VERSION 5.8 ;
BUSBITCHARS "[]" ;
DIVIDERCHAR "/" ;
UNITS
    DATABASE MICRONS 1000 ;
END UNITS

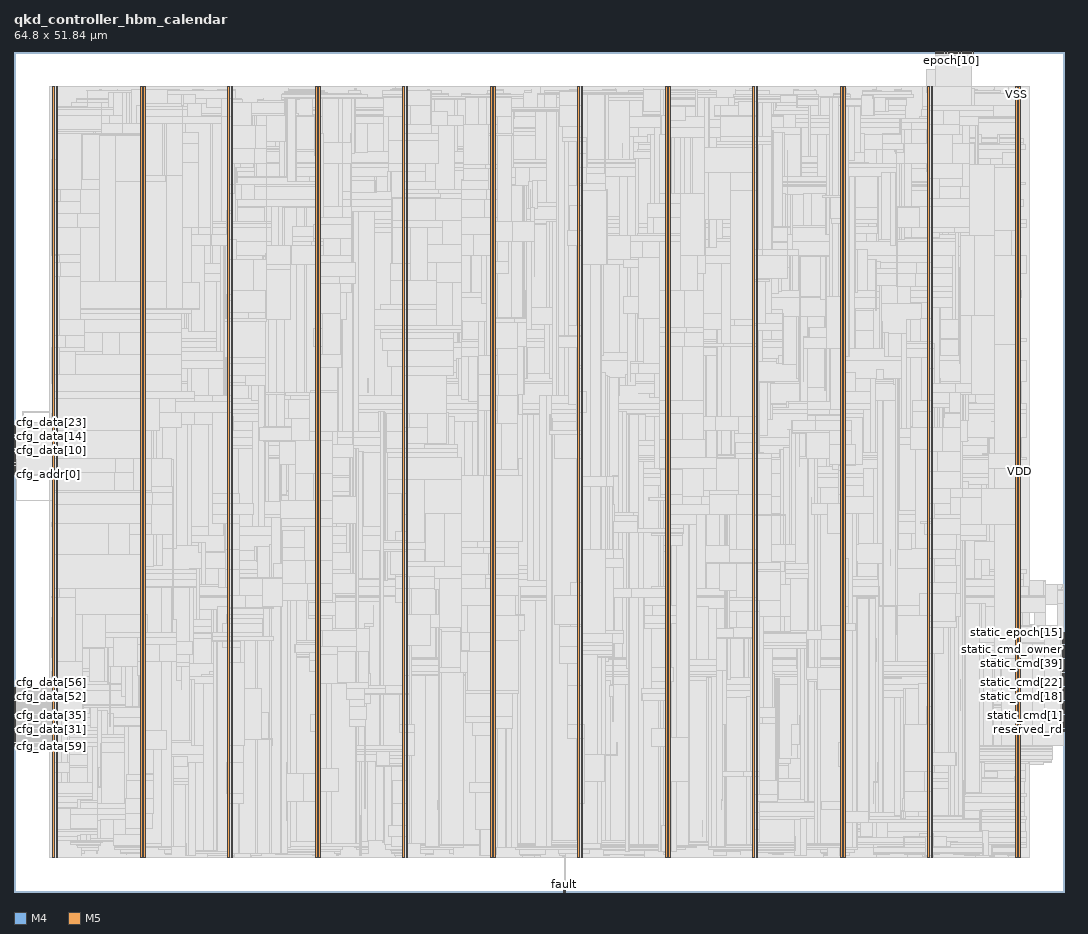
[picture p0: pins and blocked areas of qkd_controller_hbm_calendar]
MACRO qkd_controller_hbm_calendar
  FOREIGN qkd_controller_hbm_calendar 0 0 ;
  CLASS BLOCK ;
  SIZE 64.8 BY 51.84 ;
  PIN cfg_addr[0]
    DIRECTION INPUT ;
    USE SIGNAL ;
    PORT
      LAYER M4 ;
        RECT  0 25.776 0.084 25.8 ;
    END
  END cfg_addr[0]
  PIN cfg_addr[1]
    DIRECTION INPUT ;
    USE SIGNAL ;
    PORT
      LAYER M4 ;
        RECT  0 25.872 0.084 25.896 ;
    END
  END cfg_addr[1]
  PIN cfg_addr[2]
    DIRECTION INPUT ;
    USE SIGNAL ;
    PORT
      LAYER M4 ;
        RECT  0 25.968 0.084 25.992 ;
    END
  END cfg_addr[2]
  PIN cfg_addr[3]
    DIRECTION INPUT ;
    USE SIGNAL ;
    PORT
      LAYER M4 ;
        RECT  0 26.064 0.084 26.088 ;
    END
  END cfg_addr[3]
  PIN cfg_addr[4]
    DIRECTION INPUT ;
    USE SIGNAL ;
    PORT
      LAYER M4 ;
        RECT  0 26.16 0.084 26.184 ;
    END
  END cfg_addr[4]
  PIN cfg_data[0]
    DIRECTION INPUT ;
    USE SIGNAL ;
    PORT
      LAYER M4 ;
        RECT  0 26.256 0.084 26.28 ;
    END
  END cfg_data[0]
  PIN cfg_data[10]
    DIRECTION INPUT ;
    USE SIGNAL ;
    PORT
      LAYER M4 ;
        RECT  0 27.216 0.084 27.24 ;
    END
  END cfg_data[10]
  PIN cfg_data[11]
    DIRECTION INPUT ;
    USE SIGNAL ;
    PORT
      LAYER M4 ;
        RECT  0 27.312 0.084 27.336 ;
    END
  END cfg_data[11]
  PIN cfg_data[12]
    DIRECTION INPUT ;
    USE SIGNAL ;
    PORT
      LAYER M4 ;
        RECT  0 27.408 0.084 27.432 ;
    END
  END cfg_data[12]
  PIN cfg_data[13]
    DIRECTION INPUT ;
    USE SIGNAL ;
    PORT
      LAYER M4 ;
        RECT  0 27.504 0.084 27.528 ;
    END
  END cfg_data[13]
  PIN cfg_data[14]
    DIRECTION INPUT ;
    USE SIGNAL ;
    PORT
      LAYER M4 ;
        RECT  0 27.6 0.084 27.624 ;
    END
  END cfg_data[14]
  PIN cfg_data[15]
    DIRECTION INPUT ;
    USE SIGNAL ;
    PORT
      LAYER M4 ;
        RECT  0 27.696 0.084 27.72 ;
    END
  END cfg_data[15]
  PIN cfg_data[16]
    DIRECTION INPUT ;
    USE SIGNAL ;
    PORT
      LAYER M4 ;
        RECT  0 27.792 0.084 27.816 ;
    END
  END cfg_data[16]
  PIN cfg_data[17]
    DIRECTION INPUT ;
    USE SIGNAL ;
    PORT
      LAYER M4 ;
        RECT  0 27.888 0.084 27.912 ;
    END
  END cfg_data[17]
  PIN cfg_data[18]
    DIRECTION INPUT ;
    USE SIGNAL ;
    PORT
      LAYER M4 ;
        RECT  0 27.984 0.084 28.008 ;
    END
  END cfg_data[18]
  PIN cfg_data[19]
    DIRECTION INPUT ;
    USE SIGNAL ;
    PORT
      LAYER M4 ;
        RECT  0 28.08 0.084 28.104 ;
    END
  END cfg_data[19]
  PIN cfg_data[1]
    DIRECTION INPUT ;
    USE SIGNAL ;
    PORT
      LAYER M4 ;
        RECT  0 26.352 0.084 26.376 ;
    END
  END cfg_data[1]
  PIN cfg_data[20]
    DIRECTION INPUT ;
    USE SIGNAL ;
    PORT
      LAYER M4 ;
        RECT  0 28.176 0.084 28.2 ;
    END
  END cfg_data[20]
  PIN cfg_data[21]
    DIRECTION INPUT ;
    USE SIGNAL ;
    PORT
      LAYER M4 ;
        RECT  0 28.272 0.084 28.296 ;
    END
  END cfg_data[21]
  PIN cfg_data[22]
    DIRECTION INPUT ;
    USE SIGNAL ;
    PORT
      LAYER M4 ;
        RECT  0 28.368 0.084 28.392 ;
    END
  END cfg_data[22]
  PIN cfg_data[23]
    DIRECTION INPUT ;
    USE SIGNAL ;
    PORT
      LAYER M4 ;
        RECT  0 28.464 0.084 28.488 ;
    END
  END cfg_data[23]
  PIN cfg_data[24]
    DIRECTION INPUT ;
    USE SIGNAL ;
    PORT
      LAYER M4 ;
        RECT  0 28.56 0.084 28.584 ;
    END
  END cfg_data[24]
  PIN cfg_data[25]
    DIRECTION INPUT ;
    USE SIGNAL ;
    PORT
      LAYER M4 ;
        RECT  0 28.656 0.084 28.68 ;
    END
  END cfg_data[25]
  PIN cfg_data[26]
    DIRECTION INPUT ;
    USE SIGNAL ;
    PORT
      LAYER M4 ;
        RECT  0 28.752 0.084 28.776 ;
    END
  END cfg_data[26]
  PIN cfg_data[27]
    DIRECTION INPUT ;
    USE SIGNAL ;
    PORT
      LAYER M4 ;
        RECT  0 9.648 0.084 9.672 ;
    END
  END cfg_data[27]
  PIN cfg_data[28]
    DIRECTION INPUT ;
    USE SIGNAL ;
    PORT
      LAYER M4 ;
        RECT  0 9.744 0.084 9.768 ;
    END
  END cfg_data[28]
  PIN cfg_data[29]
    DIRECTION INPUT ;
    USE SIGNAL ;
    PORT
      LAYER M4 ;
        RECT  0 9.84 0.084 9.864 ;
    END
  END cfg_data[29]
  PIN cfg_data[2]
    DIRECTION INPUT ;
    USE SIGNAL ;
    PORT
      LAYER M4 ;
        RECT  0 26.448 0.084 26.472 ;
    END
  END cfg_data[2]
  PIN cfg_data[30]
    DIRECTION INPUT ;
    USE SIGNAL ;
    PORT
      LAYER M4 ;
        RECT  0 9.936 0.084 9.96 ;
    END
  END cfg_data[30]
  PIN cfg_data[31]
    DIRECTION INPUT ;
    USE SIGNAL ;
    PORT
      LAYER M4 ;
        RECT  0 10.032 0.084 10.056 ;
    END
  END cfg_data[31]
  PIN cfg_data[32]
    DIRECTION INPUT ;
    USE SIGNAL ;
    PORT
      LAYER M4 ;
        RECT  0 10.128 0.084 10.152 ;
    END
  END cfg_data[32]
  PIN cfg_data[33]
    DIRECTION INPUT ;
    USE SIGNAL ;
    PORT
      LAYER M4 ;
        RECT  0 10.224 0.084 10.248 ;
    END
  END cfg_data[33]
  PIN cfg_data[34]
    DIRECTION INPUT ;
    USE SIGNAL ;
    PORT
      LAYER M4 ;
        RECT  0 10.32 0.084 10.344 ;
    END
  END cfg_data[34]
  PIN cfg_data[35]
    DIRECTION INPUT ;
    USE SIGNAL ;
    PORT
      LAYER M4 ;
        RECT  0 10.416 0.084 10.44 ;
    END
  END cfg_data[35]
  PIN cfg_data[36]
    DIRECTION INPUT ;
    USE SIGNAL ;
    PORT
      LAYER M4 ;
        RECT  0 10.512 0.084 10.536 ;
    END
  END cfg_data[36]
  PIN cfg_data[37]
    DIRECTION INPUT ;
    USE SIGNAL ;
    PORT
      LAYER M4 ;
        RECT  0 10.608 0.084 10.632 ;
    END
  END cfg_data[37]
  PIN cfg_data[38]
    DIRECTION INPUT ;
    USE SIGNAL ;
    PORT
      LAYER M4 ;
        RECT  0 10.704 0.084 10.728 ;
    END
  END cfg_data[38]
  PIN cfg_data[39]
    DIRECTION INPUT ;
    USE SIGNAL ;
    PORT
      LAYER M4 ;
        RECT  0 10.8 0.084 10.824 ;
    END
  END cfg_data[39]
  PIN cfg_data[3]
    DIRECTION INPUT ;
    USE SIGNAL ;
    PORT
      LAYER M4 ;
        RECT  0 26.544 0.084 26.568 ;
    END
  END cfg_data[3]
  PIN cfg_data[40]
    DIRECTION INPUT ;
    USE SIGNAL ;
    PORT
      LAYER M4 ;
        RECT  0 10.896 0.084 10.92 ;
    END
  END cfg_data[40]
  PIN cfg_data[41]
    DIRECTION INPUT ;
    USE SIGNAL ;
    PORT
      LAYER M4 ;
        RECT  0 10.992 0.084 11.016 ;
    END
  END cfg_data[41]
  PIN cfg_data[42]
    DIRECTION INPUT ;
    USE SIGNAL ;
    PORT
      LAYER M4 ;
        RECT  0 11.088 0.084 11.112 ;
    END
  END cfg_data[42]
  PIN cfg_data[43]
    DIRECTION INPUT ;
    USE SIGNAL ;
    PORT
      LAYER M4 ;
        RECT  0 11.184 0.084 11.208 ;
    END
  END cfg_data[43]
  PIN cfg_data[44]
    DIRECTION INPUT ;
    USE SIGNAL ;
    PORT
      LAYER M4 ;
        RECT  0 11.28 0.084 11.304 ;
    END
  END cfg_data[44]
  PIN cfg_data[45]
    DIRECTION INPUT ;
    USE SIGNAL ;
    PORT
      LAYER M4 ;
        RECT  0 11.376 0.084 11.4 ;
    END
  END cfg_data[45]
  PIN cfg_data[46]
    DIRECTION INPUT ;
    USE SIGNAL ;
    PORT
      LAYER M4 ;
        RECT  0 11.472 0.084 11.496 ;
    END
  END cfg_data[46]
  PIN cfg_data[47]
    DIRECTION INPUT ;
    USE SIGNAL ;
    PORT
      LAYER M4 ;
        RECT  0 11.568 0.084 11.592 ;
    END
  END cfg_data[47]
  PIN cfg_data[48]
    DIRECTION INPUT ;
    USE SIGNAL ;
    PORT
      LAYER M4 ;
        RECT  0 11.664 0.084 11.688 ;
    END
  END cfg_data[48]
  PIN cfg_data[49]
    DIRECTION INPUT ;
    USE SIGNAL ;
    PORT
      LAYER M4 ;
        RECT  0 11.76 0.084 11.784 ;
    END
  END cfg_data[49]
  PIN cfg_data[4]
    DIRECTION INPUT ;
    USE SIGNAL ;
    PORT
      LAYER M4 ;
        RECT  0 26.64 0.084 26.664 ;
    END
  END cfg_data[4]
  PIN cfg_data[50]
    DIRECTION INPUT ;
    USE SIGNAL ;
    PORT
      LAYER M4 ;
        RECT  0 11.856 0.084 11.88 ;
    END
  END cfg_data[50]
  PIN cfg_data[51]
    DIRECTION INPUT ;
    USE SIGNAL ;
    PORT
      LAYER M4 ;
        RECT  0 11.952 0.084 11.976 ;
    END
  END cfg_data[51]
  PIN cfg_data[52]
    DIRECTION INPUT ;
    USE SIGNAL ;
    PORT
      LAYER M4 ;
        RECT  0 12.048 0.084 12.072 ;
    END
  END cfg_data[52]
  PIN cfg_data[53]
    DIRECTION INPUT ;
    USE SIGNAL ;
    PORT
      LAYER M4 ;
        RECT  0 12.144 0.084 12.168 ;
    END
  END cfg_data[53]
  PIN cfg_data[54]
    DIRECTION INPUT ;
    USE SIGNAL ;
    PORT
      LAYER M4 ;
        RECT  0 12.24 0.084 12.264 ;
    END
  END cfg_data[54]
  PIN cfg_data[55]
    DIRECTION INPUT ;
    USE SIGNAL ;
    PORT
      LAYER M4 ;
        RECT  0 12.336 0.084 12.36 ;
    END
  END cfg_data[55]
  PIN cfg_data[56]
    DIRECTION INPUT ;
    USE SIGNAL ;
    PORT
      LAYER M4 ;
        RECT  0 12.432 0.084 12.456 ;
    END
  END cfg_data[56]
  PIN cfg_data[57]
    DIRECTION INPUT ;
    USE SIGNAL ;
    PORT
      LAYER M4 ;
        RECT  0 12.528 0.084 12.552 ;
    END
  END cfg_data[57]
  PIN cfg_data[58]
    DIRECTION INPUT ;
    USE SIGNAL ;
    PORT
      LAYER M4 ;
        RECT  0 12.624 0.084 12.648 ;
    END
  END cfg_data[58]
  PIN cfg_data[59]
    DIRECTION INPUT ;
    USE SIGNAL ;
    PORT
      LAYER M4 ;
        RECT  0 8.976 0.084 9 ;
    END
  END cfg_data[59]
  PIN cfg_data[5]
    DIRECTION INPUT ;
    USE SIGNAL ;
    PORT
      LAYER M4 ;
        RECT  0 26.736 0.084 26.76 ;
    END
  END cfg_data[5]
  PIN cfg_data[60]
    DIRECTION INPUT ;
    USE SIGNAL ;
    PORT
      LAYER M4 ;
        RECT  0 9.072 0.084 9.096 ;
    END
  END cfg_data[60]
  PIN cfg_data[61]
    DIRECTION INPUT ;
    USE SIGNAL ;
    PORT
      LAYER M4 ;
        RECT  0 9.168 0.084 9.192 ;
    END
  END cfg_data[61]
  PIN cfg_data[62]
    DIRECTION INPUT ;
    USE SIGNAL ;
    PORT
      LAYER M4 ;
        RECT  0 9.264 0.084 9.288 ;
    END
  END cfg_data[62]
  PIN cfg_data[63]
    DIRECTION INPUT ;
    USE SIGNAL ;
    PORT
      LAYER M4 ;
        RECT  0 9.36 0.084 9.384 ;
    END
  END cfg_data[63]
  PIN cfg_data[6]
    DIRECTION INPUT ;
    USE SIGNAL ;
    PORT
      LAYER M4 ;
        RECT  0 26.832 0.084 26.856 ;
    END
  END cfg_data[6]
  PIN cfg_data[7]
    DIRECTION INPUT ;
    USE SIGNAL ;
    PORT
      LAYER M4 ;
        RECT  0 26.928 0.084 26.952 ;
    END
  END cfg_data[7]
  PIN cfg_data[8]
    DIRECTION INPUT ;
    USE SIGNAL ;
    PORT
      LAYER M4 ;
        RECT  0 27.024 0.084 27.048 ;
    END
  END cfg_data[8]
  PIN cfg_data[9]
    DIRECTION INPUT ;
    USE SIGNAL ;
    PORT
      LAYER M4 ;
        RECT  0 27.12 0.084 27.144 ;
    END
  END cfg_data[9]
  PIN cfg_we
    DIRECTION INPUT ;
    USE SIGNAL ;
    PORT
      LAYER M4 ;
        RECT  0 9.456 0.084 9.48 ;
    END
  END cfg_we
  PIN epoch[0]
    DIRECTION INPUT ;
    USE SIGNAL ;
    PORT
      LAYER M5 ;
        RECT  56.88 51.756 56.904 51.84 ;
    END
  END epoch[0]
  PIN epoch[10]
    DIRECTION INPUT ;
    USE SIGNAL ;
    PORT
      LAYER M5 ;
        RECT  57.84 51.756 57.864 51.84 ;
    END
  END epoch[10]
  PIN epoch[11]
    DIRECTION INPUT ;
    USE SIGNAL ;
    PORT
      LAYER M5 ;
        RECT  57.936 51.756 57.96 51.84 ;
    END
  END epoch[11]
  PIN epoch[12]
    DIRECTION INPUT ;
    USE SIGNAL ;
    PORT
      LAYER M5 ;
        RECT  58.032 51.756 58.056 51.84 ;
    END
  END epoch[12]
  PIN epoch[13]
    DIRECTION INPUT ;
    USE SIGNAL ;
    PORT
      LAYER M5 ;
        RECT  58.128 51.756 58.152 51.84 ;
    END
  END epoch[13]
  PIN epoch[14]
    DIRECTION INPUT ;
    USE SIGNAL ;
    PORT
      LAYER M5 ;
        RECT  58.224 51.756 58.248 51.84 ;
    END
  END epoch[14]
  PIN epoch[15]
    DIRECTION INPUT ;
    USE SIGNAL ;
    PORT
      LAYER M5 ;
        RECT  58.32 51.756 58.344 51.84 ;
    END
  END epoch[15]
  PIN epoch[1]
    DIRECTION INPUT ;
    USE SIGNAL ;
    PORT
      LAYER M5 ;
        RECT  56.976 51.756 57 51.84 ;
    END
  END epoch[1]
  PIN epoch[2]
    DIRECTION INPUT ;
    USE SIGNAL ;
    PORT
      LAYER M5 ;
        RECT  57.072 51.756 57.096 51.84 ;
    END
  END epoch[2]
  PIN epoch[3]
    DIRECTION INPUT ;
    USE SIGNAL ;
    PORT
      LAYER M5 ;
        RECT  57.168 51.756 57.192 51.84 ;
    END
  END epoch[3]
  PIN epoch[4]
    DIRECTION INPUT ;
    USE SIGNAL ;
    PORT
      LAYER M5 ;
        RECT  57.264 51.756 57.288 51.84 ;
    END
  END epoch[4]
  PIN epoch[5]
    DIRECTION INPUT ;
    USE SIGNAL ;
    PORT
      LAYER M5 ;
        RECT  57.36 51.756 57.384 51.84 ;
    END
  END epoch[5]
  PIN epoch[6]
    DIRECTION INPUT ;
    USE SIGNAL ;
    PORT
      LAYER M5 ;
        RECT  57.456 51.756 57.48 51.84 ;
    END
  END epoch[6]
  PIN epoch[7]
    DIRECTION INPUT ;
    USE SIGNAL ;
    PORT
      LAYER M5 ;
        RECT  57.552 51.756 57.576 51.84 ;
    END
  END epoch[7]
  PIN epoch[8]
    DIRECTION INPUT ;
    USE SIGNAL ;
    PORT
      LAYER M5 ;
        RECT  57.648 51.756 57.672 51.84 ;
    END
  END epoch[8]
  PIN epoch[9]
    DIRECTION INPUT ;
    USE SIGNAL ;
    PORT
      LAYER M5 ;
        RECT  57.744 51.756 57.768 51.84 ;
    END
  END epoch[9]
  PIN expected_raw_valid
    DIRECTION OUTPUT ;
    USE SIGNAL ;
    PORT
      LAYER M4 ;
        RECT  64.716 9.936 64.8 9.96 ;
    END
  END expected_raw_valid
  PIN fault
    DIRECTION OUTPUT ;
    USE SIGNAL ;
    PORT
      LAYER M5 ;
        RECT  33.936 0 33.96 0.084 ;
    END
  END fault
  PIN go
    DIRECTION INPUT ;
    USE SIGNAL ;
    PORT
      LAYER M5 ;
        RECT  58.416 51.756 58.44 51.84 ;
    END
  END go
  PIN hck
    DIRECTION INPUT ;
    USE SIGNAL ;
    PORT
      LAYER M5 ;
        RECT  58.512 51.756 58.536 51.84 ;
    END
  END hck
  PIN idle
    DIRECTION OUTPUT ;
    USE SIGNAL ;
    PORT
      LAYER M5 ;
        RECT  34.032 0 34.056 0.084 ;
    END
  END idle
  PIN layer[0]
    DIRECTION INPUT ;
    USE SIGNAL ;
    PORT
      LAYER M5 ;
        RECT  58.608 51.756 58.632 51.84 ;
    END
  END layer[0]
  PIN layer[1]
    DIRECTION INPUT ;
    USE SIGNAL ;
    PORT
      LAYER M5 ;
        RECT  58.704 51.756 58.728 51.84 ;
    END
  END layer[1]
  PIN layer[2]
    DIRECTION INPUT ;
    USE SIGNAL ;
    PORT
      LAYER M5 ;
        RECT  58.8 51.756 58.824 51.84 ;
    END
  END layer[2]
  PIN layer[3]
    DIRECTION INPUT ;
    USE SIGNAL ;
    PORT
      LAYER M5 ;
        RECT  58.896 51.756 58.92 51.84 ;
    END
  END layer[3]
  PIN layer[4]
    DIRECTION INPUT ;
    USE SIGNAL ;
    PORT
      LAYER M5 ;
        RECT  58.992 51.756 59.016 51.84 ;
    END
  END layer[4]
  PIN layer[5]
    DIRECTION INPUT ;
    USE SIGNAL ;
    PORT
      LAYER M5 ;
        RECT  59.088 51.756 59.112 51.84 ;
    END
  END layer[5]
  PIN reserved_rd
    DIRECTION OUTPUT ;
    USE SIGNAL ;
    PORT
      LAYER M4 ;
        RECT  64.716 10.032 64.8 10.056 ;
    END
  END reserved_rd
  PIN reserved_static_col
    DIRECTION OUTPUT ;
    USE SIGNAL ;
    PORT
      LAYER M4 ;
        RECT  64.716 10.128 64.8 10.152 ;
    END
  END reserved_static_col
  PIN reserved_write_col
    DIRECTION OUTPUT ;
    USE SIGNAL ;
    PORT
      LAYER M4 ;
        RECT  64.716 10.224 64.8 10.248 ;
    END
  END reserved_write_col
  PIN rst_n
    DIRECTION INPUT ;
    USE SIGNAL ;
    PORT
      LAYER M5 ;
        RECT  59.184 51.756 59.208 51.84 ;
    END
  END rst_n
  PIN seal
    DIRECTION INPUT ;
    USE SIGNAL ;
    PORT
      LAYER M4 ;
        RECT  0 9.552 0.084 9.576 ;
    END
  END seal
  PIN static_cmd[0]
    DIRECTION OUTPUT ;
    USE SIGNAL ;
    PORT
      LAYER M4 ;
        RECT  64.716 10.32 64.8 10.344 ;
    END
  END static_cmd[0]
  PIN static_cmd[10]
    DIRECTION OUTPUT ;
    USE SIGNAL ;
    PORT
      LAYER M4 ;
        RECT  64.716 11.28 64.8 11.304 ;
    END
  END static_cmd[10]
  PIN static_cmd[11]
    DIRECTION OUTPUT ;
    USE SIGNAL ;
    PORT
      LAYER M4 ;
        RECT  64.716 11.376 64.8 11.4 ;
    END
  END static_cmd[11]
  PIN static_cmd[12]
    DIRECTION OUTPUT ;
    USE SIGNAL ;
    PORT
      LAYER M4 ;
        RECT  64.716 11.472 64.8 11.496 ;
    END
  END static_cmd[12]
  PIN static_cmd[13]
    DIRECTION OUTPUT ;
    USE SIGNAL ;
    PORT
      LAYER M4 ;
        RECT  64.716 11.568 64.8 11.592 ;
    END
  END static_cmd[13]
  PIN static_cmd[14]
    DIRECTION OUTPUT ;
    USE SIGNAL ;
    PORT
      LAYER M4 ;
        RECT  64.716 11.664 64.8 11.688 ;
    END
  END static_cmd[14]
  PIN static_cmd[15]
    DIRECTION OUTPUT ;
    USE SIGNAL ;
    PORT
      LAYER M4 ;
        RECT  64.716 11.76 64.8 11.784 ;
    END
  END static_cmd[15]
  PIN static_cmd[16]
    DIRECTION OUTPUT ;
    USE SIGNAL ;
    PORT
      LAYER M4 ;
        RECT  64.716 11.856 64.8 11.88 ;
    END
  END static_cmd[16]
  PIN static_cmd[17]
    DIRECTION OUTPUT ;
    USE SIGNAL ;
    PORT
      LAYER M4 ;
        RECT  64.716 11.952 64.8 11.976 ;
    END
  END static_cmd[17]
  PIN static_cmd[18]
    DIRECTION OUTPUT ;
    USE SIGNAL ;
    PORT
      LAYER M4 ;
        RECT  64.716 12.048 64.8 12.072 ;
    END
  END static_cmd[18]
  PIN static_cmd[19]
    DIRECTION OUTPUT ;
    USE SIGNAL ;
    PORT
      LAYER M4 ;
        RECT  64.716 12.144 64.8 12.168 ;
    END
  END static_cmd[19]
  PIN static_cmd[1]
    DIRECTION OUTPUT ;
    USE SIGNAL ;
    PORT
      LAYER M4 ;
        RECT  64.716 10.416 64.8 10.44 ;
    END
  END static_cmd[1]
  PIN static_cmd[20]
    DIRECTION OUTPUT ;
    USE SIGNAL ;
    PORT
      LAYER M4 ;
        RECT  64.716 12.24 64.8 12.264 ;
    END
  END static_cmd[20]
  PIN static_cmd[21]
    DIRECTION OUTPUT ;
    USE SIGNAL ;
    PORT
      LAYER M4 ;
        RECT  64.716 12.336 64.8 12.36 ;
    END
  END static_cmd[21]
  PIN static_cmd[22]
    DIRECTION OUTPUT ;
    USE SIGNAL ;
    PORT
      LAYER M4 ;
        RECT  64.716 12.432 64.8 12.456 ;
    END
  END static_cmd[22]
  PIN static_cmd[23]
    DIRECTION OUTPUT ;
    USE SIGNAL ;
    PORT
      LAYER M4 ;
        RECT  64.716 12.528 64.8 12.552 ;
    END
  END static_cmd[23]
  PIN static_cmd[24]
    DIRECTION OUTPUT ;
    USE SIGNAL ;
    PORT
      LAYER M4 ;
        RECT  64.716 12.624 64.8 12.648 ;
    END
  END static_cmd[24]
  PIN static_cmd[25]
    DIRECTION OUTPUT ;
    USE SIGNAL ;
    PORT
      LAYER M4 ;
        RECT  64.716 12.72 64.8 12.744 ;
    END
  END static_cmd[25]
  PIN static_cmd[26]
    DIRECTION OUTPUT ;
    USE SIGNAL ;
    PORT
      LAYER M4 ;
        RECT  64.716 12.816 64.8 12.84 ;
    END
  END static_cmd[26]
  PIN static_cmd[27]
    DIRECTION OUTPUT ;
    USE SIGNAL ;
    PORT
      LAYER M4 ;
        RECT  64.716 12.912 64.8 12.936 ;
    END
  END static_cmd[27]
  PIN static_cmd[28]
    DIRECTION OUTPUT ;
    USE SIGNAL ;
    PORT
      LAYER M4 ;
        RECT  64.716 13.008 64.8 13.032 ;
    END
  END static_cmd[28]
  PIN static_cmd[29]
    DIRECTION OUTPUT ;
    USE SIGNAL ;
    PORT
      LAYER M4 ;
        RECT  64.716 13.104 64.8 13.128 ;
    END
  END static_cmd[29]
  PIN static_cmd[2]
    DIRECTION OUTPUT ;
    USE SIGNAL ;
    PORT
      LAYER M4 ;
        RECT  64.716 10.512 64.8 10.536 ;
    END
  END static_cmd[2]
  PIN static_cmd[30]
    DIRECTION OUTPUT ;
    USE SIGNAL ;
    PORT
      LAYER M4 ;
        RECT  64.716 13.2 64.8 13.224 ;
    END
  END static_cmd[30]
  PIN static_cmd[31]
    DIRECTION OUTPUT ;
    USE SIGNAL ;
    PORT
      LAYER M4 ;
        RECT  64.716 13.296 64.8 13.32 ;
    END
  END static_cmd[31]
  PIN static_cmd[32]
    DIRECTION OUTPUT ;
    USE SIGNAL ;
    PORT
      LAYER M4 ;
        RECT  64.716 13.392 64.8 13.416 ;
    END
  END static_cmd[32]
  PIN static_cmd[33]
    DIRECTION OUTPUT ;
    USE SIGNAL ;
    PORT
      LAYER M4 ;
        RECT  64.716 13.488 64.8 13.512 ;
    END
  END static_cmd[33]
  PIN static_cmd[34]
    DIRECTION OUTPUT ;
    USE SIGNAL ;
    PORT
      LAYER M4 ;
        RECT  64.716 13.584 64.8 13.608 ;
    END
  END static_cmd[34]
  PIN static_cmd[35]
    DIRECTION OUTPUT ;
    USE SIGNAL ;
    PORT
      LAYER M4 ;
        RECT  64.716 13.68 64.8 13.704 ;
    END
  END static_cmd[35]
  PIN static_cmd[36]
    DIRECTION OUTPUT ;
    USE SIGNAL ;
    PORT
      LAYER M4 ;
        RECT  64.716 13.776 64.8 13.8 ;
    END
  END static_cmd[36]
  PIN static_cmd[37]
    DIRECTION OUTPUT ;
    USE SIGNAL ;
    PORT
      LAYER M4 ;
        RECT  64.716 13.872 64.8 13.896 ;
    END
  END static_cmd[37]
  PIN static_cmd[38]
    DIRECTION OUTPUT ;
    USE SIGNAL ;
    PORT
      LAYER M4 ;
        RECT  64.716 13.968 64.8 13.992 ;
    END
  END static_cmd[38]
  PIN static_cmd[39]
    DIRECTION OUTPUT ;
    USE SIGNAL ;
    PORT
      LAYER M4 ;
        RECT  64.716 14.064 64.8 14.088 ;
    END
  END static_cmd[39]
  PIN static_cmd[3]
    DIRECTION OUTPUT ;
    USE SIGNAL ;
    PORT
      LAYER M4 ;
        RECT  64.716 10.608 64.8 10.632 ;
    END
  END static_cmd[3]
  PIN static_cmd[40]
    DIRECTION OUTPUT ;
    USE SIGNAL ;
    PORT
      LAYER M4 ;
        RECT  64.716 14.16 64.8 14.184 ;
    END
  END static_cmd[40]
  PIN static_cmd[41]
    DIRECTION OUTPUT ;
    USE SIGNAL ;
    PORT
      LAYER M4 ;
        RECT  64.716 14.256 64.8 14.28 ;
    END
  END static_cmd[41]
  PIN static_cmd[42]
    DIRECTION OUTPUT ;
    USE SIGNAL ;
    PORT
      LAYER M4 ;
        RECT  64.716 14.352 64.8 14.376 ;
    END
  END static_cmd[42]
  PIN static_cmd[4]
    DIRECTION OUTPUT ;
    USE SIGNAL ;
    PORT
      LAYER M4 ;
        RECT  64.716 10.704 64.8 10.728 ;
    END
  END static_cmd[4]
  PIN static_cmd[5]
    DIRECTION OUTPUT ;
    USE SIGNAL ;
    PORT
      LAYER M4 ;
        RECT  64.716 10.8 64.8 10.824 ;
    END
  END static_cmd[5]
  PIN static_cmd[6]
    DIRECTION OUTPUT ;
    USE SIGNAL ;
    PORT
      LAYER M4 ;
        RECT  64.716 10.896 64.8 10.92 ;
    END
  END static_cmd[6]
  PIN static_cmd[7]
    DIRECTION OUTPUT ;
    USE SIGNAL ;
    PORT
      LAYER M4 ;
        RECT  64.716 10.992 64.8 11.016 ;
    END
  END static_cmd[7]
  PIN static_cmd[8]
    DIRECTION OUTPUT ;
    USE SIGNAL ;
    PORT
      LAYER M4 ;
        RECT  64.716 11.088 64.8 11.112 ;
    END
  END static_cmd[8]
  PIN static_cmd[9]
    DIRECTION OUTPUT ;
    USE SIGNAL ;
    PORT
      LAYER M4 ;
        RECT  64.716 11.184 64.8 11.208 ;
    END
  END static_cmd[9]
  PIN static_cmd_owner
    DIRECTION OUTPUT ;
    USE SIGNAL ;
    PORT
      LAYER M4 ;
        RECT  64.716 14.448 64.8 14.472 ;
    END
  END static_cmd_owner
  PIN static_epoch[0]
    DIRECTION OUTPUT ;
    USE SIGNAL ;
    PORT
      LAYER M4 ;
        RECT  64.716 14.544 64.8 14.568 ;
    END
  END static_epoch[0]
  PIN static_epoch[10]
    DIRECTION OUTPUT ;
    USE SIGNAL ;
    PORT
      LAYER M4 ;
        RECT  64.716 15.504 64.8 15.528 ;
    END
  END static_epoch[10]
  PIN static_epoch[11]
    DIRECTION OUTPUT ;
    USE SIGNAL ;
    PORT
      LAYER M4 ;
        RECT  64.716 15.6 64.8 15.624 ;
    END
  END static_epoch[11]
  PIN static_epoch[12]
    DIRECTION OUTPUT ;
    USE SIGNAL ;
    PORT
      LAYER M4 ;
        RECT  64.716 15.696 64.8 15.72 ;
    END
  END static_epoch[12]
  PIN static_epoch[13]
    DIRECTION OUTPUT ;
    USE SIGNAL ;
    PORT
      LAYER M4 ;
        RECT  64.716 15.792 64.8 15.816 ;
    END
  END static_epoch[13]
  PIN static_epoch[14]
    DIRECTION OUTPUT ;
    USE SIGNAL ;
    PORT
      LAYER M4 ;
        RECT  64.716 15.888 64.8 15.912 ;
    END
  END static_epoch[14]
  PIN static_epoch[15]
    DIRECTION OUTPUT ;
    USE SIGNAL ;
    PORT
      LAYER M4 ;
        RECT  64.716 15.984 64.8 16.008 ;
    END
  END static_epoch[15]
  PIN static_epoch[1]
    DIRECTION OUTPUT ;
    USE SIGNAL ;
    PORT
      LAYER M4 ;
        RECT  64.716 14.64 64.8 14.664 ;
    END
  END static_epoch[1]
  PIN static_epoch[2]
    DIRECTION OUTPUT ;
    USE SIGNAL ;
    PORT
      LAYER M4 ;
        RECT  64.716 14.736 64.8 14.76 ;
    END
  END static_epoch[2]
  PIN static_epoch[3]
    DIRECTION OUTPUT ;
    USE SIGNAL ;
    PORT
      LAYER M4 ;
        RECT  64.716 14.832 64.8 14.856 ;
    END
  END static_epoch[3]
  PIN static_epoch[4]
    DIRECTION OUTPUT ;
    USE SIGNAL ;
    PORT
      LAYER M4 ;
        RECT  64.716 14.928 64.8 14.952 ;
    END
  END static_epoch[4]
  PIN static_epoch[5]
    DIRECTION OUTPUT ;
    USE SIGNAL ;
    PORT
      LAYER M4 ;
        RECT  64.716 15.024 64.8 15.048 ;
    END
  END static_epoch[5]
  PIN static_epoch[6]
    DIRECTION OUTPUT ;
    USE SIGNAL ;
    PORT
      LAYER M4 ;
        RECT  64.716 15.12 64.8 15.144 ;
    END
  END static_epoch[6]
  PIN static_epoch[7]
    DIRECTION OUTPUT ;
    USE SIGNAL ;
    PORT
      LAYER M4 ;
        RECT  64.716 15.216 64.8 15.24 ;
    END
  END static_epoch[7]
  PIN static_epoch[8]
    DIRECTION OUTPUT ;
    USE SIGNAL ;
    PORT
      LAYER M4 ;
        RECT  64.716 15.312 64.8 15.336 ;
    END
  END static_epoch[8]
  PIN static_epoch[9]
    DIRECTION OUTPUT ;
    USE SIGNAL ;
    PORT
      LAYER M4 ;
        RECT  64.716 15.408 64.8 15.432 ;
    END
  END static_epoch[9]
  PIN VDD
    DIRECTION INOUT ;
    USE POWER ;
    PORT
      LAYER M5 ;
        RECT  61.992 2.151 62.112 49.689 ;
        RECT  56.592 2.151 56.712 49.689 ;
        RECT  51.192 2.151 51.312 49.689 ;
        RECT  45.792 2.151 45.912 49.689 ;
        RECT  40.392 2.151 40.512 49.689 ;
        RECT  34.992 2.151 35.112 49.689 ;
        RECT  29.592 2.151 29.712 49.689 ;
        RECT  24.192 2.151 24.312 49.689 ;
        RECT  18.792 2.151 18.912 49.689 ;
        RECT  13.392 2.151 13.512 49.689 ;
        RECT  7.992 2.151 8.112 49.689 ;
        RECT  2.592 2.151 2.712 49.689 ;
    END
  END VDD
  PIN VSS
    DIRECTION INOUT ;
    USE GROUND ;
    PORT
      LAYER M5 ;
        RECT  61.8 2.137 61.92 49.703 ;
        RECT  56.4 2.137 56.52 49.703 ;
        RECT  51 2.137 51.12 49.703 ;
        RECT  45.6 2.137 45.72 49.703 ;
        RECT  40.2 2.137 40.32 49.703 ;
        RECT  34.8 2.137 34.92 49.703 ;
        RECT  29.4 2.137 29.52 49.703 ;
        RECT  24 2.137 24.12 49.703 ;
        RECT  18.6 2.137 18.72 49.703 ;
        RECT  13.2 2.137 13.32 49.703 ;
        RECT  7.8 2.137 7.92 49.703 ;
        RECT  2.4 2.137 2.52 49.703 ;
    END
  END VSS
  # OT_OBS_CLOSED layer=M5 d_um=1.536 added=323
  OBS
    LAYER RVTN ;
     RECT  2.16 2.16 62.64 2.295 ;
     RECT  2.16 2.565 62.64 2.835 ;
     RECT  2.16 3.105 62.64 3.375 ;
     RECT  2.16 3.645 62.64 3.915 ;
     RECT  2.16 4.185 62.64 4.455 ;
     RECT  2.16 4.725 62.64 4.995 ;
     RECT  2.16 5.265 62.64 5.535 ;
     RECT  2.16 5.805 62.64 6.075 ;
     RECT  2.16 6.345 62.64 6.615 ;
     RECT  2.16 6.885 62.64 7.155 ;
     RECT  2.16 7.425 62.64 7.695 ;
     RECT  2.16 7.965 62.64 8.235 ;
     RECT  2.16 8.505 62.64 8.775 ;
     RECT  2.16 9.045 62.64 9.315 ;
     RECT  2.16 9.585 62.64 9.855 ;
     RECT  2.16 10.125 62.64 10.395 ;
     RECT  2.16 10.665 62.64 10.935 ;
     RECT  2.16 11.205 62.64 11.475 ;
     RECT  2.16 11.745 62.64 12.015 ;
     RECT  2.16 12.285 62.64 12.555 ;
     RECT  2.16 12.825 62.64 13.095 ;
     RECT  2.16 13.365 62.64 13.635 ;
     RECT  2.16 13.905 62.64 14.175 ;
     RECT  2.16 14.445 62.64 14.715 ;
     RECT  2.16 14.985 62.64 15.255 ;
     RECT  2.16 15.525 62.64 15.795 ;
     RECT  2.16 16.065 62.64 16.335 ;
     RECT  2.16 16.605 62.64 16.875 ;
     RECT  2.16 17.145 62.64 17.415 ;
     RECT  2.16 17.685 62.64 17.955 ;
     RECT  2.16 18.225 62.64 18.495 ;
     RECT  2.16 18.765 62.64 19.035 ;
     RECT  2.16 19.305 62.64 19.575 ;
     RECT  2.16 19.845 62.64 20.115 ;
     RECT  2.16 20.385 62.64 20.655 ;
     RECT  2.16 20.925 62.64 21.195 ;
     RECT  2.16 21.465 62.64 21.735 ;
     RECT  2.16 22.005 62.64 22.275 ;
     RECT  2.16 22.545 62.64 22.815 ;
     RECT  2.16 23.085 62.64 23.355 ;
     RECT  2.16 23.625 62.64 23.895 ;
     RECT  2.16 24.165 62.64 24.435 ;
     RECT  2.16 24.705 62.64 24.975 ;
     RECT  2.16 25.245 62.64 25.515 ;
     RECT  2.16 25.785 62.64 26.055 ;
     RECT  2.16 26.325 62.64 26.595 ;
     RECT  2.16 26.865 62.64 27.135 ;
     RECT  2.16 27.405 62.64 27.675 ;
     RECT  2.16 27.945 62.64 28.215 ;
     RECT  2.16 28.485 62.64 28.755 ;
     RECT  2.16 29.025 62.64 29.295 ;
     RECT  2.16 29.565 62.64 29.835 ;
     RECT  2.16 30.105 62.64 30.375 ;
     RECT  2.16 30.645 62.64 30.915 ;
     RECT  2.16 31.185 62.64 31.455 ;
     RECT  2.16 31.725 62.64 31.995 ;
     RECT  2.16 32.265 62.64 32.535 ;
     RECT  2.16 32.805 62.64 33.075 ;
     RECT  2.16 33.345 62.64 33.615 ;
     RECT  2.16 33.885 62.64 34.155 ;
     RECT  2.16 34.425 62.64 34.695 ;
     RECT  2.16 34.965 62.64 35.235 ;
     RECT  2.16 35.505 62.64 35.775 ;
     RECT  2.16 36.045 62.64 36.315 ;
     RECT  2.16 36.585 62.64 36.855 ;
     RECT  2.16 37.125 62.64 37.395 ;
     RECT  2.16 37.665 62.64 37.935 ;
     RECT  2.16 38.205 62.64 38.475 ;
     RECT  2.16 38.745 62.64 39.015 ;
     RECT  2.16 39.285 62.64 39.555 ;
     RECT  2.16 39.825 62.64 40.095 ;
     RECT  2.16 40.365 62.64 40.635 ;
     RECT  2.16 40.905 62.64 41.175 ;
     RECT  2.16 41.445 62.64 41.715 ;
     RECT  2.16 41.985 62.64 42.255 ;
     RECT  2.16 42.525 62.64 42.795 ;
     RECT  2.16 43.065 62.64 43.335 ;
     RECT  2.16 43.605 62.64 43.875 ;
     RECT  2.16 44.145 62.64 44.415 ;
     RECT  2.16 44.685 62.64 44.955 ;
     RECT  2.16 45.225 62.64 45.495 ;
     RECT  2.16 45.765 62.64 46.035 ;
     RECT  2.16 46.305 62.64 46.575 ;
     RECT  2.16 46.845 62.64 47.115 ;
     RECT  2.16 47.385 62.64 47.655 ;
     RECT  2.16 47.925 62.64 48.195 ;
     RECT  2.16 48.465 62.64 48.735 ;
     RECT  2.16 49.005 62.64 49.275 ;
     RECT  2.16 49.545 62.64 49.68 ;
    LAYER RVTP ;
     RECT  2.16 2.295 62.64 2.565 ;
     RECT  2.16 2.835 62.64 3.105 ;
     RECT  2.16 3.375 62.64 3.645 ;
     RECT  2.16 3.915 62.64 4.185 ;
     RECT  2.16 4.455 62.64 4.725 ;
     RECT  2.16 4.995 62.64 5.265 ;
     RECT  2.16 5.535 62.64 5.805 ;
     RECT  2.16 6.075 62.64 6.345 ;
     RECT  2.16 6.615 62.64 6.885 ;
     RECT  2.16 7.155 62.64 7.425 ;
     RECT  2.16 7.695 62.64 7.965 ;
     RECT  2.16 8.235 62.64 8.505 ;
     RECT  2.16 8.775 62.64 9.045 ;
     RECT  2.16 9.315 62.64 9.585 ;
     RECT  2.16 9.855 62.64 10.125 ;
     RECT  2.16 10.395 62.64 10.665 ;
     RECT  2.16 10.935 62.64 11.205 ;
     RECT  2.16 11.475 62.64 11.745 ;
     RECT  2.16 12.015 62.64 12.285 ;
     RECT  2.16 12.555 62.64 12.825 ;
     RECT  2.16 13.095 62.64 13.365 ;
     RECT  2.16 13.635 62.64 13.905 ;
     RECT  2.16 14.175 62.64 14.445 ;
     RECT  2.16 14.715 62.64 14.985 ;
     RECT  2.16 15.255 62.64 15.525 ;
     RECT  2.16 15.795 62.64 16.065 ;
     RECT  2.16 16.335 62.64 16.605 ;
     RECT  2.16 16.875 62.64 17.145 ;
     RECT  2.16 17.415 62.64 17.685 ;
     RECT  2.16 17.955 62.64 18.225 ;
     RECT  2.16 18.495 62.64 18.765 ;
     RECT  2.16 19.035 62.64 19.305 ;
     RECT  2.16 19.575 62.64 19.845 ;
     RECT  2.16 20.115 62.64 20.385 ;
     RECT  2.16 20.655 62.64 20.925 ;
     RECT  2.16 21.195 62.64 21.465 ;
     RECT  2.16 21.735 62.64 22.005 ;
     RECT  2.16 22.275 62.64 22.545 ;
     RECT  2.16 22.815 62.64 23.085 ;
     RECT  2.16 23.355 62.64 23.625 ;
     RECT  2.16 23.895 62.64 24.165 ;
     RECT  2.16 24.435 62.64 24.705 ;
     RECT  2.16 24.975 62.64 25.245 ;
     RECT  2.16 25.515 62.64 25.785 ;
     RECT  2.16 26.055 62.64 26.325 ;
     RECT  2.16 26.595 62.64 26.865 ;
     RECT  2.16 27.135 62.64 27.405 ;
     RECT  2.16 27.675 62.64 27.945 ;
     RECT  2.16 28.215 62.64 28.485 ;
     RECT  2.16 28.755 62.64 29.025 ;
     RECT  2.16 29.295 62.64 29.565 ;
     RECT  2.16 29.835 62.64 30.105 ;
     RECT  2.16 30.375 62.64 30.645 ;
     RECT  2.16 30.915 62.64 31.185 ;
     RECT  2.16 31.455 62.64 31.725 ;
     RECT  2.16 31.995 62.64 32.265 ;
     RECT  2.16 32.535 62.64 32.805 ;
     RECT  2.16 33.075 62.64 33.345 ;
     RECT  2.16 33.615 62.64 33.885 ;
     RECT  2.16 34.155 62.64 34.425 ;
     RECT  2.16 34.695 62.64 34.965 ;
     RECT  2.16 35.235 62.64 35.505 ;
     RECT  2.16 35.775 62.64 36.045 ;
     RECT  2.16 36.315 62.64 36.585 ;
     RECT  2.16 36.855 62.64 37.125 ;
     RECT  2.16 37.395 62.64 37.665 ;
     RECT  2.16 37.935 62.64 38.205 ;
     RECT  2.16 38.475 62.64 38.745 ;
     RECT  2.16 39.015 62.64 39.285 ;
     RECT  2.16 39.555 62.64 39.825 ;
     RECT  2.16 40.095 62.64 40.365 ;
     RECT  2.16 40.635 62.64 40.905 ;
     RECT  2.16 41.175 62.64 41.445 ;
     RECT  2.16 41.715 62.64 41.985 ;
     RECT  2.16 42.255 62.64 42.525 ;
     RECT  2.16 42.795 62.64 43.065 ;
     RECT  2.16 43.335 62.64 43.605 ;
     RECT  2.16 43.875 62.64 44.145 ;
     RECT  2.16 44.415 62.64 44.685 ;
     RECT  2.16 44.955 62.64 45.225 ;
     RECT  2.16 45.495 62.64 45.765 ;
     RECT  2.16 46.035 62.64 46.305 ;
     RECT  2.16 46.575 62.64 46.845 ;
     RECT  2.16 47.115 62.64 47.385 ;
     RECT  2.16 47.655 62.64 47.925 ;
     RECT  2.16 48.195 62.64 48.465 ;
     RECT  2.16 48.735 62.64 49.005 ;
     RECT  2.16 49.275 62.64 49.545 ;
    LAYER M1 ;
     RECT  2.16 2.151 62.64 49.689 ;
    LAYER M2 ;
     RECT  0.103 9.09 0.139 9.108 ;
     RECT  0.103 12.33 0.347 12.348 ;
     RECT  0.139 8.82 2.16 9.108 ;
     RECT  0.103 25.722 2.16 25.74 ;
     RECT  0.535 29.61 2.16 29.628 ;
     RECT  2.16 2.151 23.539 49.689 ;
     RECT  23.539 2.106 32.495 49.689 ;
     RECT  32.495 2.151 53.203 49.689 ;
     RECT  53.203 2.106 56.075 49.689 ;
     RECT  56.075 2.151 60.511 49.689 ;
     RECT  60.511 2.106 61.367 49.689 ;
     RECT  61.367 2.151 62.64 49.689 ;
     RECT  62.64 7.866 63.563 16.524 ;
     RECT  63.563 7.974 63.599 16.524 ;
     RECT  62.64 17.766 63.635 19.224 ;
     RECT  63.599 7.974 63.851 16.434 ;
     RECT  63.851 7.974 63.887 12.276 ;
     RECT  63.887 12.258 63.923 12.276 ;
     RECT  63.887 7.974 63.959 11.232 ;
     RECT  63.959 7.974 64.031 8.226 ;
     RECT  63.959 9.054 64.067 11.232 ;
     RECT  64.031 8.208 64.103 8.226 ;
     RECT  63.635 17.766 64.391 18.954 ;
     RECT  63.851 13.806 64.463 16.434 ;
     RECT  64.463 13.806 64.499 15.786 ;
     RECT  64.067 10.404 64.643 10.926 ;
     RECT  64.499 13.806 64.679 15.588 ;
     RECT  64.391 17.856 64.679 18.954 ;
     RECT  64.643 10.404 64.715 10.854 ;
     RECT  64.679 13.806 64.715 14.544 ;
     RECT  64.679 15.57 64.715 15.588 ;
     RECT  64.679 18.126 64.715 18.954 ;
     RECT  64.715 18.576 64.751 18.954 ;
     RECT  64.067 9.054 64.787 9.072 ;
     RECT  64.687 12.141 64.787 12.159 ;
     RECT  64.715 14.526 64.787 14.544 ;
     RECT  64.751 18.576 64.787 18.594 ;
    LAYER M3 ;
     RECT  33.948 0.091 33.966 0.139 ;
     RECT  23.544 2.101 23.562 2.143 ;
     RECT  56.052 2.101 56.07 2.143 ;
     RECT  61.344 2.101 61.362 2.143 ;
     RECT  13.215 2.143 13.305 2.191 ;
     RECT  29.415 2.143 29.505 2.191 ;
     RECT  33.948 0.139 34.038 2.191 ;
     RECT  56.052 2.143 56.505 2.191 ;
     RECT  60.516 2.101 60.534 2.191 ;
     RECT  11.952 2.191 11.97 2.227 ;
     RECT  13.215 2.191 13.59 2.227 ;
     RECT  14.616 2.191 14.634 2.227 ;
     RECT  18.615 2.143 18.705 2.227 ;
     RECT  29.415 2.191 29.574 2.227 ;
     RECT  33.84 2.191 34.038 2.227 ;
     RECT  38.916 2.191 38.934 2.227 ;
     RECT  61.344 2.143 61.905 2.227 ;
     RECT  59.328 2.191 59.346 2.251 ;
     RECT  60.228 2.191 60.534 2.251 ;
     RECT  19.908 2.227 19.926 2.263 ;
     RECT  23.544 2.143 24.105 2.263 ;
     RECT  31.356 2.191 31.374 2.263 ;
     RECT  32.112 2.101 32.49 2.263 ;
     RECT  36.72 2.227 36.738 2.263 ;
     RECT  38.736 2.227 38.934 2.263 ;
     RECT  49.968 2.191 49.986 2.263 ;
     RECT  51.015 2.143 51.105 2.263 ;
     RECT  58.932 2.251 60.534 2.263 ;
     RECT  18.396 2.227 18.705 2.299 ;
     RECT  28.764 2.227 29.574 2.299 ;
     RECT  40.215 2.143 40.305 2.299 ;
     RECT  55.116 2.191 55.134 2.299 ;
     RECT  58.644 2.263 60.534 2.299 ;
     RECT  61.308 2.227 61.905 2.299 ;
     RECT  7.815 2.143 7.905 2.335 ;
     RECT  9.72 2.299 9.738 2.335 ;
     RECT  19.908 2.263 19.998 2.335 ;
     RECT  25.38 2.227 25.398 2.335 ;
     RECT  31.284 2.263 32.49 2.335 ;
     RECT  36.36 2.263 36.738 2.335 ;
     RECT  37.656 2.263 38.934 2.335 ;
     RECT  46.836 2.299 46.854 2.335 ;
     RECT  49.968 2.263 50.202 2.335 ;
     RECT  53.208 2.101 53.226 2.335 ;
     RECT  54 2.299 54.018 2.335 ;
     RECT  55.116 2.299 55.278 2.335 ;
     RECT  56.052 2.191 56.754 2.335 ;
     RECT  11.952 2.227 13.59 2.347 ;
     RECT  14.616 2.227 15.282 2.347 ;
     RECT  4.14 2.263 4.158 2.371 ;
     RECT  6.912 2.299 6.93 2.371 ;
     RECT  7.776 2.335 7.905 2.371 ;
     RECT  9.36 2.335 9.738 2.371 ;
     RECT  11.16 2.227 11.178 2.371 ;
     RECT  11.952 2.347 15.282 2.371 ;
     RECT  19.908 2.335 20.142 2.371 ;
     RECT  21.312 2.227 21.33 2.371 ;
     RECT  23.472 2.263 24.105 2.371 ;
     RECT  25.38 2.335 25.866 2.371 ;
     RECT  27.108 2.335 27.126 2.371 ;
     RECT  33.66 2.227 34.038 2.371 ;
     RECT  34.815 2.143 34.905 2.371 ;
     RECT  46.836 2.335 47.466 2.371 ;
     RECT  49.932 2.335 50.202 2.371 ;
     RECT  53.064 2.335 54.018 2.371 ;
     RECT  54.936 2.335 57.114 2.371 ;
     RECT  57.996 2.299 61.905 2.371 ;
     RECT  2.415 2.143 2.505 2.413 ;
     RECT  6.588 2.371 7.905 2.413 ;
     RECT  16.164 2.299 18.705 2.413 ;
     RECT  23.292 2.371 24.105 2.413 ;
     RECT  40.068 2.299 40.305 2.413 ;
     RECT  45.615 2.143 45.705 2.413 ;
     RECT  46.548 2.371 47.466 2.413 ;
     RECT  53.064 2.371 61.905 2.413 ;
     RECT  45.615 2.413 47.466 2.461 ;
     RECT  48.204 2.251 48.906 2.461 ;
     RECT  49.86 2.371 50.202 2.461 ;
     RECT  50.94 2.263 51.57 2.461 ;
     RECT  40.068 2.413 40.497 2.488 ;
     RECT  11.16 2.371 15.282 2.491 ;
     RECT  16.164 2.413 18.897 2.491 ;
     RECT  40.068 2.488 40.878 2.491 ;
     RECT  11.16 2.491 18.897 2.497 ;
     RECT  19.8 2.371 20.142 2.497 ;
     RECT  43.164 2.263 43.974 2.497 ;
     RECT  44.82 2.335 44.838 2.497 ;
     RECT  5.112 2.371 5.13 2.533 ;
     RECT  4.14 2.371 4.374 2.569 ;
     RECT  5.112 2.533 5.238 2.569 ;
     RECT  23.292 2.413 24.297 2.569 ;
     RECT  36.36 2.335 38.934 2.569 ;
     RECT  39.78 2.491 40.878 2.569 ;
     RECT  43.164 2.497 44.838 2.569 ;
     RECT  45.615 2.461 48.906 2.569 ;
     RECT  6.588 2.413 8.097 2.605 ;
     RECT  21.312 2.371 21.87 2.605 ;
     RECT  23.22 2.569 24.297 2.605 ;
     RECT  25.092 2.371 25.866 2.605 ;
     RECT  31.176 2.335 32.778 2.605 ;
     RECT  50.94 2.461 51.894 2.605 ;
     RECT  9.288 2.371 9.738 2.641 ;
     RECT  10.944 2.497 20.142 2.641 ;
     RECT  25.092 2.605 26.118 2.641 ;
     RECT  26.892 2.371 27.126 2.641 ;
     RECT  31.032 2.605 32.778 2.641 ;
     RECT  33.624 2.371 35.514 2.641 ;
     RECT  36.36 2.569 40.878 2.641 ;
     RECT  43.164 2.569 48.906 2.641 ;
     RECT  49.752 2.461 50.202 2.641 ;
     RECT  4.14 2.569 5.238 2.731 ;
     RECT  6.192 2.605 8.097 2.731 ;
     RECT  8.928 2.641 9.738 2.731 ;
     RECT  21.132 2.605 21.87 2.731 ;
     RECT  25.056 2.641 27.126 2.731 ;
     RECT  28.764 2.299 29.754 2.731 ;
     RECT  30.96 2.641 41.454 2.731 ;
     RECT  53.064 2.413 62.097 2.731 ;
     RECT  4.104 2.731 5.238 2.767 ;
     RECT  42.876 2.641 50.202 2.767 ;
     RECT  50.94 2.605 52.074 2.767 ;
     RECT  28.764 2.731 42.102 2.803 ;
     RECT  6.192 2.731 9.738 2.827 ;
     RECT  10.908 2.641 20.286 2.827 ;
     RECT  6.192 2.827 20.286 2.83 ;
     RECT  21.024 2.731 21.87 2.83 ;
     RECT  3.924 2.767 5.238 2.839 ;
     RECT  28.764 2.803 42.138 2.839 ;
     RECT  42.876 2.767 52.074 2.839 ;
     RECT  25.056 2.731 27.738 2.875 ;
     RECT  28.764 2.839 52.074 2.875 ;
     RECT  3.852 2.839 5.346 2.911 ;
     RECT  22.932 2.605 24.297 2.911 ;
     RECT  25.056 2.875 52.074 2.911 ;
     RECT  53.064 2.731 62.514 2.911 ;
     RECT  3.492 2.911 5.346 3.037 ;
     RECT  22.896 2.911 24.297 3.067 ;
     RECT  25.056 2.911 62.514 3.067 ;
     RECT  3.492 3.037 5.382 3.073 ;
     RECT  22.824 3.067 62.514 3.073 ;
     RECT  3.492 3.073 5.454 3.145 ;
     RECT  6.192 2.83 21.87 3.145 ;
     RECT  2.415 2.413 2.697 3.181 ;
     RECT  3.492 3.145 21.87 3.181 ;
     RECT  22.716 3.073 62.514 3.371 ;
     RECT  22.716 3.371 53.01 3.407 ;
     RECT  53.892 3.371 62.514 3.713 ;
     RECT  2.415 3.181 21.87 3.721 ;
     RECT  22.716 3.407 52.218 3.721 ;
     RECT  2.415 3.721 52.218 3.839 ;
     RECT  3.492 3.839 52.218 3.917 ;
     RECT  3.492 3.917 12.222 3.947 ;
     RECT  13.215 3.917 52.218 4.145 ;
     RECT  36.972 4.145 52.218 4.261 ;
     RECT  52.992 3.407 53.01 4.261 ;
     RECT  53.892 3.713 62.442 4.261 ;
     RECT  36.972 4.261 62.442 4.495 ;
     RECT  13.215 4.145 36.162 4.648 ;
     RECT  36.972 4.495 62.514 4.649 ;
     RECT  12.924 4.648 36.162 4.757 ;
     RECT  3.492 3.947 12.15 4.765 ;
     RECT  12.924 4.757 19.71 4.765 ;
     RECT  20.628 4.757 36.162 4.963 ;
     RECT  36.972 4.649 62.334 4.963 ;
     RECT  2.415 3.839 2.697 5.179 ;
     RECT  3.492 4.765 19.71 5.179 ;
     RECT  2.415 5.179 19.71 5.503 ;
     RECT  20.628 4.963 62.334 5.503 ;
     RECT  2.415 5.503 62.334 5.881 ;
     RECT  2.415 5.881 62.514 6.071 ;
     RECT  2.415 6.071 62.37 6.817 ;
     RECT  2.415 6.817 62.442 6.989 ;
     RECT  48.564 6.989 62.442 7.493 ;
     RECT  2.415 6.989 47.79 7.799 ;
     RECT  23.148 7.799 47.79 7.933 ;
     RECT  48.852 7.493 62.442 7.933 ;
     RECT  63.54 7.861 63.558 7.969 ;
     RECT  48.852 7.933 62.586 8.041 ;
     RECT  63.54 7.969 64.026 8.041 ;
     RECT  48.852 8.041 64.026 8.203 ;
     RECT  23.148 7.933 47.934 8.239 ;
     RECT  23.148 8.239 47.97 8.401 ;
     RECT  48.852 8.203 64.098 8.401 ;
     RECT  2.415 7.799 22.374 8.501 ;
     RECT  19.98 8.501 22.374 8.671 ;
     RECT  23.148 8.401 64.098 8.671 ;
     RECT  19.98 8.671 64.098 8.807 ;
     RECT  42.012 8.807 64.098 8.879 ;
     RECT  47.7 8.879 64.098 8.969 ;
     RECT  47.772 8.969 64.098 9.049 ;
     RECT  47.772 9.049 64.782 9.064 ;
     RECT  0.144 8.815 0.162 9.085 ;
     RECT  0.108 9.085 0.162 9.197 ;
     RECT  2.415 8.501 19.17 9.247 ;
     RECT  19.98 8.807 41.13 9.247 ;
     RECT  2.304 9.247 41.13 9.509 ;
     RECT  2.304 9.509 26.37 9.739 ;
     RECT  27.108 9.509 41.13 9.781 ;
     RECT  42.012 8.879 46.746 9.787 ;
     RECT  47.952 9.064 64.782 9.787 ;
     RECT  42.012 9.787 64.782 9.815 ;
     RECT  27.108 9.781 41.202 9.895 ;
     RECT  42.012 9.815 46.206 9.895 ;
     RECT  2.268 9.739 26.37 9.959 ;
     RECT  2.304 9.959 26.37 10.291 ;
     RECT  27.108 9.895 46.206 10.291 ;
     RECT  47.088 9.815 64.782 10.349 ;
     RECT  47.088 10.349 62.766 10.499 ;
     RECT  2.304 10.291 46.206 10.741 ;
     RECT  47.088 10.499 62.73 10.741 ;
     RECT  0.144 9.197 0.162 10.829 ;
     RECT  2.304 10.741 62.73 11.371 ;
     RECT  2.268 11.371 62.73 11.501 ;
     RECT  2.268 11.501 62.334 11.543 ;
     RECT  63.54 10.349 64.782 11.641 ;
     RECT  63.288 11.641 64.782 11.981 ;
     RECT  63.828 11.981 64.782 12.164 ;
     RECT  63.828 12.164 64.71 12.173 ;
     RECT  0.324 12.139 0.342 12.235 ;
     RECT  0.108 12.235 0.342 12.353 ;
     RECT  0.18 12.353 0.342 12.365 ;
     RECT  2.304 11.543 62.334 12.427 ;
     RECT  0.18 12.365 0.198 12.509 ;
     RECT  2.268 12.427 62.334 12.785 ;
     RECT  63.828 12.173 64.638 13.003 ;
     RECT  63.828 13.003 64.71 13.195 ;
     RECT  2.304 12.785 62.334 13.325 ;
     RECT  11.592 13.325 62.334 13.433 ;
     RECT  12.06 13.433 62.334 13.579 ;
     RECT  2.304 13.325 10.746 13.595 ;
     RECT  12.06 13.579 62.982 13.595 ;
     RECT  63.792 13.195 64.71 13.867 ;
     RECT  12.312 13.595 62.982 13.963 ;
     RECT  63.756 13.867 64.71 13.963 ;
     RECT  2.376 13.595 10.746 14.203 ;
     RECT  2.376 14.203 10.962 14.377 ;
     RECT  12.312 13.963 64.71 14.377 ;
     RECT  2.376 14.377 11.07 14.413 ;
     RECT  11.808 14.377 64.71 14.413 ;
     RECT  2.376 14.413 64.71 14.485 ;
     RECT  2.34 14.485 64.71 14.521 ;
     RECT  2.34 14.521 64.782 14.669 ;
     RECT  2.34 14.669 63.666 14.909 ;
     RECT  15.984 14.909 63.666 15.197 ;
     RECT  16.092 15.197 63.666 15.403 ;
     RECT  64.404 14.669 64.782 15.403 ;
     RECT  2.34 14.909 15.246 15.931 ;
     RECT  16.092 15.403 64.782 15.931 ;
     RECT  2.34 15.931 64.782 15.989 ;
     RECT  2.34 15.989 63.63 16.403 ;
     RECT  15.948 16.403 63.63 16.439 ;
     RECT  2.34 16.403 15.21 16.925 ;
     RECT  2.415 16.925 15.21 17.221 ;
     RECT  15.948 16.439 62.226 17.221 ;
     RECT  62.964 16.439 63.63 17.221 ;
     RECT  64.368 15.989 64.782 17.789 ;
     RECT  2.415 17.221 63.63 18.187 ;
     RECT  2.34 18.187 63.63 18.227 ;
     RECT  2.376 18.227 63.63 18.329 ;
     RECT  64.404 17.789 64.782 18.599 ;
     RECT  64.404 18.599 64.746 18.689 ;
     RECT  64.62 18.689 64.746 18.797 ;
     RECT  2.376 18.329 62.586 18.869 ;
     RECT  64.728 18.797 64.746 18.959 ;
     RECT  63.54 18.329 63.63 19.139 ;
     RECT  63.612 19.139 63.63 19.229 ;
     RECT  2.376 18.869 62.298 19.265 ;
     RECT  2.415 19.265 62.298 19.651 ;
     RECT  2.415 19.651 62.514 19.913 ;
     RECT  2.415 19.913 62.097 22.001 ;
     RECT  2.415 22.001 45.99 22.585 ;
     RECT  2.34 22.585 45.99 22.811 ;
     RECT  2.415 22.811 45.99 22.855 ;
     RECT  46.764 22.001 62.097 22.855 ;
     RECT  2.415 22.855 62.097 23.279 ;
     RECT  2.415 23.279 2.754 23.315 ;
     RECT  3.492 23.279 62.097 24.475 ;
     RECT  2.415 23.315 2.697 24.709 ;
     RECT  3.42 24.475 62.097 24.709 ;
     RECT  2.415 24.709 62.097 25.555 ;
     RECT  2.376 25.555 62.097 25.825 ;
     RECT  0.108 25.717 0.126 26.477 ;
     RECT  2.304 25.825 62.097 26.671 ;
     RECT  2.304 26.671 62.514 26.789 ;
     RECT  2.304 26.789 62.19 26.923 ;
     RECT  2.268 26.923 62.19 27.533 ;
     RECT  2.304 27.533 62.19 28.021 ;
     RECT  0.54 28.171 0.558 28.651 ;
     RECT  0.324 28.651 0.558 28.747 ;
     RECT  0.108 28.747 0.558 28.973 ;
     RECT  2.304 28.021 62.514 29.525 ;
     RECT  0.54 28.973 0.558 29.633 ;
     RECT  2.376 29.525 62.514 29.795 ;
     RECT  2.415 29.795 62.514 30.173 ;
     RECT  2.415 30.173 62.19 31.381 ;
     RECT  2.34 31.381 62.19 31.531 ;
     RECT  2.34 31.531 62.514 32.801 ;
     RECT  2.34 32.801 62.097 33.634 ;
     RECT  2.415 33.634 62.097 33.961 ;
     RECT  2.415 33.961 62.514 34.187 ;
     RECT  2.415 34.187 62.097 36.661 ;
     RECT  2.415 36.661 62.19 37.121 ;
     RECT  2.415 37.121 62.097 38.173 ;
     RECT  2.415 38.173 62.514 39.281 ;
     RECT  2.415 39.281 62.097 40.163 ;
     RECT  53.352 40.163 62.097 40.301 ;
     RECT  53.532 40.301 62.097 40.981 ;
     RECT  2.415 40.163 52.614 41.035 ;
     RECT  2.415 41.035 52.758 41.251 ;
     RECT  53.532 40.981 62.514 41.251 ;
     RECT  2.415 41.251 62.514 41.513 ;
     RECT  2.415 41.513 62.097 42.331 ;
     RECT  2.415 42.331 62.298 42.719 ;
     RECT  2.415 42.719 62.118 42.755 ;
     RECT  14.868 42.755 62.118 43.529 ;
     RECT  31.716 43.529 62.118 43.601 ;
     RECT  2.415 42.755 14.058 43.681 ;
     RECT  14.868 43.529 30.978 43.681 ;
     RECT  31.752 43.601 62.118 43.681 ;
     RECT  31.752 43.681 62.442 43.799 ;
     RECT  31.752 43.799 62.097 43.853 ;
     RECT  2.376 43.681 30.978 44.069 ;
     RECT  2.415 44.069 30.978 44.689 ;
     RECT  2.415 44.689 31.014 44.717 ;
     RECT  14.76 44.717 31.014 44.725 ;
     RECT  31.788 43.853 62.097 44.725 ;
     RECT  14.76 44.725 62.097 44.987 ;
     RECT  14.76 44.987 52.722 45.023 ;
     RECT  2.415 44.717 13.95 45.419 ;
     RECT  2.415 45.419 13.698 45.527 ;
     RECT  14.76 45.023 52.47 45.689 ;
     RECT  14.76 45.689 37.71 45.805 ;
     RECT  38.484 45.689 52.47 45.805 ;
     RECT  53.604 44.987 62.097 45.805 ;
     RECT  38.484 45.805 62.097 45.833 ;
     RECT  38.556 45.833 62.097 45.841 ;
     RECT  14.724 45.805 37.71 45.869 ;
     RECT  38.556 45.841 62.442 46.103 ;
     RECT  10.296 45.527 13.698 46.201 ;
     RECT  38.556 46.103 62.298 46.265 ;
     RECT  14.76 45.869 37.71 46.301 ;
     RECT  2.415 45.527 9.522 46.345 ;
     RECT  10.296 46.201 13.734 46.345 ;
     RECT  55.368 46.265 62.298 46.499 ;
     RECT  55.368 46.499 62.097 46.535 ;
     RECT  2.415 46.345 13.734 46.645 ;
     RECT  14.76 46.301 37.674 46.645 ;
     RECT  2.415 46.645 37.674 46.949 ;
     RECT  2.415 46.949 6.03 47.039 ;
     RECT  6.84 46.949 37.674 47.147 ;
     RECT  6.948 47.147 37.674 47.155 ;
     RECT  38.556 46.265 54.63 47.155 ;
     RECT  6.948 47.155 54.63 47.183 ;
     RECT  48.204 47.183 54.63 47.461 ;
     RECT  55.404 46.535 62.097 47.461 ;
     RECT  48.204 47.461 62.097 47.723 ;
     RECT  6.948 47.183 47.466 47.849 ;
     RECT  55.908 47.723 62.097 47.885 ;
     RECT  11.556 47.849 47.466 47.891 ;
     RECT  2.415 47.039 5.922 47.899 ;
     RECT  18.432 47.891 47.466 47.965 ;
     RECT  48.204 47.723 55.026 47.965 ;
     RECT  11.556 47.891 17.586 48.029 ;
     RECT  18.432 47.965 55.026 48.227 ;
     RECT  2.415 47.899 6.174 48.271 ;
     RECT  6.948 47.849 10.71 48.271 ;
     RECT  18.432 48.227 39.402 48.299 ;
     RECT  56.016 47.885 62.097 48.299 ;
     RECT  18.432 48.299 39.33 48.425 ;
     RECT  2.415 48.271 10.71 48.461 ;
     RECT  56.088 48.299 62.097 48.461 ;
     RECT  40.14 48.227 55.026 48.541 ;
     RECT  3.528 48.461 10.71 48.695 ;
     RECT  11.556 48.029 17.442 48.731 ;
     RECT  3.852 48.695 10.71 48.739 ;
     RECT  11.556 48.731 14.13 48.739 ;
     RECT  15.048 48.731 17.442 48.839 ;
     RECT  16.524 48.839 17.442 48.901 ;
     RECT  3.852 48.739 14.13 48.929 ;
     RECT  15.048 48.839 15.426 48.929 ;
     RECT  40.14 48.541 55.062 48.929 ;
     RECT  3.852 48.929 14.022 48.965 ;
     RECT  40.14 48.929 43.686 48.965 ;
     RECT  4.536 48.965 14.022 49.001 ;
     RECT  15.408 48.929 15.426 49.001 ;
     RECT  18.432 48.425 31.446 49.001 ;
     RECT  44.424 48.929 55.062 49.001 ;
     RECT  18.432 49.001 21.978 49.037 ;
     RECT  16.524 48.901 17.622 49.045 ;
     RECT  18.432 49.037 21.798 49.045 ;
     RECT  33.48 48.425 39.33 49.045 ;
     RECT  40.14 48.965 43.326 49.045 ;
     RECT  52.344 49.001 55.062 49.045 ;
     RECT  22.752 49.001 31.446 49.073 ;
     RECT  44.424 49.001 51.606 49.109 ;
     RECT  16.524 49.045 21.798 49.199 ;
     RECT  22.752 49.073 26.838 49.199 ;
     RECT  27.612 49.073 31.446 49.199 ;
     RECT  33.48 49.045 43.326 49.199 ;
     RECT  44.424 49.109 49.662 49.199 ;
     RECT  52.344 49.045 55.53 49.199 ;
     RECT  16.524 49.199 21.474 49.235 ;
     RECT  27.612 49.199 30.654 49.235 ;
     RECT  44.424 49.199 46.854 49.235 ;
     RECT  50.544 49.109 51.606 49.235 ;
     RECT  32.292 48.425 32.742 49.243 ;
     RECT  33.48 49.199 38.862 49.243 ;
     RECT  27.612 49.235 28.17 49.271 ;
     RECT  29.16 49.235 30.654 49.271 ;
     RECT  50.544 49.235 51.534 49.271 ;
     RECT  56.415 48.461 62.097 49.271 ;
     RECT  16.596 49.235 21.474 49.307 ;
     RECT  25.164 49.199 26.838 49.307 ;
     RECT  28.152 49.271 28.17 49.307 ;
     RECT  29.16 49.271 30.222 49.307 ;
     RECT  31.428 49.199 31.446 49.307 ;
     RECT  32.292 49.243 38.862 49.307 ;
     RECT  50.544 49.271 51.354 49.307 ;
     RECT  56.415 49.271 60.894 49.315 ;
     RECT  16.704 49.307 19.35 49.343 ;
     RECT  32.724 49.307 38.862 49.343 ;
     RECT  39.6 49.199 43.326 49.343 ;
     RECT  31.5 49.315 31.518 49.351 ;
     RECT  16.704 49.343 19.134 49.379 ;
     RECT  52.344 49.199 55.386 49.379 ;
     RECT  2.415 48.461 2.697 49.427 ;
     RECT  61.74 49.271 62.097 49.427 ;
     RECT  4.536 49.001 13.698 49.469 ;
     RECT  16.92 49.379 19.134 49.469 ;
     RECT  20.664 49.307 21.402 49.469 ;
     RECT  22.752 49.199 24.426 49.469 ;
     RECT  25.164 49.307 26.406 49.469 ;
     RECT  29.232 49.307 30.222 49.469 ;
     RECT  31.5 49.351 31.95 49.469 ;
     RECT  32.724 49.343 37.17 49.469 ;
     RECT  37.944 49.343 38.862 49.469 ;
     RECT  39.996 49.343 43.326 49.469 ;
     RECT  44.496 49.235 46.638 49.469 ;
     RECT  48.096 49.199 49.518 49.469 ;
     RECT  52.344 49.379 53.55 49.469 ;
     RECT  54.36 49.379 55.386 49.469 ;
     RECT  56.304 49.315 60.894 49.469 ;
     RECT  61.74 49.427 61.905 49.469 ;
     RECT  4.536 49.469 5.382 49.475 ;
     RECT  5.256 49.475 5.382 49.505 ;
     RECT  8.928 49.469 10.242 49.505 ;
     RECT  11.016 49.469 11.682 49.505 ;
     RECT  12.528 49.469 13.698 49.505 ;
     RECT  16.92 49.469 18.705 49.505 ;
     RECT  23.256 49.469 24.105 49.505 ;
     RECT  25.488 49.469 25.65 49.505 ;
     RECT  34.308 49.469 34.974 49.505 ;
     RECT  36.288 49.469 37.17 49.505 ;
     RECT  42.948 49.469 42.966 49.505 ;
     RECT  44.496 49.469 44.514 49.505 ;
     RECT  48.096 49.469 48.438 49.505 ;
     RECT  49.428 49.469 49.446 49.505 ;
     RECT  52.992 49.469 53.154 49.505 ;
     RECT  54.36 49.469 54.774 49.505 ;
     RECT  58.68 49.469 59.454 49.505 ;
     RECT  60.444 49.469 60.462 49.505 ;
     RECT  7.236 49.469 8.046 49.517 ;
     RECT  8.964 49.505 9.45 49.517 ;
     RECT  39.996 49.469 42.174 49.517 ;
     RECT  5.364 49.505 5.382 49.541 ;
     RECT  6.372 49.469 6.39 49.541 ;
     RECT  7.308 49.517 7.905 49.541 ;
     RECT  8.964 49.517 8.982 49.541 ;
     RECT  10.224 49.505 10.242 49.541 ;
     RECT  11.16 49.505 11.682 49.541 ;
     RECT  13.215 49.505 13.698 49.541 ;
     RECT  17.712 49.505 17.838 49.541 ;
     RECT  20.988 49.469 21.15 49.541 ;
     RECT  25.488 49.505 25.506 49.541 ;
     RECT  29.415 49.469 30.222 49.541 ;
     RECT  31.932 49.469 31.95 49.541 ;
     RECT  34.308 49.505 34.905 49.541 ;
     RECT  36.324 49.505 36.342 49.541 ;
     RECT  40.215 49.517 40.554 49.541 ;
     RECT  41.652 49.517 42.174 49.541 ;
     RECT  53.136 49.505 53.154 49.541 ;
     RECT  16.92 49.505 16.938 49.577 ;
     RECT  20.988 49.541 21.114 49.577 ;
     RECT  37.116 49.505 37.134 49.577 ;
     RECT  38.844 49.469 38.862 49.577 ;
     RECT  45.36 49.469 45.705 49.577 ;
     RECT  51.015 49.307 51.354 49.577 ;
     RECT  54.756 49.505 54.774 49.577 ;
     RECT  58.68 49.505 59.274 49.577 ;
     RECT  21.096 49.577 21.114 49.613 ;
     RECT  23.364 49.505 24.105 49.613 ;
     RECT  2.415 49.427 2.505 49.697 ;
     RECT  7.815 49.541 7.905 49.697 ;
     RECT  13.215 49.541 13.305 49.697 ;
     RECT  18.615 49.505 18.705 49.697 ;
     RECT  24.015 49.613 24.105 49.697 ;
     RECT  29.415 49.541 29.505 49.697 ;
     RECT  34.815 49.541 34.905 49.697 ;
     RECT  40.215 49.541 40.305 49.697 ;
     RECT  45.615 49.577 45.705 49.697 ;
     RECT  51.015 49.577 51.105 49.697 ;
     RECT  61.815 49.469 61.905 49.697 ;
     RECT  56.304 49.469 57.798 50.765 ;
     RECT  57.024 50.765 57.798 50.813 ;
     RECT  57.132 50.813 57.798 51.725 ;
     RECT  58.68 49.577 58.698 51.725 ;
    LAYER M4 ;
     RECT  0.084 25.776 0.097 25.8 ;
     RECT  0.06 25.8 0.097 25.872 ;
     RECT  0.084 25.872 0.097 25.896 ;
     RECT  0.06 25.896 0.097 25.968 ;
     RECT  0.084 25.968 0.097 25.992 ;
     RECT  0.06 25.992 0.097 26.064 ;
     RECT  0.084 26.064 0.097 26.088 ;
     RECT  0.06 26.088 0.097 26.16 ;
     RECT  0.084 26.16 0.097 26.184 ;
     RECT  0.06 26.184 0.097 26.256 ;
     RECT  0.084 26.256 0.097 26.28 ;
     RECT  0.06 26.28 0.097 26.352 ;
     RECT  0.084 26.352 0.097 26.376 ;
     RECT  0.06 26.376 0.097 26.448 ;
     RECT  0.084 26.448 0.097 26.472 ;
     RECT  0.06 26.472 0.097 26.544 ;
     RECT  0.084 26.544 0.097 26.568 ;
     RECT  0.06 26.568 0.097 26.64 ;
     RECT  0.084 26.64 0.097 26.664 ;
     RECT  0.06 26.664 0.097 26.736 ;
     RECT  0.084 26.736 0.097 26.76 ;
     RECT  0.06 26.76 0.097 26.832 ;
     RECT  0.084 26.832 0.097 26.856 ;
     RECT  0.06 26.856 0.097 26.928 ;
     RECT  0.084 26.928 0.097 26.952 ;
     RECT  0.06 26.952 0.097 27.024 ;
     RECT  0.084 27.024 0.097 27.048 ;
     RECT  0.06 27.048 0.097 27.12 ;
     RECT  0.084 27.12 0.097 27.144 ;
     RECT  0.06 27.144 0.097 27.216 ;
     RECT  0.084 27.216 0.097 27.24 ;
     RECT  0.06 27.24 0.097 27.312 ;
     RECT  0.084 27.312 0.097 27.336 ;
     RECT  0.06 27.336 0.097 27.408 ;
     RECT  0.084 27.408 0.097 27.432 ;
     RECT  0.06 27.432 0.097 27.504 ;
     RECT  0.084 27.504 0.097 27.528 ;
     RECT  0.06 27.528 0.097 27.6 ;
     RECT  0.084 27.6 0.097 27.624 ;
     RECT  0.06 27.624 0.097 27.696 ;
     RECT  0.084 27.696 0.097 27.72 ;
     RECT  0.06 27.72 0.097 27.792 ;
     RECT  0.084 27.792 0.097 27.816 ;
     RECT  0.06 27.816 0.097 27.888 ;
     RECT  0.084 27.888 0.097 27.912 ;
     RECT  0.06 27.912 0.097 27.984 ;
     RECT  0.084 27.984 0.097 28.008 ;
     RECT  0.06 28.008 0.097 28.08 ;
     RECT  0.084 28.08 0.097 28.104 ;
     RECT  0.06 28.104 0.097 28.176 ;
     RECT  0.084 28.176 0.097 28.2 ;
     RECT  0.06 28.2 0.097 28.272 ;
     RECT  0.084 28.272 0.097 28.296 ;
     RECT  0.06 28.296 0.097 28.368 ;
     RECT  0.084 28.368 0.097 28.392 ;
     RECT  0.06 28.392 0.097 28.464 ;
     RECT  0.084 28.464 0.097 28.488 ;
     RECT  0.06 28.488 0.097 28.56 ;
     RECT  0.084 28.56 0.097 28.584 ;
     RECT  0.06 28.584 0.097 28.656 ;
     RECT  0.084 28.656 0.097 28.68 ;
     RECT  0.06 28.68 0.097 28.752 ;
     RECT  0.084 28.752 0.097 28.776 ;
     RECT  0.084 8.976 2.401 9 ;
     RECT  0.06 9 2.401 9.072 ;
     RECT  0.084 9.072 2.401 9.096 ;
     RECT  0.06 9.096 2.401 9.168 ;
     RECT  0.084 9.168 2.401 9.192 ;
     RECT  0.06 9.192 2.401 9.264 ;
     RECT  0.084 9.264 2.401 9.288 ;
     RECT  0.06 9.288 2.401 9.36 ;
     RECT  0.084 9.36 2.401 9.384 ;
     RECT  0.06 9.384 2.401 9.456 ;
     RECT  0.084 9.456 2.401 9.48 ;
     RECT  0.06 9.48 2.401 9.552 ;
     RECT  0.084 9.552 2.401 9.576 ;
     RECT  0.06 9.576 2.401 9.648 ;
     RECT  0.084 9.648 2.401 9.672 ;
     RECT  0.06 9.672 2.401 9.744 ;
     RECT  0.084 9.744 2.401 9.768 ;
     RECT  0.06 9.768 2.401 9.84 ;
     RECT  0.084 9.84 2.401 9.864 ;
     RECT  0.06 9.864 2.401 9.936 ;
     RECT  0.084 9.936 2.401 9.96 ;
     RECT  0.06 9.96 2.401 10.032 ;
     RECT  0.084 10.032 2.401 10.056 ;
     RECT  0.06 10.056 2.401 10.128 ;
     RECT  0.084 10.128 2.401 10.152 ;
     RECT  0.06 10.152 2.401 10.224 ;
     RECT  0.084 10.224 2.401 10.248 ;
     RECT  0.06 10.248 2.401 10.32 ;
     RECT  0.084 10.32 2.401 10.344 ;
     RECT  0.06 10.344 2.401 10.416 ;
     RECT  0.084 10.416 2.401 10.44 ;
     RECT  0.06 10.44 2.401 10.512 ;
     RECT  0.084 10.512 2.401 10.536 ;
     RECT  0.06 10.536 2.401 10.608 ;
     RECT  0.084 10.608 2.401 10.632 ;
     RECT  0.06 10.632 2.401 10.704 ;
     RECT  0.084 10.704 2.401 10.728 ;
     RECT  0.06 10.728 2.401 10.8 ;
     RECT  0.084 10.8 2.401 10.824 ;
     RECT  0.06 10.824 2.401 10.896 ;
     RECT  0.084 10.896 2.401 10.92 ;
     RECT  0.06 10.92 2.401 10.992 ;
     RECT  0.084 10.992 2.401 11.016 ;
     RECT  0.06 11.016 2.401 11.088 ;
     RECT  0.084 11.088 2.401 11.112 ;
     RECT  0.06 11.112 2.401 11.184 ;
     RECT  0.084 11.184 2.401 11.208 ;
     RECT  0.06 11.208 2.401 11.28 ;
     RECT  0.084 11.28 2.401 11.304 ;
     RECT  0.06 11.304 2.401 11.376 ;
     RECT  0.084 11.376 2.401 11.4 ;
     RECT  0.06 11.4 2.401 11.472 ;
     RECT  0.084 11.472 2.401 11.496 ;
     RECT  0.06 11.496 2.401 11.568 ;
     RECT  0.084 11.568 2.401 11.592 ;
     RECT  0.06 11.592 2.401 11.664 ;
     RECT  0.084 11.664 2.401 11.688 ;
     RECT  0.06 11.688 2.401 11.76 ;
     RECT  0.084 11.76 2.401 11.784 ;
     RECT  0.06 11.784 2.401 11.856 ;
     RECT  0.084 11.856 2.401 11.88 ;
     RECT  0.06 11.88 2.401 11.952 ;
     RECT  0.084 11.952 2.401 11.976 ;
     RECT  0.06 11.976 2.401 12.048 ;
     RECT  0.084 12.048 2.401 12.072 ;
     RECT  0.06 12.072 2.401 12.144 ;
     RECT  0.084 12.144 2.401 12.168 ;
     RECT  0.06 12.168 2.401 12.24 ;
     RECT  0.084 12.24 2.401 12.264 ;
     RECT  0.06 12.264 2.401 12.336 ;
     RECT  0.084 12.336 2.401 12.36 ;
     RECT  0.06 12.36 2.401 12.432 ;
     RECT  0.084 12.432 2.401 12.456 ;
     RECT  0.06 12.456 2.401 12.528 ;
     RECT  0.084 12.528 2.401 12.552 ;
     RECT  0.06 12.552 2.401 12.624 ;
     RECT  0.084 12.624 2.401 12.648 ;
     RECT  2.401 8.976 2.408 12.792 ;
     RECT  2.329 14.688 2.408 14.712 ;
     RECT  2.329 16.896 2.408 16.92 ;
     RECT  2.329 18.192 2.408 18.216 ;
     RECT  0.133 24.144 2.408 24.168 ;
     RECT  0.097 25.776 2.408 28.968 ;
     RECT  2.329 31.392 2.408 31.416 ;
     RECT  2.329 33.6 2.408 33.624 ;
     RECT  2.293 39.312 2.408 39.336 ;
     RECT  2.293 45.168 2.408 45.192 ;
     RECT  2.408 2.148 2.512 49.692 ;
     RECT  2.512 2.418 2.704 49.422 ;
     RECT  2.704 11.664 2.765 12.792 ;
     RECT  2.765 11.664 2.801 12.408 ;
     RECT  2.704 17.952 2.819 18.984 ;
     RECT  2.704 20.304 2.819 20.328 ;
     RECT  2.704 37.008 2.867 39.624 ;
     RECT  2.704 42.432 2.867 43.368 ;
     RECT  2.704 6.768 2.909 10.68 ;
     RECT  2.801 12.048 3.017 12.408 ;
     RECT  2.867 38.784 3.089 39.624 ;
     RECT  2.909 6.768 3.305 10.104 ;
     RECT  3.305 6.768 3.443 9.576 ;
     RECT  3.443 8.928 3.449 9.576 ;
     RECT  2.704 44.976 3.557 46.776 ;
     RECT  2.704 24.144 3.685 24.36 ;
     RECT  2.704 16.272 3.697 16.92 ;
     RECT  2.819 17.952 3.697 18.792 ;
     RECT  2.704 21.36 3.733 23.16 ;
     RECT  3.685 24.144 3.733 24.456 ;
     RECT  2.704 25.536 3.733 32.568 ;
     RECT  3.733 24.144 3.74 32.568 ;
     RECT  2.704 33.6 3.74 35.448 ;
     RECT  2.704 41.376 3.805 41.4 ;
     RECT  2.867 42.432 3.805 42.648 ;
     RECT  3.697 16.272 3.809 18.792 ;
     RECT  2.704 13.824 3.841 14.712 ;
     RECT  3.733 21.264 3.841 23.16 ;
     RECT  3.805 41.376 3.841 42.648 ;
     RECT  3.841 21.072 3.877 23.16 ;
     RECT  3.74 24.144 3.877 35.448 ;
     RECT  3.841 41.376 3.877 43.368 ;
     RECT  3.809 16.272 3.881 18.648 ;
     RECT  3.877 21.072 3.917 35.448 ;
     RECT  2.704 3.168 3.949 3.432 ;
     RECT  2.704 5.184 3.949 5.208 ;
     RECT  3.881 16.272 3.989 17.592 ;
     RECT  3.949 11.376 4.021 11.4 ;
     RECT  3.017 12.384 4.021 12.408 ;
     RECT  3.089 38.784 4.093 38.808 ;
     RECT  2.867 37.008 4.117 37.512 ;
     RECT  4.093 38.784 4.117 39.144 ;
     RECT  4.117 37.008 4.124 39.144 ;
     RECT  3.949 3.168 4.129 3.48 ;
     RECT  3.949 5.184 4.133 5.736 ;
     RECT  3.917 33.6 4.133 35.448 ;
     RECT  3.877 41.04 4.163 43.368 ;
     RECT  4.124 37.008 4.205 39.576 ;
     RECT  4.021 11.376 4.213 12.408 ;
     RECT  4.205 38.64 4.268 39.576 ;
     RECT  4.163 41.04 4.268 42.456 ;
     RECT  4.213 11.04 4.277 12.408 ;
     RECT  4.277 12.384 4.349 12.408 ;
     RECT  4.129 3.168 4.453 3.528 ;
     RECT  4.205 37.008 4.489 37.512 ;
     RECT  4.268 38.64 4.499 42.456 ;
     RECT  3.443 6.768 4.561 7.656 ;
     RECT  3.449 8.928 4.561 8.952 ;
     RECT  4.501 49.44 4.588 49.464 ;
     RECT  4.499 38.64 4.595 39.912 ;
     RECT  4.525 20.064 4.597 20.088 ;
     RECT  3.917 21.072 4.597 21.624 ;
     RECT  4.277 11.04 4.669 11.4 ;
     RECT  3.841 13.824 4.669 15.048 ;
     RECT  4.669 10.992 4.705 11.4 ;
     RECT  4.133 34.176 4.705 35.448 ;
     RECT  4.489 36.912 4.705 37.512 ;
     RECT  4.499 41.04 4.709 42.456 ;
     RECT  4.453 3.168 4.745 3.576 ;
     RECT  3.881 18.624 4.777 18.648 ;
     RECT  4.597 20.064 4.777 21.624 ;
     RECT  4.133 5.664 4.849 5.736 ;
     RECT  4.561 6.768 4.849 8.952 ;
     RECT  3.557 46.224 4.849 46.776 ;
     RECT  4.777 18.624 4.853 21.624 ;
     RECT  4.849 45.888 4.885 46.776 ;
     RECT  4.885 45.888 5.029 46.92 ;
     RECT  4.309 43.44 5.069 43.944 ;
     RECT  3.989 16.272 5.077 17.4 ;
     RECT  4.853 18.624 5.123 19.608 ;
     RECT  4.853 20.736 5.123 21.624 ;
     RECT  4.745 3.312 5.125 3.576 ;
     RECT  4.849 5.664 5.125 8.952 ;
     RECT  5.125 5.472 5.137 8.952 ;
     RECT  4.705 10.128 5.137 11.4 ;
     RECT  5.077 16.272 5.137 17.64 ;
     RECT  5.137 5.472 5.177 11.4 ;
     RECT  4.705 34.176 5.228 37.512 ;
     RECT  4.595 38.64 5.228 38.664 ;
     RECT  3.917 22.656 5.269 32.568 ;
     RECT  5.228 34.176 5.269 38.664 ;
     RECT  5.269 33.648 5.315 38.664 ;
     RECT  5.125 3.312 5.317 4.392 ;
     RECT  5.123 20.784 5.353 21.624 ;
     RECT  5.269 22.656 5.353 32.664 ;
     RECT  5.315 33.648 5.363 37.656 ;
     RECT  2.704 48.432 5.365 48.456 ;
     RECT  5.177 5.472 5.393 11.208 ;
     RECT  5.363 33.648 5.393 37.512 ;
     RECT  5.137 16.032 5.429 17.64 ;
     RECT  5.123 19.344 5.437 19.608 ;
     RECT  5.029 45.024 5.533 46.92 ;
     RECT  4.595 39.696 5.537 39.912 ;
     RECT  5.437 19.584 5.573 19.608 ;
     RECT  4.669 13.008 5.605 15.048 ;
     RECT  5.429 16.032 5.605 17.16 ;
     RECT  4.709 41.04 5.681 42.36 ;
     RECT  5.393 9.744 5.789 11.208 ;
     RECT  5.605 13.008 5.797 17.16 ;
     RECT  5.315 38.64 5.821 38.664 ;
     RECT  5.537 39.696 5.821 39.72 ;
     RECT  5.365 48.432 5.821 48.696 ;
     RECT  5.393 33.648 5.897 37.368 ;
     RECT  5.533 44.928 5.965 46.92 ;
     RECT  5.353 20.784 6.001 32.664 ;
     RECT  5.897 34.224 6.077 37.368 ;
     RECT  5.789 9.744 6.113 11.016 ;
     RECT  5.317 3.312 6.133 4.488 ;
     RECT  5.821 48.432 6.145 49.368 ;
     RECT  6.077 34.224 6.221 35.448 ;
     RECT  5.681 41.76 6.289 42.36 ;
     RECT  5.069 43.44 6.289 43.464 ;
     RECT  6.077 36.528 6.397 37.368 ;
     RECT  5.821 38.64 6.397 39.72 ;
     RECT  6.001 20.784 6.433 33.144 ;
     RECT  6.221 34.416 6.509 35.448 ;
     RECT  6.289 41.76 6.524 43.464 ;
     RECT  5.965 44.736 6.524 46.92 ;
     RECT  6.397 36.528 6.611 39.72 ;
     RECT  5.797 12.864 6.613 17.16 ;
     RECT  6.524 41.76 6.709 46.92 ;
     RECT  6.145 47.904 6.709 49.368 ;
     RECT  5.393 5.472 6.829 8.616 ;
     RECT  6.113 9.744 6.829 10.2 ;
     RECT  6.433 20.16 6.829 33.144 ;
     RECT  6.613 12.096 6.865 17.16 ;
     RECT  6.829 19.344 6.865 33.144 ;
     RECT  6.709 41.76 6.937 49.368 ;
     RECT  6.133 2.88 7.045 4.488 ;
     RECT  6.829 5.472 7.045 10.2 ;
     RECT  6.611 38.208 7.148 39.72 ;
     RECT  6.937 40.848 7.148 49.368 ;
     RECT  7.148 38.208 7.225 49.368 ;
     RECT  6.865 11.472 7.297 17.16 ;
     RECT  6.865 18.96 7.573 33.144 ;
     RECT  7.297 11.472 7.657 17.688 ;
     RECT  7.657 11.472 7.765 17.736 ;
     RECT  7.573 18.816 7.765 33.144 ;
     RECT  7.045 2.88 7.808 10.2 ;
     RECT  7.765 11.472 7.808 33.144 ;
     RECT  6.509 34.416 7.808 35.304 ;
     RECT  6.611 36.528 7.808 37.128 ;
     RECT  7.225 38.208 7.808 49.512 ;
     RECT  7.808 2.148 7.912 49.692 ;
     RECT  7.912 2.418 8.104 49.512 ;
     RECT  8.104 20.064 8.579 37.32 ;
     RECT  8.579 20.064 8.633 33.384 ;
     RECT  8.579 34.8 8.669 37.32 ;
     RECT  8.669 34.8 8.705 36.6 ;
     RECT  8.633 20.16 8.813 33.384 ;
     RECT  8.104 3.024 9.133 18.792 ;
     RECT  8.813 20.16 9.137 30.888 ;
     RECT  8.104 38.976 9.157 39.672 ;
     RECT  8.104 40.848 9.157 47.448 ;
     RECT  9.137 20.16 9.173 20.184 ;
     RECT  9.157 38.976 9.173 47.448 ;
     RECT  9.173 39.072 9.281 47.448 ;
     RECT  8.813 32.064 9.317 33.384 ;
     RECT  9.281 40.608 9.395 47.448 ;
     RECT  8.104 48.672 9.461 49.512 ;
     RECT  8.705 34.8 9.709 36.36 ;
     RECT  9.493 37.584 9.709 37.608 ;
     RECT  9.133 2.832 9.713 18.792 ;
     RECT  9.713 2.832 9.821 8.376 ;
     RECT  9.137 21.216 10.001 30.888 ;
     RECT  9.317 32.304 10.001 33.384 ;
     RECT  9.281 39.072 10.321 39.288 ;
     RECT  10.321 38.976 10.357 39.288 ;
     RECT  9.461 48.672 10.357 49.224 ;
     RECT  10.357 48.48 10.441 49.224 ;
     RECT  9.709 34.8 10.501 37.608 ;
     RECT  10.357 38.976 10.501 39.48 ;
     RECT  9.821 2.832 10.597 6.648 ;
     RECT  9.395 40.896 10.613 47.448 ;
     RECT  10.501 34.8 10.645 39.48 ;
     RECT  10.001 21.36 10.717 30.888 ;
     RECT  10.001 32.304 10.717 32.328 ;
     RECT  9.821 7.776 10.721 8.376 ;
     RECT  10.597 2.256 10.789 6.648 ;
     RECT  10.721 7.776 10.789 7.992 ;
     RECT  10.645 34.752 10.789 39.48 ;
     RECT  9.713 9.36 10.835 18.792 ;
     RECT  10.789 34.56 10.933 39.48 ;
     RECT  10.835 9.36 10.969 13.128 ;
     RECT  10.717 21.36 10.973 32.328 ;
     RECT  10.835 14.112 11.081 18.792 ;
     RECT  10.969 9.024 11.117 13.128 ;
     RECT  10.789 2.256 11.189 7.992 ;
     RECT  10.441 48.672 11.189 49.224 ;
     RECT  11.081 16.8 11.293 18.792 ;
     RECT  10.861 19.968 11.293 19.992 ;
     RECT  10.973 21.36 11.365 21.576 ;
     RECT  11.293 16.8 11.441 19.992 ;
     RECT  11.441 16.8 11.459 17.928 ;
     RECT  11.441 19.008 11.581 19.992 ;
     RECT  11.365 20.976 11.581 21.576 ;
     RECT  11.189 2.592 11.725 7.992 ;
     RECT  11.117 9.024 11.725 12.888 ;
     RECT  10.933 34.56 11.729 39.912 ;
     RECT  11.581 19.008 11.801 21.576 ;
     RECT  11.801 19.008 11.837 21 ;
     RECT  11.189 48.672 11.869 48.984 ;
     RECT  10.973 22.56 11.977 32.328 ;
     RECT  11.729 38.784 12.133 39.912 ;
     RECT  10.613 40.992 12.133 47.448 ;
     RECT  11.081 14.112 12.188 15.624 ;
     RECT  11.459 16.8 12.188 17.448 ;
     RECT  12.133 38.784 12.22 47.448 ;
     RECT  12.22 41.04 12.233 47.448 ;
     RECT  11.725 2.592 12.301 12.888 ;
     RECT  12.188 14.112 12.301 17.448 ;
     RECT  10.001 33.36 12.481 33.384 ;
     RECT  11.729 34.56 12.481 37.656 ;
     RECT  12.301 2.592 12.517 17.448 ;
     RECT  12.517 2.496 12.553 17.448 ;
     RECT  11.837 19.008 12.625 19.944 ;
     RECT  12.481 33.36 12.733 37.656 ;
     RECT  12.22 38.784 12.733 39.912 ;
     RECT  12.233 41.376 12.805 47.448 ;
     RECT  11.869 48.432 12.805 48.984 ;
     RECT  11.977 22.032 12.949 32.328 ;
     RECT  12.733 33.36 12.949 39.912 ;
     RECT  11.837 20.928 12.985 21 ;
     RECT  12.949 22.032 12.985 39.912 ;
     RECT  12.625 18.816 13.045 19.944 ;
     RECT  12.985 20.928 13.045 39.912 ;
     RECT  12.553 2.496 13.208 17.64 ;
     RECT  13.045 18.816 13.208 39.912 ;
     RECT  12.805 41.376 13.208 48.984 ;
     RECT  13.208 2.148 13.312 49.692 ;
     RECT  13.312 2.352 13.504 49.422 ;
     RECT  13.504 28.464 13.565 29.352 ;
     RECT  13.504 41.376 13.645 44.664 ;
     RECT  13.645 43.776 13.709 44.664 ;
     RECT  13.504 38.976 13.715 40.248 ;
     RECT  13.715 40.224 13.756 40.248 ;
     RECT  13.504 36.816 13.781 37.656 ;
     RECT  13.645 41.376 13.781 42.744 ;
     RECT  13.709 43.776 13.817 44.472 ;
     RECT  13.504 2.352 13.853 27.384 ;
     RECT  13.853 2.352 13.889 21.096 ;
     RECT  13.781 36.816 13.961 37.224 ;
     RECT  13.961 36.96 14.177 37.224 ;
     RECT  13.504 30.432 14.483 35.736 ;
     RECT  14.483 30.432 14.641 33.96 ;
     RECT  13.504 45.984 14.645 48.696 ;
     RECT  13.853 22.56 14.713 27.384 ;
     RECT  13.565 28.464 14.713 29.064 ;
     RECT  14.645 45.984 14.713 47.928 ;
     RECT  14.177 37.104 14.821 37.224 ;
     RECT  13.817 44.16 14.821 44.472 ;
     RECT  14.713 45.84 14.821 47.928 ;
     RECT  13.889 20.448 14.857 21.096 ;
     RECT  13.889 2.352 14.929 19.368 ;
     RECT  14.821 44.16 14.963 47.928 ;
     RECT  14.857 20.448 14.965 21.336 ;
     RECT  14.929 2.352 15.037 19.416 ;
     RECT  14.965 20.4 15.037 21.336 ;
     RECT  14.483 34.944 15.077 35.4 ;
     RECT  14.713 22.56 15.109 29.064 ;
     RECT  14.641 30.336 15.109 33.96 ;
     RECT  13.715 38.976 15.325 39.048 ;
     RECT  14.821 37.104 15.397 37.368 ;
     RECT  15.325 38.976 15.397 39.24 ;
     RECT  13.781 41.376 15.469 42.264 ;
     RECT  15.109 22.56 15.473 33.96 ;
     RECT  15.397 37.104 15.493 39.24 ;
     RECT  15.473 24.096 15.505 33.96 ;
     RECT  15.077 34.944 15.505 35.352 ;
     RECT  14.963 47.04 15.589 47.928 ;
     RECT  15.505 24.096 15.689 35.352 ;
     RECT  15.037 2.352 15.757 21.336 ;
     RECT  15.493 37.104 15.865 39.384 ;
     RECT  15.757 2.352 15.901 21.432 ;
     RECT  15.473 22.56 15.901 23.112 ;
     RECT  15.865 37.104 15.901 39.912 ;
     RECT  15.469 41.376 15.901 42.312 ;
     RECT  14.963 45.984 16.117 46.008 ;
     RECT  15.589 47.04 16.117 47.448 ;
     RECT  15.689 27.792 16.193 35.352 ;
     RECT  15.901 37.104 16.333 42.312 ;
     RECT  15.689 24.096 16.403 26.76 ;
     RECT  14.963 44.16 16.405 44.952 ;
     RECT  16.117 45.984 16.405 47.448 ;
     RECT  15.901 2.352 16.441 23.112 ;
     RECT  16.403 24.096 16.441 26.664 ;
     RECT  16.441 2.352 16.499 26.664 ;
     RECT  16.333 36.912 16.553 42.312 ;
     RECT  16.193 27.84 16.693 35.352 ;
     RECT  16.553 36.912 16.693 42.264 ;
     RECT  16.405 44.16 16.693 47.448 ;
     RECT  16.693 44.16 16.721 48.216 ;
     RECT  16.721 44.16 16.805 49.032 ;
     RECT  16.499 24.528 16.841 26.664 ;
     RECT  16.499 2.352 16.877 23.448 ;
     RECT  16.805 44.16 16.909 48.984 ;
     RECT  16.877 2.736 17.057 19.368 ;
     RECT  16.909 43.872 17.381 48.984 ;
     RECT  17.057 3.12 17.404 19.368 ;
     RECT  16.841 24.768 17.413 26.664 ;
     RECT  16.693 27.84 17.413 42.264 ;
     RECT  17.381 43.872 17.417 47.88 ;
     RECT  16.877 20.4 17.701 23.448 ;
     RECT  17.701 20.4 17.953 23.736 ;
     RECT  17.413 24.768 17.953 42.264 ;
     RECT  17.404 15.504 18.061 19.368 ;
     RECT  17.953 20.4 18.061 42.264 ;
     RECT  17.417 43.872 18.241 44.184 ;
     RECT  17.417 45.792 18.565 47.88 ;
     RECT  17.404 3.12 18.608 14.472 ;
     RECT  18.061 15.504 18.608 42.264 ;
     RECT  18.241 43.824 18.608 44.184 ;
     RECT  18.565 45.456 18.608 47.88 ;
     RECT  17.381 48.96 18.608 48.984 ;
     RECT  18.608 2.148 18.712 49.692 ;
     RECT  18.712 2.418 18.904 49.422 ;
     RECT  18.904 30.048 18.929 48.984 ;
     RECT  18.904 25.44 18.965 29.016 ;
     RECT  18.904 3.024 19.289 24.264 ;
     RECT  19.289 20.928 19.577 24.264 ;
     RECT  19.289 3.024 19.613 19.656 ;
     RECT  18.965 25.728 19.613 29.016 ;
     RECT  19.577 22.56 19.933 24.264 ;
     RECT  19.613 28.416 20.005 29.016 ;
     RECT  18.929 30.144 20.005 48.984 ;
     RECT  20.005 28.416 20.291 48.984 ;
     RECT  19.933 22.56 20.509 24.36 ;
     RECT  19.577 20.928 20.545 21.48 ;
     RECT  20.509 22.56 20.545 24.408 ;
     RECT  20.545 20.928 20.725 24.408 ;
     RECT  19.613 25.728 20.725 27.192 ;
     RECT  19.613 19.248 20.761 19.656 ;
     RECT  20.725 20.928 20.761 27.192 ;
     RECT  20.291 43.248 20.819 48.984 ;
     RECT  20.761 19.2 20.876 27.192 ;
     RECT  20.291 28.416 20.876 42.024 ;
     RECT  20.876 19.2 20.963 42.024 ;
     RECT  20.819 45.6 21.017 48.984 ;
     RECT  21.017 45.648 21.053 48.984 ;
     RECT  19.613 3.024 21.061 17.928 ;
     RECT  20.963 19.2 21.061 27.384 ;
     RECT  21.053 45.648 21.089 47.88 ;
     RECT  21.061 3.024 21.125 27.384 ;
     RECT  21.125 9.024 21.233 27.384 ;
     RECT  20.963 28.416 21.269 42.024 ;
     RECT  21.125 3.024 21.301 8.04 ;
     RECT  21.301 2.256 21.443 8.04 ;
     RECT  21.233 19.344 21.485 27.192 ;
     RECT  21.053 48.96 21.485 48.984 ;
     RECT  21.485 22.56 21.557 27.192 ;
     RECT  21.443 3.12 21.809 8.04 ;
     RECT  21.089 45.648 21.845 47.448 ;
     RECT  20.819 43.248 22.261 44.184 ;
     RECT  21.269 30.624 22.277 42.024 ;
     RECT  21.809 3.168 22.313 8.04 ;
     RECT  22.261 43.152 22.349 44.184 ;
     RECT  21.269 28.416 22.525 29.592 ;
     RECT  21.233 9.024 22.561 17.928 ;
     RECT  21.485 19.344 22.561 21.048 ;
     RECT  22.561 9.024 22.597 21.048 ;
     RECT  21.557 22.56 22.597 27.144 ;
     RECT  22.597 9.024 22.633 27.336 ;
     RECT  22.525 28.416 22.633 29.64 ;
     RECT  21.845 45.696 22.777 47.448 ;
     RECT  21.949 49.008 22.777 49.032 ;
     RECT  22.313 3.168 22.813 7.752 ;
     RECT  22.633 9.024 22.817 29.64 ;
     RECT  22.817 19.248 22.853 29.64 ;
     RECT  22.813 3.072 22.885 7.752 ;
     RECT  22.853 19.248 22.925 29.592 ;
     RECT  22.925 19.248 23.033 29.544 ;
     RECT  22.349 43.2 23.036 44.184 ;
     RECT  23.036 43.2 23.245 44.472 ;
     RECT  22.885 2.928 23.281 7.752 ;
     RECT  22.277 30.624 23.281 40.728 ;
     RECT  22.277 42 23.281 42.024 ;
     RECT  23.281 30.624 23.317 42.024 ;
     RECT  23.245 43.2 23.317 44.664 ;
     RECT  23.281 2.784 24.008 7.752 ;
     RECT  22.817 9.024 24.008 18.264 ;
     RECT  23.033 19.344 24.008 29.544 ;
     RECT  23.317 30.624 24.008 44.664 ;
     RECT  22.777 45.696 24.008 49.032 ;
     RECT  24.008 2.148 24.112 49.692 ;
     RECT  24.112 2.418 24.304 49.464 ;
     RECT  24.304 3.024 24.437 49.464 ;
     RECT  24.437 44.64 24.467 49.464 ;
     RECT  24.467 44.64 24.509 47.64 ;
     RECT  24.437 3.024 24.545 29.64 ;
     RECT  24.437 30.624 24.581 43.56 ;
     RECT  24.581 33.936 25.049 43.56 ;
     RECT  24.545 3.024 25.405 13.368 ;
     RECT  25.049 42.576 25.445 43.56 ;
     RECT  25.445 42.816 25.477 43.56 ;
     RECT  25.049 33.936 25.697 41.592 ;
     RECT  24.509 44.88 25.717 47.64 ;
     RECT  24.467 48.864 25.717 49.464 ;
     RECT  25.717 44.88 25.763 49.464 ;
     RECT  25.763 44.88 25.765 48.888 ;
     RECT  24.581 30.624 25.837 32.952 ;
     RECT  25.697 33.936 25.837 41.4 ;
     RECT  25.477 42.816 25.945 43.704 ;
     RECT  25.765 44.688 25.945 48.888 ;
     RECT  24.545 14.448 26.017 29.64 ;
     RECT  25.837 30.624 26.017 41.4 ;
     RECT  26.017 14.448 26.057 41.4 ;
     RECT  26.057 14.448 26.099 32.472 ;
     RECT  25.405 2.784 26.197 13.368 ;
     RECT  26.099 14.448 26.197 32.04 ;
     RECT  26.197 2.784 26.201 32.04 ;
     RECT  26.201 2.784 26.237 21.528 ;
     RECT  26.237 2.928 26.243 21.528 ;
     RECT  26.243 2.928 26.381 16.2 ;
     RECT  26.201 22.56 26.381 30.648 ;
     RECT  26.057 33.504 26.525 41.4 ;
     RECT  26.525 33.504 26.669 40.872 ;
     RECT  26.381 22.56 26.813 29.592 ;
     RECT  25.945 42.816 27.173 48.888 ;
     RECT  27.173 42.816 27.205 44.52 ;
     RECT  26.243 17.184 27.209 21.528 ;
     RECT  26.813 22.56 27.209 29.352 ;
     RECT  26.201 31.68 27.313 32.04 ;
     RECT  26.669 33.936 27.389 40.872 ;
     RECT  27.173 45.696 27.389 48.888 ;
     RECT  26.381 30.624 27.421 30.648 ;
     RECT  27.313 31.68 27.421 32.904 ;
     RECT  27.389 33.936 27.425 35.496 ;
     RECT  27.209 20.16 27.461 21.528 ;
     RECT  27.425 33.936 27.497 35.448 ;
     RECT  27.389 36.624 27.533 40.872 ;
     RECT  27.421 30.624 27.601 32.904 ;
     RECT  27.601 30.384 27.637 32.904 ;
     RECT  27.497 33.936 27.637 35.256 ;
     RECT  27.637 30.384 27.641 35.256 ;
     RECT  27.641 34.08 27.677 35.256 ;
     RECT  26.381 2.928 27.749 16.104 ;
     RECT  27.209 22.56 27.821 29.016 ;
     RECT  27.389 45.984 27.853 48.888 ;
     RECT  27.749 14.352 27.889 16.104 ;
     RECT  27.209 17.184 27.889 18.792 ;
     RECT  27.461 20.16 27.929 21.48 ;
     RECT  27.641 30.384 28.033 33.048 ;
     RECT  27.533 37.008 28.177 40.872 ;
     RECT  27.205 42.192 28.177 44.52 ;
     RECT  27.821 22.56 28.217 22.632 ;
     RECT  28.177 37.008 28.217 44.52 ;
     RECT  27.821 23.664 28.321 29.016 ;
     RECT  28.217 42.624 28.429 44.52 ;
     RECT  27.929 20.256 28.597 21.48 ;
     RECT  28.321 23.664 28.604 29.064 ;
     RECT  28.033 30.288 28.604 33.048 ;
     RECT  28.604 23.664 28.645 33.048 ;
     RECT  27.853 45.984 28.645 49.032 ;
     RECT  28.645 23.664 28.681 33.096 ;
     RECT  27.677 34.08 28.681 35.208 ;
     RECT  27.749 2.928 28.753 13.368 ;
     RECT  28.217 37.008 28.825 41.64 ;
     RECT  28.217 22.608 29.041 22.632 ;
     RECT  28.681 23.664 29.041 35.208 ;
     RECT  27.889 14.352 29.077 18.792 ;
     RECT  28.597 20.256 29.077 21.624 ;
     RECT  28.429 42.624 29.077 44.664 ;
     RECT  28.753 2.256 29.113 13.368 ;
     RECT  29.077 14.352 29.113 21.624 ;
     RECT  29.077 42.624 29.149 44.904 ;
     RECT  28.645 45.936 29.149 49.032 ;
     RECT  29.041 22.608 29.185 35.208 ;
     RECT  28.825 36.336 29.185 41.64 ;
     RECT  29.113 2.256 29.408 21.624 ;
     RECT  29.185 22.608 29.408 41.64 ;
     RECT  29.149 42.624 29.408 49.032 ;
     RECT  29.408 2.148 29.512 49.692 ;
     RECT  29.512 2.418 29.704 49.422 ;
     RECT  29.704 2.736 29.843 49.032 ;
     RECT  29.843 2.736 30.341 33.048 ;
     RECT  30.341 2.736 30.413 30.648 ;
     RECT  30.413 2.736 30.701 30.456 ;
     RECT  29.843 34.368 30.701 49.032 ;
     RECT  30.701 44.736 30.729 49.032 ;
     RECT  30.341 31.68 30.841 33.048 ;
     RECT  30.729 44.736 30.844 48.168 ;
     RECT  30.701 20.16 30.845 30.456 ;
     RECT  30.844 44.736 30.845 46.68 ;
     RECT  30.844 47.712 30.917 48.168 ;
     RECT  30.701 2.736 31.061 18.84 ;
     RECT  31.061 3.024 31.277 18.84 ;
     RECT  30.841 31.68 31.389 33.096 ;
     RECT  30.701 34.368 31.389 43.608 ;
     RECT  31.389 31.68 31.417 43.608 ;
     RECT  31.417 30.72 31.501 43.608 ;
     RECT  31.501 31.68 31.619 43.608 ;
     RECT  31.619 34.704 31.637 43.608 ;
     RECT  30.845 20.16 31.669 29.448 ;
     RECT  31.619 31.68 31.709 33.624 ;
     RECT  31.637 42.192 31.741 43.608 ;
     RECT  31.637 34.704 31.961 41.208 ;
     RECT  31.741 42.192 31.993 43.848 ;
     RECT  31.669 19.248 32.065 29.448 ;
     RECT  31.277 3.024 32.209 17.976 ;
     RECT  30.845 45.216 32.209 46.68 ;
     RECT  30.917 47.856 32.209 48.168 ;
     RECT  31.993 42.192 32.285 43.896 ;
     RECT  32.065 19.248 32.425 29.496 ;
     RECT  31.709 31.968 32.749 33.624 ;
     RECT  31.961 34.704 32.749 35.016 ;
     RECT  32.285 42.528 32.857 43.896 ;
     RECT  32.209 45.216 32.857 48.168 ;
     RECT  32.209 2.832 32.893 17.976 ;
     RECT  32.425 19.248 32.893 30.648 ;
     RECT  31.961 36.096 32.893 41.208 ;
     RECT  32.749 31.968 33.037 35.016 ;
     RECT  32.893 36.096 33.037 41.4 ;
     RECT  32.893 2.832 33.149 30.648 ;
     RECT  33.037 31.68 33.205 35.016 ;
     RECT  33.037 36.048 33.205 41.4 ;
     RECT  33.149 3.168 33.221 29.208 ;
     RECT  33.149 30.624 33.253 30.648 ;
     RECT  33.205 31.68 33.253 41.4 ;
     RECT  33.253 30.624 33.469 41.4 ;
     RECT  32.857 42.528 33.469 48.168 ;
     RECT  33.469 30.624 33.577 48.168 ;
     RECT  33.577 30.624 33.973 48.312 ;
     RECT  32.713 49.344 33.973 49.368 ;
     RECT  33.893 0.096 33.976 0.12 ;
     RECT  33.976 0.096 33.977 0.168 ;
     RECT  33.977 0.144 34.093 0.168 ;
     RECT  33.973 30.624 34.225 49.368 ;
     RECT  33.221 3.168 34.729 29.064 ;
     RECT  34.225 30.096 34.729 49.368 ;
     RECT  34.729 3.168 34.808 49.368 ;
     RECT  34.808 2.148 34.912 49.692 ;
     RECT  34.912 2.418 35.104 49.422 ;
     RECT  35.104 44.736 35.363 49.224 ;
     RECT  35.104 16.08 35.597 40.92 ;
     RECT  35.104 2.688 35.993 14.664 ;
     RECT  35.104 41.952 36.133 43.752 ;
     RECT  35.597 21.12 36.173 40.92 ;
     RECT  35.993 2.688 36.227 14.472 ;
     RECT  36.227 2.928 36.245 14.472 ;
     RECT  36.173 21.12 36.245 40.632 ;
     RECT  36.133 41.952 36.349 44.136 ;
     RECT  36.245 33.12 36.389 40.632 ;
     RECT  36.349 41.664 36.421 44.136 ;
     RECT  35.363 45.216 36.421 49.224 ;
     RECT  35.597 16.08 36.485 20.04 ;
     RECT  36.421 41.664 36.515 49.224 ;
     RECT  36.245 3.168 36.533 14.472 ;
     RECT  36.245 21.12 36.533 32.04 ;
     RECT  36.533 21.12 36.641 31.848 ;
     RECT  36.533 14.208 36.713 14.472 ;
     RECT  36.515 45.216 36.713 49.224 ;
     RECT  36.641 21.12 36.749 31.8 ;
     RECT  36.533 3.168 36.821 13.08 ;
     RECT  36.713 14.448 37.033 14.472 ;
     RECT  36.485 15.936 37.033 20.04 ;
     RECT  36.749 21.12 37.289 31.752 ;
     RECT  36.389 33.312 37.393 40.632 ;
     RECT  36.515 41.664 37.393 44.184 ;
     RECT  37.289 30.624 37.397 31.752 ;
     RECT  37.033 14.448 37.573 20.04 ;
     RECT  37.289 21.12 37.573 29.64 ;
     RECT  36.821 3.168 37.753 12.792 ;
     RECT  37.397 31.248 37.753 31.752 ;
     RECT  37.573 14.448 37.789 29.64 ;
     RECT  37.789 13.824 37.793 29.64 ;
     RECT  37.753 31.248 37.861 31.944 ;
     RECT  37.393 33.312 37.861 44.184 ;
     RECT  37.753 2.496 37.933 12.792 ;
     RECT  37.793 13.824 37.933 29.496 ;
     RECT  36.713 45.216 37.973 48.84 ;
     RECT  37.933 2.496 38.009 29.496 ;
     RECT  37.973 45.216 38.225 46.632 ;
     RECT  37.861 31.248 38.329 44.184 ;
     RECT  38.225 45.216 38.329 45.24 ;
     RECT  38.329 31.248 38.333 45.24 ;
     RECT  38.009 2.928 38.513 29.496 ;
     RECT  38.333 32.016 38.531 45.24 ;
     RECT  38.513 2.928 38.549 26.856 ;
     RECT  37.973 47.856 38.801 48.84 ;
     RECT  38.801 48.192 38.833 48.84 ;
     RECT  38.549 2.928 38.873 26.568 ;
     RECT  38.513 27.84 38.945 29.496 ;
     RECT  38.225 46.272 39.085 46.632 ;
     RECT  38.545 30.768 39.229 30.792 ;
     RECT  38.531 41.232 39.301 45.24 ;
     RECT  39.085 46.272 39.301 46.728 ;
     RECT  38.873 26.112 39.517 26.568 ;
     RECT  39.229 30.528 39.517 30.792 ;
     RECT  38.531 32.544 39.517 40.2 ;
     RECT  39.517 26.112 39.553 26.808 ;
     RECT  38.945 27.84 39.553 29.352 ;
     RECT  39.301 41.232 39.553 46.728 ;
     RECT  38.873 2.928 39.769 25.08 ;
     RECT  39.769 2.496 39.877 25.08 ;
     RECT  39.553 26.112 39.877 29.352 ;
     RECT  39.553 41.232 39.925 47.208 ;
     RECT  38.833 48.192 39.925 49.512 ;
     RECT  39.877 2.496 40.057 29.352 ;
     RECT  39.517 30.528 40.057 40.2 ;
     RECT  40.057 2.496 40.208 40.2 ;
     RECT  39.925 41.232 40.208 49.512 ;
     RECT  40.208 2.148 40.312 49.692 ;
     RECT  40.312 2.418 40.504 49.512 ;
     RECT  40.504 2.496 40.601 46.536 ;
     RECT  40.601 26.88 40.745 46.536 ;
     RECT  40.601 2.496 40.889 25.848 ;
     RECT  40.745 29.328 41.105 46.536 ;
     RECT  41.105 29.328 41.177 31.416 ;
     RECT  41.105 32.592 41.393 46.536 ;
     RECT  40.504 47.616 41.429 48.456 ;
     RECT  40.889 2.88 41.645 25.848 ;
     RECT  41.645 3.12 41.681 25.848 ;
     RECT  41.681 14.352 41.701 25.848 ;
     RECT  40.745 26.88 41.701 27.912 ;
     RECT  41.393 32.928 41.753 46.536 ;
     RECT  41.753 32.928 41.897 34.728 ;
     RECT  41.753 35.712 41.897 46.536 ;
     RECT  41.429 47.856 42.037 48.456 ;
     RECT  40.504 49.488 42.037 49.512 ;
     RECT  41.177 29.328 42.073 31.368 ;
     RECT  42.073 29.04 42.145 31.368 ;
     RECT  41.701 14.352 42.149 27.912 ;
     RECT  42.037 47.856 42.185 49.512 ;
     RECT  41.897 35.712 42.437 40.248 ;
     RECT  42.145 29.04 42.577 31.416 ;
     RECT  41.897 32.928 42.577 33.096 ;
     RECT  41.897 41.232 42.613 46.536 ;
     RECT  42.185 47.856 42.613 49.032 ;
     RECT  42.149 18.72 42.685 27.912 ;
     RECT  42.577 29.04 42.685 33.096 ;
     RECT  41.681 3.12 42.757 13.08 ;
     RECT  42.685 18.72 42.761 33.096 ;
     RECT  42.149 14.352 42.833 17.64 ;
     RECT  42.757 3.12 42.865 13.224 ;
     RECT  42.437 39.744 42.865 40.248 ;
     RECT  42.613 41.232 42.865 49.032 ;
     RECT  42.865 39.744 42.905 49.032 ;
     RECT  42.905 39.792 42.941 49.032 ;
     RECT  42.865 2.832 43.045 13.224 ;
     RECT  43.045 2.832 43.333 13.272 ;
     RECT  42.833 14.352 43.333 17.496 ;
     RECT  42.941 39.792 43.337 46.536 ;
     RECT  42.761 26.784 43.369 33.096 ;
     RECT  41.897 34.08 43.369 34.728 ;
     RECT  43.369 26.784 43.417 34.728 ;
     RECT  42.761 18.72 43.525 25.8 ;
     RECT  43.417 26.976 43.657 34.728 ;
     RECT  42.437 35.712 43.657 38.76 ;
     RECT  43.337 40.32 43.733 46.536 ;
     RECT  43.333 2.832 43.837 17.496 ;
     RECT  43.525 18.624 43.837 25.8 ;
     RECT  43.837 2.832 43.913 25.8 ;
     RECT  43.913 2.928 43.955 25.8 ;
     RECT  43.955 13.104 44.021 25.8 ;
     RECT  43.733 41.472 44.089 46.536 ;
     RECT  42.941 47.664 44.089 49.032 ;
     RECT  43.657 26.976 44.233 38.76 ;
     RECT  44.021 13.104 44.237 25.032 ;
     RECT  44.233 26.976 44.309 39.336 ;
     RECT  44.309 31.92 44.341 39.336 ;
     RECT  43.733 40.32 44.341 40.44 ;
     RECT  44.309 26.976 44.444 30.696 ;
     RECT  44.089 41.472 44.453 49.032 ;
     RECT  44.341 31.92 44.561 40.44 ;
     RECT  44.237 13.248 45.025 25.032 ;
     RECT  45.025 13.248 45.061 25.8 ;
     RECT  44.444 26.784 45.061 30.696 ;
     RECT  44.561 33.072 45.061 40.44 ;
     RECT  44.453 41.472 45.061 48.744 ;
     RECT  43.955 2.928 45.205 11.976 ;
     RECT  45.061 13.248 45.313 30.696 ;
     RECT  44.561 31.92 45.313 31.944 ;
     RECT  45.205 2.928 45.457 12.072 ;
     RECT  45.313 13.248 45.457 31.944 ;
     RECT  45.457 2.928 45.608 31.944 ;
     RECT  45.061 33.072 45.608 48.744 ;
     RECT  45.608 2.148 45.712 49.692 ;
     RECT  45.712 2.418 45.904 49.422 ;
     RECT  45.904 26.832 45.965 48.744 ;
     RECT  45.904 3.072 46.001 19.32 ;
     RECT  45.965 26.832 46.001 31.464 ;
     RECT  46.001 3.072 46.019 10.392 ;
     RECT  45.965 32.736 46.211 48.744 ;
     RECT  46.211 32.736 46.217 38.52 ;
     RECT  46.001 11.376 46.253 19.32 ;
     RECT  46.001 26.832 46.253 27.096 ;
     RECT  46.001 28.176 46.505 31.464 ;
     RECT  46.505 29.136 46.685 31.464 ;
     RECT  46.217 34.08 46.721 38.52 ;
     RECT  45.904 20.352 46.757 23.352 ;
     RECT  46.211 39.6 46.757 48.744 ;
     RECT  46.253 11.376 46.793 15.048 ;
     RECT  46.685 29.136 46.829 30.072 ;
     RECT  46.757 39.6 46.829 46.968 ;
     RECT  46.757 47.952 46.865 48.744 ;
     RECT  46.829 41.088 46.901 46.968 ;
     RECT  46.793 11.376 46.937 13.464 ;
     RECT  46.685 31.44 46.937 31.464 ;
     RECT  46.019 5.712 46.969 10.392 ;
     RECT  46.937 11.376 46.969 13.176 ;
     RECT  46.865 48.24 47.009 48.744 ;
     RECT  46.969 5.712 47.036 13.176 ;
     RECT  47.009 48.432 47.045 48.744 ;
     RECT  46.217 32.736 47.077 32.904 ;
     RECT  47.036 5.616 47.123 13.176 ;
     RECT  47.123 5.712 47.153 13.176 ;
     RECT  46.721 36.912 47.153 38.52 ;
     RECT  47.077 32.592 47.185 32.904 ;
     RECT  46.253 26.832 47.221 27.048 ;
     RECT  47.153 8.256 47.261 13.176 ;
     RECT  45.904 24.384 47.293 25.8 ;
     RECT  47.221 26.832 47.293 27.336 ;
     RECT  47.045 48.72 47.293 48.744 ;
     RECT  46.253 16.08 47.317 19.32 ;
     RECT  46.757 20.352 47.317 20.424 ;
     RECT  46.757 21.456 47.329 23.352 ;
     RECT  47.293 24.384 47.329 27.336 ;
     RECT  47.153 37.056 47.369 38.52 ;
     RECT  47.185 32.592 47.401 33.096 ;
     RECT  46.721 34.08 47.401 35.928 ;
     RECT  47.401 32.544 47.441 35.928 ;
     RECT  46.901 41.088 47.441 46.872 ;
     RECT  47.441 32.544 47.459 35.688 ;
     RECT  47.329 21.456 47.473 27.336 ;
     RECT  47.317 16.08 47.549 20.424 ;
     RECT  47.441 44.16 47.549 46.872 ;
     RECT  47.441 41.088 47.621 43.128 ;
     RECT  46.829 29.904 47.653 30.072 ;
     RECT  47.653 29.904 47.801 30.264 ;
     RECT  47.473 21.456 47.833 27.432 ;
     RECT  47.725 28.512 47.833 28.536 ;
     RECT  47.369 37.104 47.833 38.52 ;
     RECT  46.829 39.6 47.833 40.056 ;
     RECT  47.549 16.08 47.893 19.32 ;
     RECT  47.833 37.104 47.948 40.056 ;
     RECT  47.621 41.088 47.948 43.032 ;
     RECT  47.833 21.456 47.977 28.536 ;
     RECT  47.948 37.104 48.035 43.032 ;
     RECT  46.019 3.072 48.181 4.488 ;
     RECT  48.181 2.544 48.193 4.488 ;
     RECT  47.549 20.304 48.229 20.424 ;
     RECT  47.977 21.456 48.229 29.112 ;
     RECT  46.793 14.448 48.265 15.048 ;
     RECT  47.459 32.544 48.265 35.544 ;
     RECT  47.293 48.72 48.301 49.176 ;
     RECT  48.301 48.432 48.341 49.176 ;
     RECT  47.261 8.256 48.373 12.792 ;
     RECT  48.265 13.824 48.373 15.048 ;
     RECT  48.265 31.68 48.409 35.544 ;
     RECT  48.035 37.104 48.419 39.624 ;
     RECT  48.419 37.104 48.46 39.288 ;
     RECT  48.409 31.488 48.476 35.544 ;
     RECT  48.46 37.104 48.476 39.24 ;
     RECT  47.801 30.24 48.481 30.264 ;
     RECT  48.476 31.488 48.481 39.24 ;
     RECT  48.193 2.256 48.553 4.488 ;
     RECT  47.153 5.712 48.553 6.84 ;
     RECT  48.373 8.256 48.553 15.048 ;
     RECT  47.549 44.16 48.553 46.728 ;
     RECT  48.481 30.24 48.563 39.24 ;
     RECT  48.553 44.16 48.593 47.208 ;
     RECT  48.035 41.136 48.697 43.032 ;
     RECT  48.553 5.712 48.805 15.048 ;
     RECT  48.553 2.256 48.917 4.536 ;
     RECT  48.229 20.304 48.949 29.112 ;
     RECT  48.563 30.24 48.949 35.544 ;
     RECT  48.805 5.568 48.985 15.048 ;
     RECT  47.893 16.032 48.985 19.32 ;
     RECT  48.949 20.304 48.995 35.544 ;
     RECT  48.985 5.568 49.021 19.32 ;
     RECT  48.995 20.304 49.021 29.832 ;
     RECT  48.593 45.408 49.021 47.208 ;
     RECT  48.341 48.432 49.021 48.552 ;
     RECT  49.021 45.408 49.169 48.552 ;
     RECT  48.697 41.136 49.201 43.08 ;
     RECT  48.917 2.976 49.417 4.536 ;
     RECT  49.021 5.568 49.417 29.832 ;
     RECT  49.417 2.976 49.565 29.832 ;
     RECT  48.593 44.16 49.597 44.424 ;
     RECT  49.169 45.408 49.597 46.728 ;
     RECT  49.169 47.904 49.669 48.552 ;
     RECT  49.565 2.976 49.745 24.984 ;
     RECT  48.563 36.72 49.777 39.24 ;
     RECT  49.669 47.904 49.781 49.08 ;
     RECT  48.995 31.104 50.029 35.544 ;
     RECT  50.029 30.96 50.065 35.544 ;
     RECT  49.777 36.576 50.065 39.24 ;
     RECT  49.201 41.136 50.101 43.128 ;
     RECT  49.565 26.256 50.137 29.832 ;
     RECT  50.065 30.96 50.137 39.24 ;
     RECT  50.101 40.56 50.173 43.128 ;
     RECT  49.597 44.16 50.173 46.728 ;
     RECT  50.173 40.56 50.317 46.728 ;
     RECT  49.781 47.904 50.317 49.032 ;
     RECT  50.137 26.256 50.353 39.24 ;
     RECT  50.317 40.56 50.353 49.032 ;
     RECT  50.353 26.256 50.533 49.032 ;
     RECT  50.533 26.064 50.869 49.032 ;
     RECT  49.745 2.976 51.008 13.176 ;
     RECT  49.745 14.448 51.008 24.984 ;
     RECT  50.869 26.016 51.008 49.032 ;
     RECT  51.008 2.148 51.112 49.692 ;
     RECT  51.112 2.418 51.304 49.422 ;
     RECT  51.304 33.024 51.473 48.504 ;
     RECT  51.473 33.024 51.581 44.184 ;
     RECT  51.304 2.736 51.725 23.352 ;
     RECT  51.581 33.552 51.869 44.184 ;
     RECT  51.473 45.168 51.869 48.504 ;
     RECT  51.869 37.008 51.905 44.184 ;
     RECT  51.304 30.864 51.941 32.04 ;
     RECT  51.869 33.552 51.941 36.024 ;
     RECT  51.905 37.008 51.941 41.064 ;
     RECT  51.725 2.736 51.977 18.264 ;
     RECT  51.725 19.488 51.977 23.352 ;
     RECT  51.977 2.736 52.049 18.12 ;
     RECT  51.977 19.488 52.085 20.376 ;
     RECT  51.941 37.008 52.085 39.624 ;
     RECT  51.977 21.456 52.121 23.352 ;
     RECT  51.869 45.648 52.229 48.504 ;
     RECT  52.229 47.904 52.333 48.504 ;
     RECT  51.304 26.352 52.337 29.304 ;
     RECT  52.337 27.12 52.405 29.304 ;
     RECT  51.304 24.384 52.441 25.08 ;
     RECT  52.229 45.648 52.481 46.824 ;
     RECT  52.085 37.104 52.697 39.624 ;
     RECT  52.049 4.272 52.739 18.12 ;
     RECT  52.739 4.464 52.769 18.12 ;
     RECT  52.405 27.12 52.837 29.784 ;
     RECT  51.941 30.864 52.837 31.704 ;
     RECT  52.333 47.904 53.027 49.128 ;
     RECT  52.121 21.504 53.029 23.352 ;
     RECT  52.441 24.384 53.029 26.136 ;
     RECT  51.941 33.552 53.053 34.632 ;
     RECT  51.941 35.904 53.053 36.024 ;
     RECT  52.049 2.736 53.093 2.76 ;
     RECT  53.027 47.904 53.093 49.032 ;
     RECT  52.697 37.104 53.161 39.048 ;
     RECT  52.837 27.12 53.165 31.704 ;
     RECT  52.769 4.896 53.197 18.12 ;
     RECT  53.161 37.056 53.201 39.048 ;
     RECT  53.165 31.632 53.233 31.704 ;
     RECT  52.085 19.488 53.305 20.28 ;
     RECT  53.029 21.504 53.305 26.136 ;
     RECT  53.165 27.12 53.305 30.312 ;
     RECT  51.941 40.656 53.305 41.064 ;
     RECT  51.905 42.24 53.305 44.184 ;
     RECT  53.305 40.656 53.341 44.184 ;
     RECT  53.197 4.896 53.365 18.264 ;
     RECT  53.305 19.344 53.365 20.28 ;
     RECT  53.053 33.552 53.413 36.024 ;
     RECT  53.201 37.056 53.413 37.416 ;
     RECT  53.201 38.496 53.489 38.904 ;
     RECT  53.413 33.552 53.525 37.416 ;
     RECT  53.341 40.272 53.557 44.184 ;
     RECT  53.365 4.896 53.593 20.28 ;
     RECT  53.305 21.504 53.593 30.312 ;
     RECT  53.525 33.552 53.597 35.208 ;
     RECT  53.233 31.632 53.633 32.232 ;
     RECT  53.593 4.896 53.669 30.312 ;
     RECT  53.597 33.552 53.701 34.536 ;
     RECT  53.093 48.144 53.777 49.032 ;
     RECT  53.777 48.144 53.957 48.936 ;
     RECT  53.701 33.072 53.993 34.536 ;
     RECT  53.557 40.272 54.097 44.376 ;
     RECT  53.633 31.632 54.277 31.704 ;
     RECT  53.669 4.896 54.349 12.024 ;
     RECT  52.481 45.84 54.349 46.776 ;
     RECT  53.669 14.256 54.385 30.312 ;
     RECT  54.277 31.296 54.385 31.704 ;
     RECT  54.349 45.696 54.385 46.776 ;
     RECT  54.097 39.888 54.389 44.376 ;
     RECT  54.389 40.272 54.457 44.376 ;
     RECT  54.385 45.6 54.457 46.776 ;
     RECT  53.489 38.496 54.467 38.856 ;
     RECT  54.385 14.256 54.497 31.704 ;
     RECT  53.525 36.336 54.515 37.416 ;
     RECT  54.497 21.12 54.605 31.704 ;
     RECT  54.457 40.272 54.637 46.776 ;
     RECT  54.605 23.568 54.641 31.704 ;
     RECT  54.349 4.704 54.709 12.024 ;
     RECT  53.669 13.2 54.749 13.224 ;
     RECT  54.637 40.272 54.749 47.688 ;
     RECT  54.641 28.608 54.781 31.704 ;
     RECT  53.993 33.072 54.781 34.44 ;
     RECT  54.749 40.272 54.793 47.592 ;
     RECT  53.957 48.912 54.857 48.936 ;
     RECT  53.305 2.784 54.925 2.808 ;
     RECT  54.709 4.512 54.925 12.024 ;
     RECT  54.925 2.784 54.965 3.432 ;
     RECT  54.793 40.272 54.965 47.064 ;
     RECT  54.925 4.512 55.037 12.552 ;
     RECT  54.781 28.608 55.069 34.44 ;
     RECT  54.467 38.64 55.109 38.856 ;
     RECT  54.515 36.336 55.325 37.368 ;
     RECT  55.069 28.608 55.331 35.352 ;
     RECT  54.965 40.368 55.361 47.064 ;
     RECT  54.605 21.12 55.397 22.104 ;
     RECT  55.325 37.344 55.628 37.368 ;
     RECT  55.109 38.64 55.628 38.808 ;
     RECT  55.397 21.216 55.645 22.104 ;
     RECT  54.641 23.568 55.645 27.624 ;
     RECT  55.037 4.656 55.825 12.552 ;
     RECT  54.965 3.408 55.897 3.432 ;
     RECT  55.331 28.704 56.005 35.352 ;
     RECT  55.325 36.336 56.005 36.36 ;
     RECT  55.361 44.64 56.329 47.064 ;
     RECT  55.645 21.216 56.401 27.624 ;
     RECT  56.204 2.256 56.408 2.28 ;
     RECT  55.897 3.408 56.408 3.624 ;
     RECT  55.825 4.656 56.408 12.84 ;
     RECT  54.497 14.256 56.408 19.944 ;
     RECT  56.401 21.168 56.408 27.624 ;
     RECT  56.005 28.704 56.408 36.36 ;
     RECT  55.628 37.344 56.408 38.808 ;
     RECT  55.361 40.368 56.408 43.32 ;
     RECT  56.329 44.448 56.408 47.064 ;
     RECT  56.408 2.148 56.512 49.692 ;
     RECT  56.512 2.418 56.704 49.56 ;
     RECT  56.704 2.832 56.765 3.624 ;
     RECT  56.704 7.392 56.819 29.928 ;
     RECT  56.293 50.736 57.01 50.76 ;
     RECT  57.01 50.736 57.011 50.808 ;
     RECT  56.819 21.168 57.017 29.928 ;
     RECT  57.011 50.784 57.061 50.808 ;
     RECT  56.704 30.912 57.089 36.072 ;
     RECT  56.704 40.368 57.089 49.56 ;
     RECT  57.017 26.832 57.125 29.928 ;
     RECT  57.089 30.912 57.161 31.704 ;
     RECT  57.089 33.12 57.161 36.072 ;
     RECT  57.125 27.216 57.299 29.928 ;
     RECT  57.089 40.56 57.299 49.56 ;
     RECT  57.299 27.408 57.34 29.928 ;
     RECT  57.34 29.28 57.449 29.928 ;
     RECT  57.061 50.784 57.491 51.72 ;
     RECT  56.765 2.832 57.557 3.432 ;
     RECT  57.34 27.408 57.557 27.864 ;
     RECT  57.299 40.56 57.665 48.456 ;
     RECT  57.299 49.536 57.683 49.56 ;
     RECT  56.704 4.704 57.697 6.36 ;
     RECT  56.819 7.392 57.697 19.896 ;
     RECT  57.449 29.568 57.733 29.928 ;
     RECT  57.161 30.912 57.733 31.368 ;
     RECT  57.557 2.832 57.773 3.096 ;
     RECT  57.697 4.704 57.805 19.896 ;
     RECT  57.161 35.328 57.913 36.072 ;
     RECT  56.704 37.056 57.913 37.368 ;
     RECT  57.913 35.328 57.949 37.368 ;
     RECT  56.704 38.544 57.949 39.288 ;
     RECT  57.557 27.456 57.953 27.864 ;
     RECT  57.665 43.44 57.971 48.456 ;
     RECT  57.805 4.704 58.057 20.184 ;
     RECT  57.017 21.168 58.057 25.32 ;
     RECT  57.949 35.328 58.129 39.288 ;
     RECT  57.665 40.56 58.129 42.072 ;
     RECT  57.773 3.072 58.241 3.096 ;
     RECT  57.161 33.12 58.273 34.104 ;
     RECT  58.129 35.328 58.273 42.072 ;
     RECT  58.057 4.704 58.277 25.32 ;
     RECT  58.273 33.12 58.277 42.072 ;
     RECT  58.277 22.752 58.313 25.32 ;
     RECT  58.277 33.12 58.345 38.568 ;
     RECT  58.313 23.328 58.547 25.32 ;
     RECT  58.277 4.704 58.549 21.672 ;
     RECT  57.953 27.84 58.597 27.864 ;
     RECT  57.733 29.568 58.597 31.368 ;
     RECT  58.549 4.56 58.636 21.672 ;
     RECT  57.971 43.44 58.669 46.2 ;
     RECT  58.636 6.048 58.709 21.672 ;
     RECT  58.597 27.84 58.709 31.368 ;
     RECT  57.491 51.648 58.709 51.72 ;
     RECT  58.709 6.048 58.745 17.784 ;
     RECT  58.345 32.592 58.745 38.568 ;
     RECT  57.971 47.472 58.789 48.456 ;
     RECT  58.277 39.84 58.813 42.072 ;
     RECT  58.669 43.344 58.813 46.2 ;
     RECT  58.789 47.472 58.885 49.032 ;
     RECT  58.709 29.088 58.889 31.368 ;
     RECT  58.547 24.864 58.925 25.32 ;
     RECT  58.709 27.84 58.925 27.864 ;
     RECT  58.709 51.648 59.219 51.672 ;
     RECT  58.709 19.344 59.249 21.672 ;
     RECT  58.885 47.472 59.249 49.56 ;
     RECT  58.745 34.752 59.267 38.568 ;
     RECT  58.813 39.84 59.267 46.2 ;
     RECT  59.249 49.536 59.285 49.56 ;
     RECT  59.267 40.992 59.317 46.2 ;
     RECT  59.249 47.472 59.317 48.504 ;
     RECT  58.889 30.192 59.321 31.368 ;
     RECT  59.321 31.296 59.357 31.368 ;
     RECT  59.267 34.752 59.357 34.776 ;
     RECT  59.321 30.192 59.393 30.216 ;
     RECT  59.267 36 59.465 38.568 ;
     RECT  59.317 40.992 59.465 48.504 ;
     RECT  59.465 43.584 59.501 48.504 ;
     RECT  59.501 46.224 59.507 48.504 ;
     RECT  59.465 36 59.537 36.6 ;
     RECT  58.921 2.256 59.569 2.28 ;
     RECT  58.745 6.144 59.573 17.784 ;
     RECT  59.465 40.992 59.573 42.6 ;
     RECT  58.636 4.56 59.605 5.016 ;
     RECT  59.357 31.344 59.605 31.368 ;
     RECT  58.745 32.592 59.605 33.384 ;
     RECT  59.573 9.024 59.609 17.784 ;
     RECT  59.605 31.344 59.645 33.384 ;
     RECT  59.267 39.84 59.645 39.864 ;
     RECT  59.605 3.744 59.677 5.016 ;
     RECT  59.573 6.144 59.681 7.992 ;
     RECT  59.609 16.08 59.681 17.784 ;
     RECT  59.249 19.344 59.681 20.52 ;
     RECT  58.547 23.328 59.701 23.832 ;
     RECT  58.925 24.864 59.701 25.176 ;
     RECT  59.677 3.744 59.717 5.112 ;
     RECT  59.507 46.224 59.717 46.728 ;
     RECT  59.717 4.992 59.789 5.112 ;
     RECT  59.569 2.256 59.797 2.376 ;
     RECT  59.717 3.744 59.797 3.768 ;
     RECT  59.609 9.024 59.825 15 ;
     RECT  59.681 7.056 59.897 7.992 ;
     RECT  59.681 16.128 59.969 17.784 ;
     RECT  59.249 21.648 60.001 21.672 ;
     RECT  59.701 22.704 60.001 25.176 ;
     RECT  59.645 31.488 60.005 33.384 ;
     RECT  59.785 27.024 60.073 27.048 ;
     RECT  59.797 2.256 60.113 3.768 ;
     RECT  60.073 27.024 60.133 27.96 ;
     RECT  60.001 21.648 60.181 25.176 ;
     RECT  60.133 26.16 60.181 27.96 ;
     RECT  60.181 21.648 60.22 27.96 ;
     RECT  59.681 19.536 60.221 20.52 ;
     RECT  59.501 43.584 60.293 45.24 ;
     RECT  60.113 2.256 60.329 2.952 ;
     RECT  60.329 2.256 60.365 2.856 ;
     RECT  59.465 37.872 60.397 38.568 ;
     RECT  59.825 9.024 60.401 14.664 ;
     RECT  60.401 9.024 60.473 11.784 ;
     RECT  60.401 12.864 60.509 14.664 ;
     RECT  60.293 43.584 60.545 43.752 ;
     RECT  60.545 43.584 60.617 43.704 ;
     RECT  60.325 29.04 60.653 29.064 ;
     RECT  59.573 40.992 60.653 42.264 ;
     RECT  60.653 40.992 60.689 41.016 ;
     RECT  59.717 46.224 60.721 46.248 ;
     RECT  59.897 7.056 60.725 7.416 ;
     RECT  60.22 21.648 60.725 25.464 ;
     RECT  60.22 26.736 60.761 27.96 ;
     RECT  60.397 37.872 60.761 39.288 ;
     RECT  60.725 21.648 60.793 25.272 ;
     RECT  59.537 36.48 60.793 36.6 ;
     RECT  60.253 35.328 60.797 35.352 ;
     RECT  59.969 16.128 60.833 17.64 ;
     RECT  60.721 46.224 60.833 46.776 ;
     RECT  59.507 47.808 60.833 48.504 ;
     RECT  60.509 12.912 60.901 14.664 ;
     RECT  60.293 44.736 60.997 45.24 ;
     RECT  60.005 31.488 61.196 32.952 ;
     RECT  60.397 34.176 61.196 34.2 ;
     RECT  60.761 38.112 61.225 39.288 ;
     RECT  60.793 21.504 61.621 25.272 ;
     RECT  60.901 12.912 61.657 15.336 ;
     RECT  60.829 6.816 61.765 6.84 ;
     RECT  60.365 2.832 61.808 2.856 ;
     RECT  59.789 5.088 61.808 5.112 ;
     RECT  61.765 6.816 61.808 7.128 ;
     RECT  60.473 9.024 61.808 10.728 ;
     RECT  60.473 11.76 61.808 11.784 ;
     RECT  61.657 12.864 61.808 15.336 ;
     RECT  60.833 16.32 61.808 17.64 ;
     RECT  60.221 19.536 61.808 19.752 ;
     RECT  61.621 21.168 61.808 25.272 ;
     RECT  60.761 26.736 61.808 26.76 ;
     RECT  60.761 27.936 61.808 27.96 ;
     RECT  61.196 31.488 61.808 34.2 ;
     RECT  60.793 36.48 61.808 37.128 ;
     RECT  61.225 38.112 61.808 39.336 ;
     RECT  60.937 40.8 61.808 40.824 ;
     RECT  60.653 42.24 61.808 42.264 ;
     RECT  60.617 43.584 61.808 43.608 ;
     RECT  60.997 44.736 61.808 45.624 ;
     RECT  60.833 46.752 61.808 46.776 ;
     RECT  60.833 47.808 61.808 47.832 ;
     RECT  61.808 2.148 61.912 49.692 ;
     RECT  61.912 2.418 62.104 49.422 ;
     RECT  62.104 16.368 62.273 16.392 ;
     RECT  62.104 9.024 62.885 15.336 ;
     RECT  62.885 9.936 63.601 15.336 ;
     RECT  63.601 9.936 64.573 15.816 ;
     RECT  64.573 9.936 64.716 9.96 ;
     RECT  64.573 9.96 64.764 10.032 ;
     RECT  64.573 10.032 64.716 10.056 ;
     RECT  64.573 10.056 64.764 10.128 ;
     RECT  64.573 10.128 64.716 10.152 ;
     RECT  64.573 10.152 64.764 10.224 ;
     RECT  64.573 10.224 64.716 10.248 ;
     RECT  64.573 10.248 64.764 10.32 ;
     RECT  64.573 10.32 64.716 10.344 ;
     RECT  64.573 10.344 64.764 10.416 ;
     RECT  64.573 10.416 64.716 10.44 ;
     RECT  64.573 10.44 64.764 10.512 ;
     RECT  64.573 10.512 64.716 10.536 ;
     RECT  64.573 10.536 64.764 10.608 ;
     RECT  64.573 10.608 64.716 10.632 ;
     RECT  64.573 10.632 64.764 10.704 ;
     RECT  64.573 10.704 64.716 10.728 ;
     RECT  64.573 10.728 64.764 10.8 ;
     RECT  64.573 10.8 64.716 10.824 ;
     RECT  64.573 10.824 64.764 10.896 ;
     RECT  64.573 10.896 64.716 10.92 ;
     RECT  64.573 10.92 64.764 10.992 ;
     RECT  64.573 10.992 64.716 11.016 ;
     RECT  64.573 11.016 64.764 11.088 ;
     RECT  64.573 11.088 64.716 11.112 ;
     RECT  64.573 11.112 64.764 11.184 ;
     RECT  64.573 11.184 64.716 11.208 ;
     RECT  64.573 11.208 64.764 11.28 ;
     RECT  64.573 11.28 64.716 11.304 ;
     RECT  64.573 11.304 64.764 11.376 ;
     RECT  64.573 11.376 64.716 11.4 ;
     RECT  64.573 11.4 64.764 11.472 ;
     RECT  64.573 11.472 64.716 11.496 ;
     RECT  64.573 11.496 64.764 11.568 ;
     RECT  64.573 11.568 64.716 11.592 ;
     RECT  64.573 11.592 64.764 11.664 ;
     RECT  64.573 11.664 64.716 11.688 ;
     RECT  64.573 11.688 64.764 11.76 ;
     RECT  64.573 11.76 64.716 11.784 ;
     RECT  64.573 11.784 64.764 11.856 ;
     RECT  64.573 11.856 64.716 11.88 ;
     RECT  64.573 11.88 64.764 11.952 ;
     RECT  64.573 11.952 64.716 11.976 ;
     RECT  64.573 11.976 64.764 12.048 ;
     RECT  64.573 12.048 64.716 12.072 ;
     RECT  64.573 12.072 64.764 12.144 ;
     RECT  64.573 12.144 64.716 12.168 ;
     RECT  64.573 12.168 64.764 12.24 ;
     RECT  64.573 12.24 64.716 12.264 ;
     RECT  64.573 12.264 64.764 12.336 ;
     RECT  64.573 12.336 64.716 12.36 ;
     RECT  64.573 12.36 64.764 12.432 ;
     RECT  64.573 12.432 64.716 12.456 ;
     RECT  64.573 12.456 64.764 12.528 ;
     RECT  64.573 12.528 64.716 12.552 ;
     RECT  64.573 12.552 64.764 12.624 ;
     RECT  64.573 12.624 64.716 12.648 ;
     RECT  64.573 12.648 64.764 12.72 ;
     RECT  64.573 12.72 64.716 12.744 ;
     RECT  64.573 12.744 64.764 12.816 ;
     RECT  64.573 12.816 64.716 12.84 ;
     RECT  64.573 12.84 64.764 12.912 ;
     RECT  64.573 12.912 64.716 12.936 ;
     RECT  64.573 12.936 64.764 13.008 ;
     RECT  64.573 13.008 64.716 13.032 ;
     RECT  64.573 13.032 64.764 13.104 ;
     RECT  64.573 13.104 64.716 13.128 ;
     RECT  64.573 13.128 64.764 13.2 ;
     RECT  64.573 13.2 64.716 13.224 ;
     RECT  64.573 13.224 64.764 13.296 ;
     RECT  64.573 13.296 64.716 13.32 ;
     RECT  64.573 13.32 64.764 13.392 ;
     RECT  64.573 13.392 64.716 13.416 ;
     RECT  64.573 13.416 64.764 13.488 ;
     RECT  64.573 13.488 64.716 13.512 ;
     RECT  64.573 13.512 64.764 13.584 ;
     RECT  64.573 13.584 64.716 13.608 ;
     RECT  64.573 13.608 64.764 13.68 ;
     RECT  64.573 13.68 64.716 13.704 ;
     RECT  64.573 13.704 64.764 13.776 ;
     RECT  64.573 13.776 64.716 13.8 ;
     RECT  64.573 13.8 64.764 13.872 ;
     RECT  64.573 13.872 64.716 13.896 ;
     RECT  64.573 13.896 64.764 13.968 ;
     RECT  64.573 13.968 64.716 13.992 ;
     RECT  64.573 13.992 64.764 14.064 ;
     RECT  64.573 14.064 64.716 14.088 ;
     RECT  64.573 14.088 64.764 14.16 ;
     RECT  64.573 14.16 64.716 14.184 ;
     RECT  64.573 14.184 64.764 14.256 ;
     RECT  64.573 14.256 64.716 14.28 ;
     RECT  64.573 14.28 64.764 14.352 ;
     RECT  64.573 14.352 64.716 14.376 ;
     RECT  64.573 14.376 64.764 14.448 ;
     RECT  64.573 14.448 64.716 14.472 ;
     RECT  64.573 14.472 64.764 14.544 ;
     RECT  64.573 14.544 64.716 14.568 ;
     RECT  64.573 14.568 64.764 14.64 ;
     RECT  64.573 14.64 64.716 14.664 ;
     RECT  64.573 14.664 64.764 14.736 ;
     RECT  64.573 14.736 64.716 14.76 ;
     RECT  64.573 14.76 64.764 14.832 ;
     RECT  64.573 14.832 64.716 14.856 ;
     RECT  64.573 14.856 64.764 14.928 ;
     RECT  64.573 14.928 64.716 14.952 ;
     RECT  64.573 14.952 64.764 15.024 ;
     RECT  64.573 15.024 64.716 15.048 ;
     RECT  64.573 15.048 64.764 15.12 ;
     RECT  64.573 15.12 64.716 15.144 ;
     RECT  64.573 15.144 64.764 15.216 ;
     RECT  64.573 15.216 64.716 15.24 ;
     RECT  64.573 15.24 64.764 15.312 ;
     RECT  64.573 15.312 64.716 15.336 ;
     RECT  64.573 15.336 64.764 15.408 ;
     RECT  64.573 15.408 64.716 15.432 ;
     RECT  64.573 15.432 64.764 15.504 ;
     RECT  64.573 15.504 64.716 15.528 ;
     RECT  64.573 15.528 64.764 15.6 ;
     RECT  64.573 15.6 64.716 15.624 ;
     RECT  64.573 15.624 64.764 15.696 ;
     RECT  64.573 15.696 64.716 15.72 ;
     RECT  64.573 15.72 64.764 15.792 ;
     RECT  64.573 15.792 64.716 15.816 ;
     RECT  64.573 15.816 64.764 15.888 ;
     RECT  64.573 15.888 64.716 15.912 ;
     RECT  64.573 15.912 64.764 15.984 ;
     RECT  64.573 15.984 64.716 16.008 ;
    LAYER M5 ;
     RECT  33.96 0.016 34.032 0.084 ;
     RECT  33.936 0.084 34.056 0.131 ;
     RECT  34.032 0.131 34.056 0.179 ;
     RECT  2.4 2.137 2.52 2.151 ;
     RECT  7.8 2.137 7.92 2.151 ;
     RECT  13.2 2.137 13.32 2.151 ;
     RECT  18.6 2.137 18.72 2.151 ;
     RECT  24 2.137 24.12 2.151 ;
     RECT  29.4 2.137 29.52 2.151 ;
     RECT  34.8 2.137 34.92 2.151 ;
     RECT  40.2 2.137 40.32 2.151 ;
     RECT  45.6 2.137 45.72 2.151 ;
     RECT  51 2.137 51.12 2.151 ;
     RECT  56.4 2.137 56.52 2.151 ;
     RECT  61.8 2.137 61.92 2.151 ;
     RECT  29.4 2.151 29.712 2.245 ;
     RECT  56.4 2.151 56.712 2.245 ;
     RECT  40.2 2.151 40.512 2.485 ;
     RECT  7.8 2.151 8.112 2.869 ;
     RECT  10.608 2.245 10.632 2.963 ;
     RECT  36.192 2.677 36.216 2.963 ;
     RECT  59.808 2.245 59.832 2.963 ;
     RECT  24 2.151 24.312 3.397 ;
     RECT  48.192 2.533 48.216 3.443 ;
     RECT  56.256 2.245 56.712 3.443 ;
     RECT  6.144 2.869 8.112 3.539 ;
     RECT  45.6 2.151 45.912 3.829 ;
     RECT  28.8 2.245 29.712 3.877 ;
     RECT  6.864 3.539 8.112 3.925 ;
     RECT  23.136 3.397 24.312 4.115 ;
     RECT  39.984 2.485 40.512 4.115 ;
     RECT  42.48 3.397 42.504 4.403 ;
     RECT  21.408 2.245 21.432 4.691 ;
     RECT  6.864 3.925 8.568 4.837 ;
     RECT  45.6 3.829 46.008 4.931 ;
     RECT  52.704 4.261 52.728 4.979 ;
     RECT  54.72 4.501 54.744 4.981 ;
     RECT  54.72 4.981 54.984 5.027 ;
     RECT  13.2 2.151 13.512 5.461 ;
     RECT  24 4.115 24.312 5.461 ;
     RECT  34.8 2.151 35.112 5.461 ;
     RECT  49.824 5.077 49.848 5.603 ;
     RECT  18.6 2.151 18.912 5.605 ;
     RECT  26.112 5.077 26.136 5.651 ;
     RECT  43.632 5.077 43.656 5.653 ;
     RECT  43.632 5.653 43.752 5.699 ;
     RECT  6.864 4.837 8.616 5.747 ;
     RECT  54.816 5.027 54.984 5.747 ;
     RECT  45.6 4.931 45.912 6.037 ;
     RECT  13.2 5.461 14.184 6.085 ;
     RECT  28.464 3.877 29.712 6.133 ;
     RECT  56.4 3.443 56.712 6.229 ;
     RECT  5.136 4.357 5.16 6.469 ;
     RECT  5.136 6.469 5.352 6.515 ;
     RECT  28.128 6.133 29.712 6.755 ;
     RECT  53.04 5.461 53.064 6.757 ;
     RECT  53.04 6.757 53.304 6.803 ;
     RECT  23.376 5.461 24.312 6.851 ;
     RECT  47.088 5.605 47.112 6.851 ;
     RECT  58.56 4.549 58.584 6.851 ;
     RECT  7.8 5.747 8.616 6.853 ;
     RECT  45.6 6.037 46.008 7.141 ;
     RECT  6.912 6.853 8.616 7.235 ;
     RECT  7.8 7.235 8.616 7.331 ;
     RECT  17.856 5.605 18.912 7.331 ;
     RECT  2.4 2.151 2.712 7.381 ;
     RECT  45.024 7.141 46.008 7.427 ;
     RECT  56.16 6.229 56.712 7.427 ;
     RECT  20.016 6.229 20.04 7.619 ;
     RECT  5.184 6.515 5.352 7.667 ;
     RECT  51 2.151 51.312 7.717 ;
     RECT  2.4 7.381 3.432 8.003 ;
     RECT  13.104 6.085 14.184 8.003 ;
     RECT  16.8 4.405 16.824 8.003 ;
     RECT  53.28 6.803 53.304 8.003 ;
     RECT  24 6.851 24.312 8.437 ;
     RECT  36.432 6.805 36.456 8.437 ;
     RECT  36.432 8.437 37.224 8.483 ;
     RECT  58.128 7.813 58.152 8.579 ;
     RECT  40.2 4.115 40.512 8.965 ;
     RECT  61.8 2.151 62.112 9.013 ;
     RECT  13.2 8.003 14.184 9.061 ;
     RECT  47.952 8.437 47.976 9.109 ;
     RECT  5.328 7.667 5.352 9.155 ;
     RECT  37.2 8.483 37.224 9.251 ;
     RECT  50.88 7.717 51.312 9.251 ;
     RECT  15.936 9.061 15.96 9.397 ;
     RECT  15.264 9.397 15.96 9.443 ;
     RECT  34.8 5.461 35.208 9.493 ;
     RECT  41.616 6.805 41.64 9.539 ;
     RECT  28.464 6.755 29.712 9.685 ;
     RECT  24 8.437 24.696 9.829 ;
     RECT  18.6 7.331 18.912 9.877 ;
     RECT  9.408 8.821 9.432 9.971 ;
     RECT  39.36 8.965 40.512 10.067 ;
     RECT  21.648 5.173 21.672 10.213 ;
     RECT  23.76 9.829 24.696 10.307 ;
     RECT  34.176 9.493 35.208 10.307 ;
     RECT  43.728 5.699 43.752 10.309 ;
     RECT  56.4 7.427 56.712 10.309 ;
     RECT  47.952 9.109 48.504 10.355 ;
     RECT  54.96 5.747 54.984 10.355 ;
     RECT  28.32 9.685 29.712 10.453 ;
     RECT  20.688 10.213 21.672 10.645 ;
     RECT  27.888 10.453 29.712 10.837 ;
     RECT  30.768 10.069 30.792 10.837 ;
     RECT  48.48 10.355 48.504 10.883 ;
     RECT  18.288 9.877 18.912 10.931 ;
     RECT  15.264 9.443 15.72 11.075 ;
     RECT  20.688 10.645 21.768 11.459 ;
     RECT  56.304 10.309 56.712 11.459 ;
     RECT  21.648 11.459 21.768 11.653 ;
     RECT  36.96 10.501 36.984 12.085 ;
     RECT  21.648 11.653 22.008 12.181 ;
     RECT  23.76 10.307 24.408 12.181 ;
     RECT  21.648 12.181 24.408 12.227 ;
     RECT  27.888 10.837 30.792 12.277 ;
     RECT  38.736 11.845 38.76 12.277 ;
     RECT  40.2 10.067 40.512 12.277 ;
     RECT  27.888 12.277 31.128 12.419 ;
     RECT  15.264 11.075 15.288 12.563 ;
     RECT  21.648 12.227 22.92 12.563 ;
     RECT  38.736 12.277 40.512 12.563 ;
     RECT  21.888 12.563 22.92 12.755 ;
     RECT  34.176 10.307 35.112 12.755 ;
     RECT  36.72 12.085 36.984 12.755 ;
     RECT  5.904 10.213 5.928 12.853 ;
     RECT  20.496 11.893 20.52 12.853 ;
     RECT  5.808 12.853 5.928 12.899 ;
     RECT  19.968 12.853 20.52 12.899 ;
     RECT  39.312 12.563 40.512 12.997 ;
     RECT  49.536 12.517 49.56 12.997 ;
     RECT  10.32 12.517 10.344 13.045 ;
     RECT  49.008 12.997 49.56 13.093 ;
     RECT  58.416 11.173 58.44 13.139 ;
     RECT  24 12.227 24.408 13.331 ;
     RECT  7.8 7.331 8.112 13.381 ;
     RECT  21.888 12.755 22.008 13.475 ;
     RECT  27.888 12.419 28.008 13.573 ;
     RECT  18.6 10.931 18.912 13.621 ;
     RECT  43.728 10.309 43.944 13.669 ;
     RECT  26.208 12.517 26.232 13.859 ;
     RECT  39.312 12.997 40.728 13.859 ;
     RECT  48.912 13.093 49.56 13.859 ;
     RECT  5.808 12.899 5.832 13.909 ;
     RECT  10.032 13.045 10.344 13.909 ;
     RECT  10.032 13.909 10.824 14.147 ;
     RECT  13.2 9.061 14.232 14.147 ;
     RECT  4.224 11.029 4.248 14.197 ;
     RECT  7.632 13.381 8.112 14.197 ;
     RECT  18.24 13.621 18.912 14.291 ;
     RECT  60.96 9.013 62.112 14.437 ;
     RECT  18.6 14.291 18.912 14.677 ;
     RECT  19.968 12.899 19.992 14.677 ;
     RECT  56.4 11.459 56.712 14.725 ;
     RECT  21.888 13.475 21.912 14.821 ;
     RECT  27.552 13.573 28.008 14.869 ;
     RECT  27.552 14.869 28.104 14.915 ;
     RECT  5.808 13.909 6.168 15.061 ;
     RECT  13.2 14.147 13.992 15.061 ;
     RECT  18.6 14.677 19.992 15.155 ;
     RECT  33.648 14.101 33.672 15.155 ;
     RECT  17.328 14.773 17.352 15.299 ;
     RECT  7.632 14.197 9 15.301 ;
     RECT  10.032 14.147 10.056 15.301 ;
     RECT  36.96 12.755 36.984 15.349 ;
     RECT  11.04 14.677 11.064 15.443 ;
     RECT  12.864 15.061 13.992 15.445 ;
     RECT  12.24 15.445 13.992 15.493 ;
     RECT  29.4 12.419 31.128 15.539 ;
     RECT  12.24 15.493 14.232 15.541 ;
     RECT  15.984 15.493 16.008 15.541 ;
     RECT  48.912 13.859 48.936 15.589 ;
     RECT  53.184 14.197 53.208 15.635 ;
     RECT  43.344 13.669 43.944 15.637 ;
     RECT  5.616 15.061 6.168 15.733 ;
     RECT  7.632 15.301 10.056 15.733 ;
     RECT  43.344 15.637 44.184 15.733 ;
     RECT  12.24 15.541 16.008 15.779 ;
     RECT  36.96 15.349 37.608 15.925 ;
     RECT  5.616 15.733 10.056 16.019 ;
     RECT  12.24 15.779 15.336 16.019 ;
     RECT  27.6 14.915 28.104 16.019 ;
     RECT  48.912 15.589 49.848 16.115 ;
     RECT  31.104 15.539 31.128 16.117 ;
     RECT  36.528 15.925 37.608 16.163 ;
     RECT  18.6 15.155 19.032 16.165 ;
     RECT  51 9.251 51.312 16.165 ;
     RECT  21.12 14.821 21.912 16.259 ;
     RECT  43.344 15.733 44.376 16.259 ;
     RECT  39.312 13.859 40.512 16.261 ;
     RECT  25.68 15.205 25.704 16.309 ;
     RECT  44.16 16.259 44.376 16.309 ;
     RECT  56.4 14.725 57.384 16.309 ;
     RECT  34.8 12.755 35.112 16.357 ;
     RECT  21.648 16.259 21.912 16.405 ;
     RECT  49.824 16.115 49.848 16.451 ;
     RECT  34.32 16.357 35.112 16.501 ;
     RECT  51 16.165 51.912 16.547 ;
     RECT  38.928 16.261 40.512 16.549 ;
     RECT  12.864 16.019 15.336 16.595 ;
     RECT  21.648 16.405 22.2 16.595 ;
     RECT  56.4 16.309 58.152 16.691 ;
     RECT  9.792 16.019 10.056 16.835 ;
     RECT  13.104 16.595 15.336 16.885 ;
     RECT  18.6 16.165 19.656 16.885 ;
     RECT  58.128 16.691 58.152 16.981 ;
     RECT  47.904 16.021 47.928 17.029 ;
     RECT  38.928 16.549 40.872 17.075 ;
     RECT  18.144 16.885 19.656 17.077 ;
     RECT  31.104 16.117 31.512 17.077 ;
     RECT  56.4 16.691 56.712 17.077 ;
     RECT  5.616 16.019 8.232 17.123 ;
     RECT  13.104 16.885 15.384 17.123 ;
     RECT  25.68 16.309 26.232 17.123 ;
     RECT  30.96 17.077 31.512 17.123 ;
     RECT  3.792 14.197 4.248 17.125 ;
     RECT  5.616 17.123 8.112 17.125 ;
     RECT  44.16 16.309 44.616 17.317 ;
     RECT  45.6 7.427 46.008 17.317 ;
     RECT  13.2 17.123 15.384 17.509 ;
     RECT  13.2 17.509 16.008 17.555 ;
     RECT  15.312 17.555 16.008 17.605 ;
     RECT  51 16.547 51.312 17.605 ;
     RECT  22.176 16.595 22.2 17.651 ;
     RECT  39.408 17.075 40.872 17.651 ;
     RECT  54.48 15.877 54.504 17.651 ;
     RECT  27.6 16.019 28.008 17.699 ;
     RECT  40.2 17.651 40.872 17.699 ;
     RECT  18.144 17.077 19.848 17.891 ;
     RECT  24 13.331 24.312 17.893 ;
     RECT  11.424 17.029 11.448 17.939 ;
     RECT  44.16 17.317 46.008 17.987 ;
     RECT  18.144 17.891 19.656 17.989 ;
     RECT  44.16 17.987 45.912 18.179 ;
     RECT  2.4 8.003 2.712 18.181 ;
     RECT  13.2 17.555 14.28 18.275 ;
     RECT  30.96 17.123 31.128 18.275 ;
     RECT  33.36 16.501 35.112 18.275 ;
     RECT  55.872 17.077 56.712 18.419 ;
     RECT  58.128 16.981 58.44 18.419 ;
     RECT  44.16 18.179 44.616 18.613 ;
     RECT  26.208 17.123 26.232 18.661 ;
     RECT  23.52 17.893 24.312 18.709 ;
     RECT  40.2 17.699 40.512 18.709 ;
     RECT  38.112 18.181 38.136 18.755 ;
     RECT  2.4 18.181 2.808 18.757 ;
     RECT  3.792 17.125 8.112 18.757 ;
     RECT  29.4 15.539 29.712 18.757 ;
     RECT  39.36 18.709 40.512 18.851 ;
     RECT  53.376 17.605 53.4 18.851 ;
     RECT  47.328 17.029 47.928 18.947 ;
     RECT  18.096 17.989 19.656 19.045 ;
     RECT  34.32 18.275 35.112 19.091 ;
     RECT  56.4 18.419 56.712 19.093 ;
     RECT  15.312 17.605 16.584 19.331 ;
     RECT  25.92 18.661 26.232 19.333 ;
     RECT  27.6 17.699 27.624 19.333 ;
     RECT  29.088 18.757 29.712 19.333 ;
     RECT  31.104 18.275 31.128 19.333 ;
     RECT  15.36 19.331 16.584 19.427 ;
     RECT  23.52 18.709 24.408 19.475 ;
     RECT  29.088 19.333 31.128 19.619 ;
     RECT  23.52 19.475 24.312 19.621 ;
     RECT  21.072 18.421 21.096 19.667 ;
     RECT  47.328 18.947 47.64 19.763 ;
     RECT  13.2 18.275 13.944 19.909 ;
     RECT  36.528 16.163 36.984 20.005 ;
     RECT  25.92 19.333 27.624 20.099 ;
     RECT  58.176 18.419 58.44 20.149 ;
     RECT  15.984 19.427 16.584 20.243 ;
     RECT  43.536 18.613 44.616 20.293 ;
     RECT  45.6 18.179 45.912 20.293 ;
     RECT  42.672 20.293 45.912 20.339 ;
     RECT  18 19.045 19.656 20.485 ;
     RECT  36.528 20.005 37.608 20.579 ;
     RECT  51 17.605 51.528 20.579 ;
     RECT  56.4 19.093 56.808 20.579 ;
     RECT  2.4 18.757 8.112 20.819 ;
     RECT  29.28 19.619 31.128 20.917 ;
     RECT  23.232 19.621 24.312 21.013 ;
     RECT  40.2 18.851 40.512 21.013 ;
     RECT  22.8 21.013 24.312 21.109 ;
     RECT  25.344 20.389 25.368 21.109 ;
     RECT  13.056 19.909 13.944 21.155 ;
     RECT  36.528 20.579 36.984 21.155 ;
     RECT  44.16 20.339 45.912 21.155 ;
     RECT  54.096 20.149 54.12 21.155 ;
     RECT  58.128 20.149 58.44 21.155 ;
     RECT  16.56 20.243 16.584 21.251 ;
     RECT  28.944 20.917 31.128 21.253 ;
     RECT  42.672 20.339 42.696 21.395 ;
     RECT  40.08 21.013 40.512 21.397 ;
     RECT  22.8 21.109 25.368 21.587 ;
     RECT  28.608 21.253 31.128 21.635 ;
     RECT  28.944 21.635 31.128 21.637 ;
     RECT  22.8 21.587 24.312 21.683 ;
     RECT  40.08 21.397 41.256 22.021 ;
     RECT  58.176 21.155 58.44 22.067 ;
     RECT  7.104 20.819 8.112 22.069 ;
     RECT  56.4 20.579 56.712 22.069 ;
     RECT  39.312 22.021 41.256 22.117 ;
     RECT  51 20.579 51.312 22.117 ;
     RECT  39.312 22.117 41.304 22.165 ;
     RECT  23.52 21.683 24.312 22.259 ;
     RECT  38.496 22.165 41.304 22.451 ;
     RECT  16.512 22.309 16.536 22.549 ;
     RECT  17.904 20.485 19.656 22.549 ;
     RECT  40.2 22.451 41.304 22.693 ;
     RECT  60.48 14.437 62.112 22.693 ;
     RECT  2.4 20.819 5.832 22.741 ;
     RECT  7.104 22.069 8.472 22.741 ;
     RECT  13.2 21.155 13.944 22.741 ;
     RECT  56.208 22.069 56.712 22.741 ;
     RECT  36.96 21.155 36.984 22.837 ;
     RECT  55.92 22.741 56.712 22.883 ;
     RECT  16.512 22.549 19.656 23.029 ;
     RECT  56.4 22.883 56.712 23.029 ;
     RECT  38.496 22.451 38.52 23.221 ;
     RECT  45.6 21.155 45.912 23.221 ;
     RECT  47.616 19.763 47.64 23.221 ;
     RECT  45.6 23.221 47.64 23.267 ;
     RECT  40.2 22.693 42.12 23.269 ;
     RECT  44.16 21.155 44.616 23.315 ;
     RECT  12.24 22.741 13.944 23.317 ;
     RECT  24 22.259 24.312 23.317 ;
     RECT  44.592 23.315 44.616 23.317 ;
     RECT  45.6 23.267 46.728 23.317 ;
     RECT  58.416 22.067 58.44 23.317 ;
     RECT  25.344 21.587 25.368 23.365 ;
     RECT  26.592 20.099 27.624 23.365 ;
     RECT  38.208 23.221 38.52 23.411 ;
     RECT  2.4 22.741 8.472 23.893 ;
     RECT  36.96 22.837 37.08 23.939 ;
     RECT  40.2 23.269 42.936 23.939 ;
     RECT  12.24 23.317 14.76 23.987 ;
     RECT  50.208 22.117 51.312 23.987 ;
     RECT  56.4 23.029 56.808 23.987 ;
     RECT  16.464 23.029 19.656 24.131 ;
     RECT  16.944 24.131 19.656 24.179 ;
     RECT  39.168 24.181 39.192 24.323 ;
     RECT  49.2 23.269 49.224 24.323 ;
     RECT  57.792 23.317 58.44 24.373 ;
     RECT  21.12 22.741 21.144 24.419 ;
     RECT  42.432 23.939 42.936 24.419 ;
     RECT  44.592 23.317 46.728 24.515 ;
     RECT  50.88 23.987 51.312 24.515 ;
     RECT  40.2 23.939 41.256 24.517 ;
     RECT  12.24 23.987 13.944 24.611 ;
     RECT  23.904 23.317 24.312 24.613 ;
     RECT  2.4 23.893 8.52 24.659 ;
     RECT  42.528 24.419 42.936 24.757 ;
     RECT  2.4 24.659 8.472 24.803 ;
     RECT  53.04 23.029 53.064 24.899 ;
     RECT  57.792 24.373 58.536 24.899 ;
     RECT  59.712 22.693 62.112 24.899 ;
     RECT  9.792 16.835 9.816 25.045 ;
     RECT  36.96 23.939 36.984 25.045 ;
     RECT  23.04 24.613 24.312 25.477 ;
     RECT  25.344 23.365 27.624 25.477 ;
     RECT  36.576 25.045 36.984 25.619 ;
     RECT  36.96 25.619 36.984 25.621 ;
     RECT  28.944 21.637 31.368 25.715 ;
     RECT  36.96 25.621 37.32 25.715 ;
     RECT  18.48 24.179 19.656 25.811 ;
     RECT  2.4 24.803 6.216 25.909 ;
     RECT  56.4 23.987 56.712 25.957 ;
     RECT  51 24.515 51.312 26.005 ;
     RECT  29.4 25.715 31.128 26.099 ;
     RECT  39.888 24.517 41.256 26.101 ;
     RECT  39.84 26.101 41.256 26.149 ;
     RECT  42.528 24.757 43.368 26.149 ;
     RECT  60.48 24.899 62.112 26.149 ;
     RECT  33.168 25.621 33.192 26.243 ;
     RECT  50.88 26.005 51.312 26.341 ;
     RECT  16.944 24.179 17.352 26.389 ;
     RECT  50.88 26.341 51.912 26.389 ;
     RECT  0.144 24.133 0.168 26.675 ;
     RECT  9.696 25.045 9.816 26.675 ;
     RECT  2.4 25.909 6.264 26.725 ;
     RECT  7.344 24.803 8.472 26.725 ;
     RECT  31.056 26.099 31.128 26.725 ;
     RECT  34.8 19.091 35.112 26.725 ;
     RECT  48.48 26.245 48.504 26.725 ;
     RECT  9.696 26.675 9.72 26.771 ;
     RECT  44.688 24.515 46.728 26.773 ;
     RECT  23.04 25.477 27.624 26.819 ;
     RECT  39.84 26.149 43.368 26.819 ;
     RECT  48.48 26.725 48.888 26.867 ;
     RECT  44.496 26.773 46.728 27.059 ;
     RECT  60.144 26.149 62.112 27.059 ;
     RECT  23.04 26.819 27.384 27.109 ;
     RECT  56.4 25.957 57 27.205 ;
     RECT  22.992 27.109 27.384 27.395 ;
     RECT  20.928 26.821 20.952 27.635 ;
     RECT  25.344 27.395 27.384 27.635 ;
     RECT  50.304 26.389 51.912 27.635 ;
     RECT  25.344 27.635 26.664 27.683 ;
     RECT  44.496 27.059 45.912 27.733 ;
     RECT  16.368 26.389 17.352 27.829 ;
     RECT  58.416 24.899 58.536 27.829 ;
     RECT  15.408 27.829 17.352 27.875 ;
     RECT  15.408 27.875 17.112 27.877 ;
     RECT  18.6 25.811 19.656 27.877 ;
     RECT  39.84 26.819 42.696 27.923 ;
     RECT  33.36 26.725 35.112 28.261 ;
     RECT  44.448 27.733 45.912 28.307 ;
     RECT  48.864 26.867 48.888 28.309 ;
     RECT  48 28.309 48.888 28.355 ;
     RECT  22.992 27.395 24.312 28.403 ;
     RECT  18.24 27.877 19.656 28.405 ;
     RECT  33.072 28.261 35.112 28.451 ;
     RECT  2.4 26.725 8.472 28.453 ;
     RECT  42.528 27.923 42.696 28.453 ;
     RECT  50.304 27.635 51.672 28.501 ;
     RECT  37.296 25.715 37.32 28.643 ;
     RECT  55.296 27.301 55.32 28.643 ;
     RECT  15.168 27.877 17.112 28.691 ;
     RECT  56.4 27.205 57.288 28.691 ;
     RECT  24 28.403 24.312 28.693 ;
     RECT  15.408 28.691 17.112 28.739 ;
     RECT  10.32 28.693 10.344 28.837 ;
     RECT  29.4 26.099 30.072 28.931 ;
     RECT  49.44 28.501 51.672 29.075 ;
     RECT  48 28.355 48.024 29.123 ;
     RECT  58.416 27.829 58.872 29.123 ;
     RECT  16.704 28.739 17.112 29.219 ;
     RECT  42.528 28.453 43.272 29.317 ;
     RECT  44.688 28.307 45.912 29.317 ;
     RECT  42.528 29.317 45.912 29.363 ;
     RECT  49.44 29.075 51.312 29.413 ;
     RECT  31.056 26.725 31.368 29.459 ;
     RECT  33.072 28.451 33.096 29.459 ;
     RECT  48.96 29.413 51.312 29.459 ;
     RECT  22.992 28.403 23.016 29.507 ;
     RECT  39.84 27.923 41.256 29.509 ;
     RECT  42.528 29.363 42.552 29.509 ;
     RECT  24 28.693 24.408 29.557 ;
     RECT  25.488 27.683 26.664 29.557 ;
     RECT  10.32 28.837 11.16 29.605 ;
     RECT  12.24 24.611 13.512 29.605 ;
     RECT  34.8 28.451 35.112 29.605 ;
     RECT  56.4 28.691 56.712 29.653 ;
     RECT  29.4 28.931 29.832 29.701 ;
     RECT  50.304 29.459 51.312 29.795 ;
     RECT  9.936 29.605 13.512 30.275 ;
     RECT  48.96 29.459 48.984 30.275 ;
     RECT  39.84 29.509 42.552 30.323 ;
     RECT  53.616 29.605 53.64 30.323 ;
     RECT  55.44 29.653 56.712 30.323 ;
     RECT  16.704 29.219 16.968 30.421 ;
     RECT  2.4 28.453 8.952 30.469 ;
     RECT  9.936 30.275 11.16 30.469 ;
     RECT  12.24 30.275 13.512 30.611 ;
     RECT  28.656 29.701 29.832 30.613 ;
     RECT  16.704 30.421 17.064 30.659 ;
     RECT  31.056 29.459 31.128 30.709 ;
     RECT  58.416 29.123 58.536 30.709 ;
     RECT  58.416 30.709 59.064 30.805 ;
     RECT  16.704 30.659 16.728 30.851 ;
     RECT  18.24 28.405 19.992 30.851 ;
     RECT  2.4 30.469 11.16 30.899 ;
     RECT  34.8 29.605 35.352 30.899 ;
     RECT  18.288 30.851 19.992 30.947 ;
     RECT  13.104 30.611 13.512 31.285 ;
     RECT  58.128 30.805 59.064 31.379 ;
     RECT  13.104 31.285 14.28 31.427 ;
     RECT  21.84 30.805 21.864 31.667 ;
     RECT  13.2 31.427 14.28 31.861 ;
     RECT  15.504 30.709 15.528 31.861 ;
     RECT  24 29.557 26.664 31.861 ;
     RECT  2.4 30.899 10.344 31.955 ;
     RECT  28.656 30.613 29.88 31.955 ;
     RECT  38.016 31.525 38.04 32.005 ;
     RECT  34.8 30.899 35.112 32.293 ;
     RECT  56.4 30.323 56.712 32.293 ;
     RECT  18.6 30.947 19.992 32.341 ;
     RECT  24 31.861 27.096 32.437 ;
     RECT  34.704 32.293 35.112 32.483 ;
     RECT  13.2 31.861 15.528 32.629 ;
     RECT  38.016 32.005 38.52 32.629 ;
     RECT  38.016 32.629 38.856 32.723 ;
     RECT  13.104 32.629 15.528 33.013 ;
     RECT  28.656 31.955 29.832 33.107 ;
     RECT  3.792 31.955 10.344 33.155 ;
     RECT  18.6 32.341 20.232 33.155 ;
     RECT  3.792 33.155 5.448 33.347 ;
     RECT  23.04 32.437 27.096 33.445 ;
     RECT  29.4 33.107 29.832 33.539 ;
     RECT  50.4 29.795 51.312 33.541 ;
     RECT  55.056 33.013 55.08 33.541 ;
     RECT  56.4 32.293 56.808 33.541 ;
     RECT  2.4 31.955 2.808 33.589 ;
     RECT  20.16 33.155 20.232 33.635 ;
     RECT  39.84 30.323 41.256 33.637 ;
     RECT  44.208 29.363 45.912 33.637 ;
     RECT  18.6 33.155 19.032 33.685 ;
     RECT  31.056 30.709 31.464 33.685 ;
     RECT  60.48 27.059 62.112 33.779 ;
     RECT  55.056 33.541 56.808 33.827 ;
     RECT  43.776 33.637 45.912 33.875 ;
     RECT  55.056 33.827 56.712 33.971 ;
     RECT  22.752 33.445 27.096 34.165 ;
     RECT  48.72 31.477 48.744 34.213 ;
     RECT  48.72 34.213 49.08 34.259 ;
     RECT  33.6 33.589 33.624 34.309 ;
     RECT  34.8 32.483 35.112 34.309 ;
     RECT  2.4 33.589 3.192 34.355 ;
     RECT  33.6 34.309 35.112 34.355 ;
     RECT  4.368 33.347 5.448 34.501 ;
     RECT  6.528 33.155 10.344 34.501 ;
     RECT  22.608 34.165 27.096 34.501 ;
     RECT  39.84 33.637 41.4 34.549 ;
     RECT  22.608 34.501 27.624 34.741 ;
     RECT  18.48 33.685 19.032 34.787 ;
     RECT  39.84 34.549 41.496 34.835 ;
     RECT  49.056 34.259 49.08 34.835 ;
     RECT  22.224 34.741 27.624 34.979 ;
     RECT  34.224 34.355 35.112 34.979 ;
     RECT  44.208 33.875 45.912 34.979 ;
     RECT  45.6 34.979 45.912 35.077 ;
     RECT  31.056 33.685 31.608 35.125 ;
     RECT  13.008 33.013 15.528 35.221 ;
     RECT  44.208 34.979 44.472 35.315 ;
     RECT  4.368 34.501 10.344 35.317 ;
     RECT  20.16 33.635 20.184 35.317 ;
     RECT  13.008 35.221 15.576 35.363 ;
     RECT  38.496 32.723 38.856 35.363 ;
     RECT  55.92 33.971 56.712 35.363 ;
     RECT  13.2 35.363 15.576 35.411 ;
     RECT  30.864 35.125 31.608 35.411 ;
     RECT  31.056 35.411 31.608 35.459 ;
     RECT  58.416 31.379 59.064 35.605 ;
     RECT  18.6 34.787 19.032 35.699 ;
     RECT  47.424 34.645 47.448 35.699 ;
     RECT  4.128 35.317 10.344 35.701 ;
     RECT  38.496 35.363 38.52 35.701 ;
     RECT  13.2 35.411 14.472 35.747 ;
     RECT  22.224 34.979 26.088 35.939 ;
     RECT  4.128 35.701 10.968 35.941 ;
     RECT  4.128 35.941 11.448 35.987 ;
     RECT  22.608 35.939 26.088 36.227 ;
     RECT  13.2 35.747 13.512 36.517 ;
     RECT  37.632 35.701 38.52 36.755 ;
     RECT  50.16 33.541 51.312 36.755 ;
     RECT  13.104 36.517 13.512 36.851 ;
     RECT  48.528 36.373 48.552 36.947 ;
     RECT  20.16 35.317 20.52 36.997 ;
     RECT  31.584 35.459 31.608 37.091 ;
     RECT  33.216 35.269 33.24 37.091 ;
     RECT  39.84 34.835 41.4 37.091 ;
     RECT  53.184 35.893 53.208 37.091 ;
     RECT  15.504 35.411 15.576 37.093 ;
     RECT  42.528 30.323 42.552 37.141 ;
     RECT  20.16 36.997 20.808 37.573 ;
     RECT  10.368 35.987 11.448 37.619 ;
     RECT  27.072 34.979 27.624 37.619 ;
     RECT  4.128 35.987 9.384 37.667 ;
     RECT  45.6 35.077 46.392 37.669 ;
     RECT  23.232 36.227 26.088 37.763 ;
     RECT  45.6 37.669 46.632 37.811 ;
     RECT  20.112 37.573 21.096 37.957 ;
     RECT  2.4 34.355 2.808 38.005 ;
     RECT  18.6 35.699 18.912 38.005 ;
     RECT  19.968 37.957 21.096 38.005 ;
     RECT  29.4 33.539 29.712 38.149 ;
     RECT  42.192 37.141 42.552 38.149 ;
     RECT  56.4 35.363 56.712 38.149 ;
     RECT  17.04 35.317 17.064 38.387 ;
     RECT  54.48 37.381 54.504 38.485 ;
     RECT  38.064 36.755 38.52 38.533 ;
     RECT  23.232 37.763 24.456 38.771 ;
     RECT  2.4 38.005 2.856 38.819 ;
     RECT  18.6 38.005 21.096 38.819 ;
     RECT  25.488 37.763 26.088 38.819 ;
     RECT  55.68 38.149 56.712 38.819 ;
     RECT  29.4 38.149 30.504 38.915 ;
     RECT  37.584 38.533 38.52 39.011 ;
     RECT  13.2 36.851 13.512 39.013 ;
     RECT  14.784 37.093 15.576 39.059 ;
     RECT  38.064 39.011 38.52 39.157 ;
     RECT  42.192 38.149 42.648 39.251 ;
     RECT  47.712 37.861 47.736 39.253 ;
     RECT  18.6 38.819 20.808 39.299 ;
     RECT  2.4 38.819 2.808 39.301 ;
     RECT  27.6 37.619 27.624 39.301 ;
     RECT  45.6 37.811 45.912 39.301 ;
     RECT  61.8 33.779 62.112 39.301 ;
     RECT  2.304 39.301 2.808 39.347 ;
     RECT  15.504 39.059 15.576 39.395 ;
     RECT  45.6 39.301 46.2 39.635 ;
     RECT  47.712 39.253 48.408 39.635 ;
     RECT  18.6 39.299 19.08 39.877 ;
     RECT  34.8 34.979 35.112 39.877 ;
     RECT  17.088 38.725 17.112 39.923 ;
     RECT  25.488 38.819 25.512 39.973 ;
     RECT  18.336 39.877 19.08 40.163 ;
     RECT  29.4 38.915 29.832 40.165 ;
     RECT  38.064 39.157 38.808 40.165 ;
     RECT  39.84 37.091 41.16 40.165 ;
     RECT  13.2 39.013 13.704 40.259 ;
     RECT  18.48 40.163 19.08 40.309 ;
     RECT  20.16 39.299 20.808 40.309 ;
     RECT  38.064 40.165 41.16 40.499 ;
     RECT  58.416 35.605 59.256 40.499 ;
     RECT  12.144 39.877 12.168 40.595 ;
     RECT  27.6 39.301 28.344 40.595 ;
     RECT  47.712 39.635 48.024 40.595 ;
     RECT  38.496 40.499 41.16 40.643 ;
     RECT  58.416 40.499 58.968 40.693 ;
     RECT  34.176 39.877 35.112 40.835 ;
     RECT  61.536 39.301 62.112 40.835 ;
     RECT  10.368 37.619 10.968 40.981 ;
     RECT  23.328 38.771 24.456 40.981 ;
     RECT  25.488 39.973 26.472 40.981 ;
     RECT  56.4 38.819 56.712 40.981 ;
     RECT  58.032 40.693 58.968 40.981 ;
     RECT  10.368 40.981 11.4 41.027 ;
     RECT  4.128 37.667 5.304 41.029 ;
     RECT  56.4 40.981 58.968 41.029 ;
     RECT  17.184 40.453 17.208 41.075 ;
     RECT  18.48 40.309 20.808 41.171 ;
     RECT  50.88 36.755 51.312 41.269 ;
     RECT  29.4 40.165 30.744 41.363 ;
     RECT  23.328 40.981 26.472 41.411 ;
     RECT  42.624 39.251 42.648 41.509 ;
     RECT  50.448 41.269 51.312 41.557 ;
     RECT  29.4 41.363 29.832 41.605 ;
     RECT  39.456 40.643 41.16 41.605 ;
     RECT  18.6 41.171 20.808 41.651 ;
     RECT  3.888 41.029 5.304 41.891 ;
     RECT  13.2 40.259 13.512 41.893 ;
     RECT  13.104 41.893 13.512 42.083 ;
     RECT  32.112 38.005 32.136 42.227 ;
     RECT  54.432 38.485 54.504 42.227 ;
     RECT  55.872 41.029 58.968 42.275 ;
     RECT  20.256 41.651 20.808 42.323 ;
     RECT  34.272 40.835 35.112 42.373 ;
     RECT  39.12 41.605 41.16 42.467 ;
     RECT  2.304 39.347 2.712 42.613 ;
     RECT  29.04 41.605 29.832 42.755 ;
     RECT  56.4 42.275 58.968 42.803 ;
     RECT  23.328 41.411 26.04 42.805 ;
     RECT  23.328 42.805 26.328 42.851 ;
     RECT  50.4 41.557 51.312 42.853 ;
     RECT  49.92 42.853 51.312 42.995 ;
     RECT  24 42.851 26.328 43.091 ;
     RECT  39.84 42.467 41.16 43.091 ;
     RECT  13.2 42.083 13.512 43.093 ;
     RECT  36.576 38.725 36.6 43.285 ;
     RECT  44.208 35.315 44.232 43.285 ;
     RECT  45.6 39.635 45.912 43.285 ;
     RECT  29.184 42.755 29.832 43.331 ;
     RECT  2.304 42.613 2.856 43.379 ;
     RECT  4.128 41.891 5.304 43.379 ;
     RECT  24 43.091 26.184 43.379 ;
     RECT  31.872 42.709 31.896 43.379 ;
     RECT  36.48 43.285 36.6 43.379 ;
     RECT  58.416 42.803 58.968 43.523 ;
     RECT  34.224 42.373 35.112 43.571 ;
     RECT  13.2 43.093 13.608 43.667 ;
     RECT  34.8 43.571 35.112 43.717 ;
     RECT  6.288 37.667 9.384 43.859 ;
     RECT  24 43.379 26.04 43.859 ;
     RECT  22.272 43.141 22.296 43.907 ;
     RECT  27.6 40.595 27.624 43.909 ;
     RECT  4.176 43.379 5.304 43.955 ;
     RECT  27.6 43.909 27.768 43.955 ;
     RECT  56.4 42.803 57.144 44.003 ;
     RECT  9.36 43.859 9.384 44.195 ;
     RECT  36.48 43.379 36.504 44.339 ;
     RECT  42.624 41.509 42.84 44.389 ;
     RECT  44.208 43.285 45.912 44.389 ;
     RECT  24 43.859 25.368 44.437 ;
     RECT  29.28 43.331 29.832 44.629 ;
     RECT  34.8 43.717 35.304 44.725 ;
     RECT  60.48 33.779 60.504 44.725 ;
     RECT  61.8 40.835 62.112 44.725 ;
     RECT  29.088 44.629 29.832 44.915 ;
     RECT  60.48 44.725 62.112 44.915 ;
     RECT  15.552 39.395 15.576 44.965 ;
     RECT  20.784 42.323 20.808 44.965 ;
     RECT  23.088 44.437 25.368 44.965 ;
     RECT  54.432 42.227 54.456 44.965 ;
     RECT  58.512 43.523 58.968 44.965 ;
     RECT  10.368 41.027 10.392 45.013 ;
     RECT  11.376 41.027 11.4 45.013 ;
     RECT  2.304 43.379 2.712 45.203 ;
     RECT  34.8 44.725 35.352 45.587 ;
     RECT  54.432 44.965 54.936 45.635 ;
     RECT  61.008 44.915 62.112 45.635 ;
     RECT  47.712 40.595 47.736 45.779 ;
     RECT  14.832 44.965 15.576 45.875 ;
     RECT  42.624 44.389 45.912 45.971 ;
     RECT  43.344 45.971 45.912 46.117 ;
     RECT  10.368 45.013 11.4 46.211 ;
     RECT  37.536 45.301 37.56 46.211 ;
     RECT  54.912 45.635 54.936 46.211 ;
     RECT  57.936 44.965 58.968 46.211 ;
     RECT  20.256 44.965 20.808 46.259 ;
     RECT  43.344 46.117 46.776 46.307 ;
     RECT  34.8 45.587 35.304 46.309 ;
     RECT  23.088 44.965 26.184 46.355 ;
     RECT  33.84 46.309 35.304 46.547 ;
     RECT  43.584 46.307 46.776 46.595 ;
     RECT  5.28 43.955 5.304 46.693 ;
     RECT  6.288 43.859 8.112 46.693 ;
     RECT  29.28 44.915 29.832 46.693 ;
     RECT  5.28 46.693 8.112 46.739 ;
     RECT  39.84 43.091 40.512 46.739 ;
     RECT  57.936 46.211 58.536 46.739 ;
     RECT  4.176 43.955 4.2 46.787 ;
     RECT  5.376 46.739 8.112 46.787 ;
     RECT  18.6 41.651 19.08 46.787 ;
     RECT  20.784 46.259 20.808 46.787 ;
     RECT  24 46.355 26.184 46.787 ;
     RECT  53.568 45.829 53.592 46.787 ;
     RECT  29.28 46.693 30.792 46.835 ;
     RECT  11.376 46.211 11.4 46.883 ;
     RECT  33.84 46.547 35.112 47.269 ;
     RECT  14.928 45.875 15.576 47.315 ;
     RECT  58.368 46.739 58.536 47.317 ;
     RECT  24 46.787 25.752 47.363 ;
     RECT  29.28 46.835 29.832 47.363 ;
     RECT  56.4 44.003 56.712 47.365 ;
     RECT  6.72 46.787 8.112 47.411 ;
     RECT  54.72 46.741 54.744 47.603 ;
     RECT  13.2 43.667 13.512 47.845 ;
     RECT  18.6 46.787 18.912 47.845 ;
     RECT  29.4 47.363 29.832 47.845 ;
     RECT  43.584 46.595 45.912 47.845 ;
     RECT  58.368 47.317 59.496 47.845 ;
     RECT  15.552 47.315 15.576 47.939 ;
     RECT  27.744 43.955 27.768 47.939 ;
     RECT  39.936 46.739 40.512 47.939 ;
     RECT  43.2 47.845 45.912 47.939 ;
     RECT  26.736 47.317 26.76 48.179 ;
     RECT  56.4 47.365 57.336 48.229 ;
     RECT  58.368 47.845 60.456 48.229 ;
     RECT  5.376 46.787 5.4 48.421 ;
     RECT  7.584 47.411 8.112 48.515 ;
     RECT  10.368 46.211 10.392 48.515 ;
     RECT  24 47.363 24.456 48.515 ;
     RECT  33.648 47.269 35.112 48.515 ;
     RECT  43.2 47.939 43.608 48.515 ;
     RECT  50.88 42.995 51.312 48.515 ;
     RECT  56.4 48.229 60.456 48.515 ;
     RECT  4.512 48.421 5.4 48.707 ;
     RECT  44.688 47.939 45.912 48.755 ;
     RECT  12.816 47.845 13.512 48.995 ;
     RECT  18.6 47.845 19.032 48.995 ;
     RECT  16.752 46.309 16.776 49.043 ;
     RECT  22.8 47.845 22.824 49.043 ;
     RECT  29.4 47.845 30.696 49.043 ;
     RECT  52.992 48.997 53.016 49.139 ;
     RECT  33.648 48.515 33.672 49.379 ;
     RECT  4.512 48.707 4.536 49.475 ;
     RECT  25.728 47.363 25.752 49.475 ;
     RECT  40.08 47.939 40.512 49.523 ;
     RECT  2.4 45.203 2.712 49.689 ;
     RECT  7.8 48.515 8.112 49.689 ;
     RECT  13.2 48.995 13.512 49.689 ;
     RECT  18.6 48.995 18.912 49.689 ;
     RECT  24 48.515 24.312 49.689 ;
     RECT  29.4 49.043 29.712 49.689 ;
     RECT  34.8 48.515 35.112 49.689 ;
     RECT  40.2 49.523 40.512 49.689 ;
     RECT  45.6 48.755 45.912 49.689 ;
     RECT  51 48.515 51.312 49.689 ;
     RECT  61.8 45.635 62.112 49.689 ;
     RECT  2.4 49.689 2.52 49.703 ;
     RECT  7.8 49.689 7.92 49.703 ;
     RECT  13.2 49.689 13.32 49.703 ;
     RECT  18.6 49.689 18.72 49.703 ;
     RECT  24 49.689 24.12 49.703 ;
     RECT  29.4 49.689 29.52 49.703 ;
     RECT  34.8 49.689 34.92 49.703 ;
     RECT  40.2 49.689 40.32 49.703 ;
     RECT  45.6 49.689 45.72 49.703 ;
     RECT  51 49.689 51.12 49.703 ;
     RECT  56.4 48.515 59.112 49.703 ;
     RECT  61.8 49.689 61.92 49.703 ;
     RECT  56.88 49.703 59.112 51.637 ;
     RECT  56.88 51.637 59.208 51.756 ;
     RECT  56.904 51.756 56.976 51.792 ;
     RECT  57 51.756 57.072 51.792 ;
     RECT  57.096 51.756 57.168 51.792 ;
     RECT  57.192 51.756 57.264 51.792 ;
     RECT  57.288 51.756 57.36 51.792 ;
     RECT  57.384 51.756 57.456 51.792 ;
     RECT  57.48 51.756 57.552 51.792 ;
     RECT  57.576 51.756 57.648 51.792 ;
     RECT  57.672 51.756 57.744 51.792 ;
     RECT  57.768 51.756 57.84 51.792 ;
     RECT  57.864 51.756 57.936 51.792 ;
     RECT  57.96 51.756 58.032 51.792 ;
     RECT  58.056 51.756 58.128 51.792 ;
     RECT  58.152 51.756 58.224 51.792 ;
     RECT  58.248 51.756 58.32 51.792 ;
     RECT  58.344 51.756 58.416 51.792 ;
     RECT  58.44 51.756 58.512 51.792 ;
     RECT  58.536 51.756 58.608 51.792 ;
     RECT  58.632 51.756 58.704 51.792 ;
     RECT  58.728 51.756 58.8 51.792 ;
     RECT  58.824 51.756 58.896 51.792 ;
     RECT  58.92 51.756 58.992 51.792 ;
     RECT  59.016 51.756 59.088 51.792 ;
     RECT  59.112 51.756 59.184 51.792 ;
     RECT  35.112 2.677 36.192 2.963 ;
     RECT  23.376 4.115 24 5.461 ;
     RECT  51.312 4.261 52.704 4.979 ;
     RECT  45.912 4.931 46.008 5.605 ;
     RECT  54.984 4.981 56.4 6.229 ;
     RECT  49.848 5.077 51 5.603 ;
     RECT  16.824 5.605 17.856 7.331 ;
     RECT  45.912 5.605 47.088 6.037 ;
     RECT  6.912 5.747 7.8 6.853 ;
     RECT  46.008 6.037 47.088 6.851 ;
     RECT  18.912 6.229 20.016 7.619 ;
     RECT  54.984 6.229 56.16 7.427 ;
     RECT  35.208 6.805 36.432 8.483 ;
     RECT  40.512 6.805 41.616 9.539 ;
     RECT  43.752 7.141 45.024 7.427 ;
     RECT  8.112 7.331 8.616 8.821 ;
     RECT  54.984 7.427 56.4 10.309 ;
     RECT  56.712 7.813 58.128 8.579 ;
     RECT  8.112 8.821 9.408 9.971 ;
     RECT  14.232 9.397 15.264 12.563 ;
     RECT  29.712 10.069 30.768 10.837 ;
     RECT  54.984 10.309 56.304 10.355 ;
     RECT  2.712 11.029 4.224 14.197 ;
     RECT  20.688 11.459 21.648 11.893 ;
     RECT  38.76 11.845 40.2 12.277 ;
     RECT  20.52 11.893 21.648 12.563 ;
     RECT  22.92 12.227 24 12.755 ;
     RECT  28.008 12.419 29.4 14.869 ;
     RECT  49.56 12.517 51 13.859 ;
     RECT  20.52 12.563 21.888 12.899 ;
     RECT  34.176 12.755 34.8 14.101 ;
     RECT  18.912 12.853 19.968 14.677 ;
     RECT  5.832 12.899 5.928 13.909 ;
     RECT  26.232 13.573 27.552 13.859 ;
     RECT  6.168 13.909 7.632 15.733 ;
     RECT  33.672 14.101 34.8 15.155 ;
     RECT  10.056 14.147 10.824 14.677 ;
     RECT  13.992 14.147 14.232 15.493 ;
     RECT  2.712 14.197 3.792 18.181 ;
     RECT  9 14.197 10.032 15.301 ;
     RECT  18.24 14.291 18.6 14.773 ;
     RECT  10.056 14.677 11.04 15.443 ;
     RECT  17.352 14.773 18.6 15.299 ;
     RECT  19.992 14.821 21.12 15.155 ;
     RECT  28.104 14.869 29.4 16.019 ;
     RECT  27.552 14.915 27.6 16.309 ;
     RECT  4.248 15.061 5.616 17.125 ;
     RECT  19.032 15.155 21.12 16.165 ;
     RECT  33.648 15.155 34.8 16.357 ;
     RECT  24.312 15.205 25.68 17.123 ;
     RECT  29.712 15.539 31.104 17.077 ;
     RECT  49.848 15.589 51 16.451 ;
     RECT  44.184 15.637 45.6 15.733 ;
     RECT  44.376 15.733 45.6 16.309 ;
     RECT  15.336 15.779 15.384 16.885 ;
     RECT  35.112 15.925 36.528 21.155 ;
     RECT  28.008 16.019 29.4 17.699 ;
     RECT  47.928 16.021 48.912 16.115 ;
     RECT  19.656 16.165 21.12 16.259 ;
     RECT  19.656 16.259 19.848 17.077 ;
     RECT  26.232 16.309 27.6 19.333 ;
     RECT  44.616 16.309 45.6 17.317 ;
     RECT  33.648 16.357 34.32 16.501 ;
     RECT  51.312 16.547 51.528 17.605 ;
     RECT  56.712 16.691 58.128 18.419 ;
     RECT  46.008 17.029 47.328 17.987 ;
     RECT  38.928 17.075 39.408 17.651 ;
     RECT  29.712 17.077 30.96 18.275 ;
     RECT  54.504 17.077 55.872 17.651 ;
     RECT  14.28 17.555 15.312 18.275 ;
     RECT  53.4 17.605 54.48 17.651 ;
     RECT  38.928 17.651 40.2 18.181 ;
     RECT  27.624 17.699 29.4 18.757 ;
     RECT  19.656 17.891 19.848 18.421 ;
     RECT  45.912 17.987 47.328 19.763 ;
     RECT  16.584 17.989 18.096 19.045 ;
     RECT  44.616 18.179 45.6 20.293 ;
     RECT  2.808 18.181 3.792 18.757 ;
     RECT  36.984 18.181 38.112 18.755 ;
     RECT  38.136 18.181 40.2 18.709 ;
     RECT  13.944 18.275 15.312 19.331 ;
     RECT  29.712 18.275 31.104 19.333 ;
     RECT  56.712 18.419 58.176 19.093 ;
     RECT  19.656 18.421 21.072 19.667 ;
     RECT  24.408 18.709 25.92 19.475 ;
     RECT  38.136 18.709 39.36 18.755 ;
     RECT  36.984 18.755 37.608 20.005 ;
     RECT  27.624 18.757 29.088 19.619 ;
     RECT  16.584 19.045 18 20.485 ;
     RECT  56.808 19.093 58.176 20.149 ;
     RECT  13.944 19.331 15.36 19.427 ;
     RECT  24.312 19.475 25.92 20.099 ;
     RECT  27.624 19.619 29.28 20.917 ;
     RECT  24.312 20.099 26.592 20.389 ;
     RECT  56.808 20.149 58.128 20.579 ;
     RECT  42.696 20.339 44.16 21.395 ;
     RECT  24.312 20.389 25.344 21.109 ;
     RECT  25.368 20.389 26.592 23.365 ;
     RECT  16.584 20.485 17.904 21.251 ;
     RECT  56.712 20.579 58.128 21.155 ;
     RECT  5.832 20.819 7.104 22.741 ;
     RECT  27.624 20.917 28.944 21.253 ;
     RECT  44.616 21.155 45.6 23.317 ;
     RECT  56.712 21.155 58.176 22.067 ;
     RECT  16.56 21.251 17.904 22.309 ;
     RECT  27.624 21.253 28.608 21.635 ;
     RECT  24.312 21.587 25.344 25.477 ;
     RECT  27.624 21.635 28.944 25.715 ;
     RECT  56.712 22.067 58.416 23.029 ;
     RECT  8.472 22.069 9.792 23.893 ;
     RECT  36.984 22.165 38.496 22.837 ;
     RECT  23.904 22.259 24 23.317 ;
     RECT  16.536 22.309 17.904 22.549 ;
     RECT  58.44 22.693 59.712 24.373 ;
     RECT  19.656 22.741 21.12 24.419 ;
     RECT  37.08 22.837 38.496 23.221 ;
     RECT  56.808 23.029 58.416 23.317 ;
     RECT  37.08 23.221 38.208 23.411 ;
     RECT  42.936 23.269 44.16 23.315 ;
     RECT  49.224 23.269 50.208 23.987 ;
     RECT  42.936 23.315 44.592 24.515 ;
     RECT  56.808 23.317 57.792 23.987 ;
     RECT  8.52 23.893 9.792 24.659 ;
     RECT  41.256 23.939 42.432 24.419 ;
     RECT  56.712 23.987 57.792 24.899 ;
     RECT  17.352 24.179 18.48 25.811 ;
     RECT  39.192 24.181 40.2 24.323 ;
     RECT  39.888 24.323 40.2 24.517 ;
     RECT  58.536 24.373 59.712 24.899 ;
     RECT  41.256 24.419 42.528 26.149 ;
     RECT  42.936 24.515 44.688 24.757 ;
     RECT  50.88 24.515 51 26.005 ;
     RECT  8.472 24.659 9.792 25.045 ;
     RECT  43.368 24.757 44.688 26.773 ;
     RECT  6.216 24.803 7.344 25.909 ;
     RECT  56.712 24.899 58.416 25.957 ;
     RECT  60.144 24.899 60.48 26.149 ;
     RECT  8.472 25.045 9.696 26.771 ;
     RECT  35.112 25.045 36.576 25.619 ;
     RECT  31.128 25.715 31.368 26.725 ;
     RECT  17.352 25.811 18.6 27.875 ;
     RECT  6.264 25.909 7.344 26.725 ;
     RECT  57 25.957 58.416 27.205 ;
     RECT  30.072 26.099 31.056 28.931 ;
     RECT  48.888 26.725 50.304 28.355 ;
     RECT  43.368 26.773 44.496 26.819 ;
     RECT  44.448 26.819 44.496 27.733 ;
     RECT  19.656 26.821 20.928 27.635 ;
     RECT  48.48 26.867 48.864 28.309 ;
     RECT  57.288 27.205 58.416 28.691 ;
     RECT  55.32 27.301 56.4 28.643 ;
     RECT  24.312 27.395 25.344 27.683 ;
     RECT  19.656 27.635 19.992 28.405 ;
     RECT  24.312 27.683 25.488 28.693 ;
     RECT  17.112 27.875 18.6 27.877 ;
     RECT  17.112 27.877 18.24 29.219 ;
     RECT  41.256 27.923 42.528 29.509 ;
     RECT  44.448 28.307 44.688 28.453 ;
     RECT  48.024 28.355 50.304 28.501 ;
     RECT  23.016 28.403 24 29.507 ;
     RECT  43.272 28.453 44.688 29.317 ;
     RECT  48.024 28.501 49.44 29.123 ;
     RECT  55.44 28.643 56.4 29.653 ;
     RECT  8.952 28.693 10.32 29.605 ;
     RECT  24.408 28.693 25.488 29.557 ;
     RECT  11.16 28.837 12.24 29.605 ;
     RECT  29.832 28.931 31.056 30.613 ;
     RECT  48.96 29.123 49.44 29.413 ;
     RECT  16.968 29.219 18.24 30.421 ;
     RECT  31.128 29.459 31.368 30.709 ;
     RECT  48.984 29.459 50.304 29.795 ;
     RECT  8.952 29.605 9.936 30.469 ;
     RECT  48.984 29.795 50.4 30.275 ;
     RECT  11.16 30.275 12.24 30.611 ;
     RECT  41.256 30.323 42.528 33.637 ;
     RECT  17.064 30.421 18.24 30.659 ;
     RECT  29.88 30.613 31.056 31.955 ;
     RECT  16.728 30.659 18.24 30.851 ;
     RECT  15.528 30.709 16.704 30.851 ;
     RECT  59.064 30.709 60.48 35.605 ;
     RECT  56.712 30.805 58.128 31.379 ;
     RECT  14.28 31.285 15.504 31.861 ;
     RECT  56.712 31.379 56.808 32.293 ;
     RECT  13.104 31.427 13.2 32.629 ;
     RECT  2.808 31.955 3.792 33.347 ;
     RECT  29.832 31.955 31.056 33.539 ;
     RECT  38.52 32.005 39.84 32.629 ;
     RECT  34.704 32.483 34.8 33.589 ;
     RECT  38.856 32.629 39.84 35.363 ;
     RECT  55.08 33.013 56.4 33.541 ;
     RECT  5.448 33.155 6.528 34.501 ;
     RECT  19.032 33.155 20.16 35.699 ;
     RECT  2.808 33.347 4.368 33.589 ;
     RECT  29.712 33.539 31.056 35.125 ;
     RECT  48.744 33.541 50.16 34.213 ;
     RECT  3.192 33.589 4.368 34.355 ;
     RECT  33.624 33.589 34.8 34.309 ;
     RECT  41.4 33.637 42.528 34.549 ;
     RECT  42.552 33.637 43.776 33.875 ;
     RECT  60.504 33.779 61.8 39.301 ;
     RECT  49.08 34.213 50.16 34.835 ;
     RECT  2.808 34.355 4.368 35.317 ;
     RECT  41.496 34.549 42.528 34.835 ;
     RECT  45.912 34.645 47.424 35.077 ;
     RECT  41.4 34.835 42.528 37.091 ;
     RECT  26.088 34.979 27.072 37.619 ;
     RECT  44.472 34.979 45.6 35.315 ;
     RECT  46.392 35.077 47.424 35.699 ;
     RECT  29.712 35.125 30.864 35.411 ;
     RECT  44.232 35.315 45.6 43.285 ;
     RECT  2.808 35.317 4.128 38.005 ;
     RECT  15.576 35.317 17.04 38.387 ;
     RECT  13.104 35.363 13.2 36.517 ;
     RECT  38.52 35.363 39.84 39.157 ;
     RECT  14.472 35.411 15.504 35.747 ;
     RECT  29.712 35.411 31.056 35.459 ;
     RECT  59.256 35.605 60.48 40.499 ;
     RECT  18.912 35.699 20.16 37.573 ;
     RECT  13.512 35.747 15.504 37.093 ;
     RECT  9.384 35.987 10.368 44.195 ;
     RECT  41.16 37.091 42.528 37.141 ;
     RECT  13.512 37.093 14.784 39.013 ;
     RECT  41.16 37.141 42.192 39.251 ;
     RECT  18.912 37.573 20.112 37.957 ;
     RECT  26.088 37.619 27.6 38.819 ;
     RECT  5.304 37.667 6.288 46.693 ;
     RECT  24.456 37.763 25.488 40.981 ;
     RECT  45.912 37.811 46.632 37.861 ;
     RECT  45.912 37.861 47.712 39.301 ;
     RECT  18.912 37.957 19.968 38.005 ;
     RECT  2.856 38.005 4.128 38.819 ;
     RECT  54.504 38.149 55.68 38.819 ;
     RECT  15.576 38.387 17.064 38.725 ;
     RECT  15.576 38.725 17.088 39.923 ;
     RECT  17.112 38.725 18.6 39.877 ;
     RECT  35.112 38.725 36.576 43.285 ;
     RECT  36.6 38.725 37.584 39.011 ;
     RECT  2.808 38.819 4.128 39.347 ;
     RECT  25.512 38.819 27.6 39.973 ;
     RECT  29.832 38.915 30.504 40.165 ;
     RECT  36.6 39.011 38.064 40.499 ;
     RECT  13.704 39.013 14.784 39.059 ;
     RECT  38.808 39.157 39.84 40.165 ;
     RECT  41.16 39.251 42.624 43.091 ;
     RECT  19.08 39.299 20.16 40.309 ;
     RECT  28.344 39.301 29.4 40.595 ;
     RECT  46.2 39.301 47.712 39.635 ;
     RECT  60.504 39.301 61.536 40.835 ;
     RECT  2.712 39.347 4.128 41.029 ;
     RECT  10.968 39.877 12.144 40.595 ;
     RECT  12.168 39.877 13.2 40.595 ;
     RECT  17.112 39.877 18.336 39.923 ;
     RECT  17.184 39.923 18.336 40.163 ;
     RECT  26.472 39.973 27.6 41.411 ;
     RECT  17.184 40.163 18.48 40.453 ;
     RECT  30.744 40.165 32.112 41.363 ;
     RECT  17.208 40.453 18.48 41.075 ;
     RECT  58.968 40.499 60.48 44.915 ;
     RECT  10.968 40.595 11.4 40.981 ;
     RECT  13.104 40.595 13.2 41.893 ;
     RECT  27.624 40.595 29.4 41.605 ;
     RECT  39.12 40.643 39.456 41.605 ;
     RECT  56.712 40.693 58.032 40.981 ;
     RECT  60.504 40.835 61.8 44.725 ;
     RECT  10.392 41.027 11.376 45.013 ;
     RECT  2.712 41.029 3.888 41.891 ;
     RECT  54.504 41.029 55.872 42.227 ;
     RECT  31.872 41.363 32.112 42.227 ;
     RECT  26.04 41.411 27.6 42.805 ;
     RECT  42.84 41.509 44.208 44.389 ;
     RECT  27.624 41.605 29.04 42.755 ;
     RECT  19.08 41.651 20.256 42.323 ;
     RECT  2.712 41.891 4.128 42.613 ;
     RECT  31.872 42.227 31.896 42.709 ;
     RECT  54.456 42.227 55.872 42.275 ;
     RECT  2.856 42.613 4.128 43.379 ;
     RECT  27.624 42.755 29.184 43.331 ;
     RECT  57.144 42.803 58.416 43.523 ;
     RECT  26.328 42.805 27.6 43.091 ;
     RECT  26.184 43.091 27.6 43.379 ;
     RECT  20.808 43.141 22.272 43.907 ;
     RECT  35.112 43.285 36.48 43.717 ;
     RECT  27.624 43.331 29.28 43.909 ;
     RECT  2.712 43.379 4.176 46.787 ;
     RECT  57.144 43.523 58.512 44.003 ;
     RECT  13.512 43.667 13.608 44.965 ;
     RECT  35.304 43.717 36.48 44.339 ;
     RECT  8.112 43.859 9.36 44.195 ;
     RECT  25.368 43.859 26.04 44.965 ;
     RECT  27.768 43.909 29.28 44.629 ;
     RECT  4.2 43.955 5.28 46.739 ;
     RECT  56.712 44.003 58.512 44.965 ;
     RECT  35.304 44.339 35.352 44.725 ;
     RECT  27.768 44.629 29.088 44.915 ;
     RECT  27.768 44.915 29.28 47.363 ;
     RECT  13.512 44.965 14.832 45.875 ;
     RECT  19.08 44.965 20.256 46.259 ;
     RECT  54.936 44.965 56.4 46.211 ;
     RECT  56.712 44.965 57.936 46.739 ;
     RECT  54.432 45.635 54.912 45.829 ;
     RECT  53.592 45.829 54.912 46.211 ;
     RECT  13.512 45.875 14.928 47.315 ;
     RECT  10.392 46.211 11.376 46.883 ;
     RECT  53.592 46.211 54.744 46.741 ;
     RECT  58.536 46.211 58.968 47.317 ;
     RECT  15.576 46.309 16.752 47.939 ;
     RECT  23.088 46.355 24 47.845 ;
     RECT  4.2 46.739 5.376 46.787 ;
     RECT  56.712 46.739 58.368 47.365 ;
     RECT  53.592 46.741 54.72 46.787 ;
     RECT  5.4 46.787 6.72 47.411 ;
     RECT  18.912 46.787 19.032 47.845 ;
     RECT  25.752 46.787 26.184 47.317 ;
     RECT  29.832 46.835 30.696 47.845 ;
     RECT  25.752 47.317 26.736 48.179 ;
     RECT  26.76 47.317 27.744 47.939 ;
     RECT  24.456 47.363 25.728 48.515 ;
     RECT  57.336 47.365 58.368 48.229 ;
     RECT  22.824 47.845 24 49.043 ;
     RECT  60.456 47.845 61.8 48.515 ;
     RECT  43.608 47.939 44.688 48.515 ;
     RECT  24.312 48.515 25.728 49.475 ;
     RECT  33.672 48.515 34.8 49.379 ;
  END
END qkd_controller_hbm_calendar
END LIBRARY
